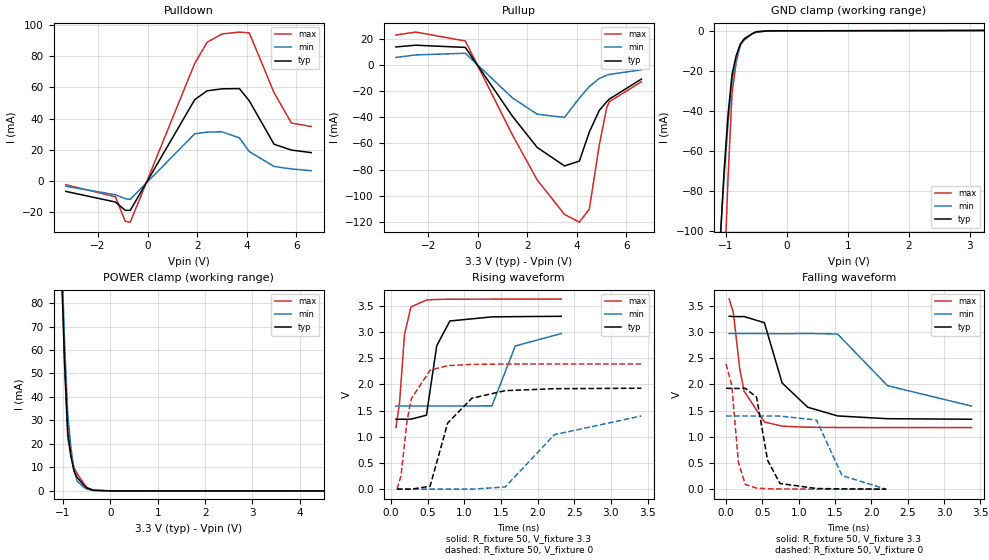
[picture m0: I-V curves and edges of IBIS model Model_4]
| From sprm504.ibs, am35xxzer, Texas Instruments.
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| Model based on original model for BC1833DV40CTPBFHP18LL_7LM
|   Sub model HP18LL_7LM_PD_ON_3P3
[model]   Model_4
|[Description]  3.3V-I/O-PD-X
|[Input Load]   PD
|[Output Drive]
|Voltage   3.3V
|Mode   I/O
Model_type   I/O
Polarity   Non-Inverting
Enable   Active-Low
Vinl =  0.8V
Vinh =  2V
Cref =  15pF
Rref =  100.0000M
Vref =  0V
Vmeas =  1.65
C_comp   1.943144p   1.721292p   2.064363p
[Model Spec]
Vinl   0.8V   0.8V   0.8V
Vinh   2V   2V   2V
[Temperature Range]   25   125   -40
[Voltage Range]   3.3   2.97   3.63
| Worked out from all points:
|   slope of the pulldown table from 0 to 0.495 V, typ, clamps not added: 31.5 ohm
|   slope of the pullup table from 0 to 0.495 V, typ, clamps not added: 34.6 ohm
|   GND clamp passes 1 mA (typ) near -0.54 V on its own axis
|   POWER clamp passes 1 mA (typ) near -0.47 V on its own axis
|   rising waveform, R_fixture 50, V_fixture 3.3: 20-80 % time 130ps typ, 194ps min, 86.4ps max; typ from 1.33 V to 3.3 V
|   rising waveform, R_fixture 50, V_fixture 0: 20-80 % time 307ps typ, 705ps min, 172ps max; typ from 0 V to 1.93 V
|   falling waveform, R_fixture 50, V_fixture 3.3: 20-80 % time 359ps typ, 776ps min, 182ps max; typ from 3.3 V to 1.33 V
|   falling waveform, R_fixture 50, V_fixture 0: 20-80 % time 150ps typ, 232ps min, 88.8ps max; typ from 1.93 V to 0 V
[POWER_clamp]
-3.3V     2.432A     2.868A     2.62A
-1.033V   95.16mA    103.3mA    97mA
-966.7mV  55mA       63.41mA    53.17mA
-900mV    25.28mA    32.79mA    22.49mA
-833.3mV  14.83mA    18.47mA    14.88mA
-766.7mV  8.299mA    8.929mA    9.847mA
-700mV    5.694mA    4.162mA    7.387mA
-566.7mV  2.611mA    1.646mA    3.301mA
-500mV    1.319mA    827.8uA    1.568mA
-366.7mV  287.8uA    192.2uA    368.8uA
33.33mV   0A         0A         0A
6.6V      0A         0A         0A
[Pulldown]
-3.3V     -6.725mA   -3.434mA   -2.443mA
-1.3V     -13.53mA   -8.888mA   -10.15mA
-900mV    -18.85mA   -11.39mA   -25.88mA
-700mV    -18.89mA   -11.82mA   -26.46mA
1.9V      52.07mA    30.2mA     75.32mA
2.4V      57.75mA    31.28mA    88.86mA
3V        59.01mA    31.49mA    94.2mA
3.7V      59.19mA    27.61mA    95.39mA
4.1V      51.39mA    18.8mA     94.89mA
5.1V      23.52mA    9.29mA     56.6mA
5.8V      19.77mA    7.67mA     37.13mA
6.6V      18.13mA    6.544mA    34.86mA
[Pullup]
-3.3V     13.83mA    5.807mA    23.01mA
-2.5V     15.14mA    7.704mA    25.18mA
-500mV    13.45mA    8.979mA    18.37mA
1.4V      -39.2mA    -25.2mA    -53.56mA
2.4V      -63.13mA   -37.64mA   -88mA
3.5V      -77.24mA   -40.1mA    -114.3mA
4.1V      -73.54mA   -25.36mA   -120.3mA
4.5V      -51.37mA   -16.52mA   -110.3mA
4.9V      -34.86mA   -10.34mA   -61.5mA
5.2V      -28.21mA   -7.863mA   -32.95mA
5.3V      -26.19mA   -7.237mA   -28.18mA
6.6V      -10.79mA   -3.71mA    -12.85mA
[GND_clamp]
-3.3V     -2.048A    -1.805A    -3.667A
-1.1V     -108.6mA   -106.5mA   -191.4mA
-1.033V   -71.11mA   -74.03mA   -127.7mA
-966.7mV  -42.17mA   -46.82mA   -74.25mA
-900mV    -21.74mA   -24.87mA   -31.11mA
-833.3mV  -12.59mA   -14.47mA   -16.1mA
-766.7mV  -6.71mA    -7.469mA   -7.269mA
-700mV    -4.089mA   -3.883mA   -4.623mA
-566.7mV  -1.428mA   -1.487mA   -1.361mA
-500mV    -525.6uA   -699.5uA   -401.5uA
-300mV    -31.04uA   -34.98uA   -39.83uA
3.233V    152.3uA    97.64uA    242.6uA
[Ramp]
dV/dt_f  1.1903092/0.35806948n 0.84566914/0.75923509n  1.4749349/0.18087527n
dV/dt_r  1.1633665/0.30323133n 0.84440633/0.69523171n  1.4405308/0.16987649n
R_load = 50
[Rising Waveform]
R_fixture = 50
V_fixture = 3.3
V_fixture_min = 2.97
V_fixture_max = 3.63
67.88ps   1.334V     1.585V     1.175V
116.9ps   1.334V     1.585V     1.643V
185.2ps   1.334V     1.585V     2.951V
272.3ps   1.334V     1.585V     3.476V
484.1ps   1.411V     1.585V     3.608V
624.8ps   2.736V     1.585V     3.619V
804.2ps   3.208V     1.585V     3.623V
1.378ns   3.286V     1.589V     3.625V
1.696ns   3.291V     2.731V     3.625V
2.323ns   3.297V     2.968V     3.626V
[Rising Waveform]
R_fixture = 50
V_fixture = 0
V_fixture_min = 0
V_fixture_max = 0
82.23ps   8.38nV     117.7nV    4.053nV
138ps     -212.8nV   510.9nV    260.9mV
219.5ps   25.12uV    7.526nV    1.301V
277.9ps   -342.8uV   -105.3nV   1.724V
533.8ps   54.85mV    -45.66nV   2.27V
773.9ps   1.261V     -27.74nV   2.356V
1.104ns   1.734V     -464.5uV   2.38V
1.559ns   1.879V     41.72mV    2.386V
2.229ns   1.916V     1.039V     2.387V
3.416ns   1.925V     1.396V     2.387V
[Falling Waveform]
R_fixture = 50
V_fixture = 3.3
V_fixture_min = 2.97
V_fixture_max = 3.63
43.08ps   3.297V     2.968V     3.626V
100.8ps   3.293V     2.968V     3.364V
188.4ps   3.291V     2.968V     2.295V
248ps     3.293V     2.968V     1.872V
527ps     3.175V     2.968V     1.282V
771.5ps   2.025V     2.965V     1.202V
1.123ns   1.563V     2.97V      1.181V
1.534ns   1.397V     2.959V     1.176V
2.221ns   1.344V     1.974V     1.175V
3.376ns   1.334V     1.585V     1.175V
[Falling Waveform]
R_fixture = 50
V_fixture = 0
V_fixture_min = 0
V_fixture_max = 0
0s        1.925V     1.396V     2.387V
79.09ps   1.922V     1.396V     1.981V
169.2ps   1.921V     1.396V     518mV
264.7ps   1.924V     1.396V     87.48mV
419.9ps   1.755V     1.396V     20mV
571.3ps   552.1mV    1.395V     9.301mV
741.1ps   108.3mV    1.394V     4.229mV
1.245ns   12.81mV    1.318V     248uV
1.595ns   5.433mV    259.1mV    34.33uV
2.203ns   8.38nV     117.7nV    4.053nV
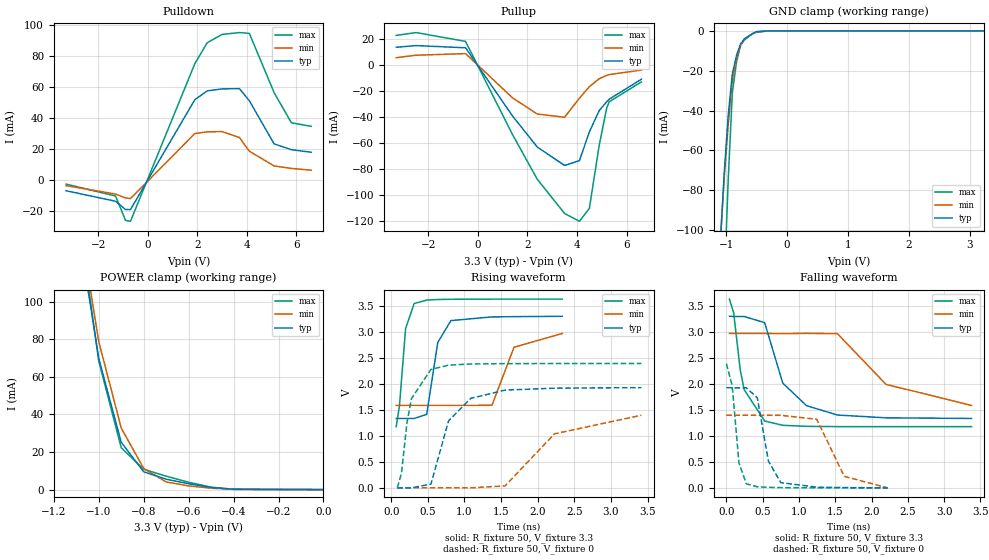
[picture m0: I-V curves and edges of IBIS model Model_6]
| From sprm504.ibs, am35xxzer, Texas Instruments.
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| Model based on original model for BC1833DV40CTPBFHP18LL_7LM
|   Sub model LL_7LM_PD_PU_OFF_3P3
[model]   Model_6
|[Description]  3.3V-I/O-PI-X
|[Input Load]   PI
|[Output Drive]
|Voltage   3.3V
|Mode   I/O
Model_type   I/O
Polarity   Non-Inverting
Enable   Active-Low
Vinl =  0.8V
Vinh =  2V
Cref =  15pF
Rref =  100.0000M
Vref =  0V
Vmeas =  1.65
C_comp   1.943144p   1.721292p   2.064363p
[Model Spec]
Vinl   0.8V   0.8V   0.8V
Vinh   2V   2V   2V
[Temperature Range]   25   125   -40
[Voltage Range]   3.3   2.97   3.63
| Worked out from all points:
|   slope of the pulldown table from 0 to 0.495 V, typ, clamps not added: 31.5 ohm
|   slope of the pullup table from 0 to 0.495 V, typ, clamps not added: 34.6 ohm
|   GND clamp passes 1 mA (typ) near -0.54 V on its own axis
|   POWER clamp passes 1 mA (typ) near -0.48 V on its own axis
|   rising waveform, R_fixture 50, V_fixture 3.3: 20-80 % time 131ps typ, 193ps min, 86.5ps max; typ from 1.33 V to 3.3 V
|   rising waveform, R_fixture 50, V_fixture 0: 20-80 % time 305ps typ, 704ps min, 173ps max; typ from 0 V to 1.93 V
|   falling waveform, R_fixture 50, V_fixture 3.3: 20-80 % time 363ps typ, 775ps min, 183ps max; typ from 3.3 V to 1.33 V
|   falling waveform, R_fixture 50, V_fixture 0: 20-80 % time 151ps typ, 233ps min, 89ps max; typ from 1.93 V to 0 V
[POWER_clamp]
-3.3V     2.432A     2.868A     2.62A
-1.067V   120.3mA    127.7mA    125.3mA
-1.033V   95.04mA    103.2mA    96.8mA
-1V       69.74mA    78.67mA    68.31mA
-900mV    25.15mA    32.72mA    22.27mA
-800mV    9.462mA    11.24mA    10.84mA
-700mV    5.548mA    4.085mA    7.139mA
-600mV    3.106mA    1.975mA    3.91mA
-500mV    1.161mA    745uA      1.301mA
-400mV    184uA      153.2uA    143uA
0V        9.359nA    44.03nA    36.65nA
[Pulldown]
-3.3V     -6.725mA   -3.434mA   -2.443mA
-1.3V     -13.53mA   -8.888mA   -10.15mA
-900mV    -18.85mA   -11.39mA   -25.88mA
-700mV    -18.89mA   -11.82mA   -26.46mA
1.9V      52.07mA    30.2mA     75.33mA
2.4V      57.75mA    31.28mA    88.86mA
3V        59.01mA    31.49mA    94.2mA
3.7V      59.19mA    27.61mA    95.39mA
4.1V      51.39mA    18.8mA     94.89mA
5.1V      23.52mA    9.29mA     56.6mA
5.8V      19.77mA    7.67mA     37.13mA
6.6V      18.13mA    6.544mA    34.86mA
[Pullup]
-3.3V     13.83mA    5.807mA    23.01mA
-2.5V     15.14mA    7.704mA    25.18mA
-500mV    13.45mA    8.979mA    18.37mA
1.4V      -39.2mA    -25.2mA    -53.56mA
2.4V      -63.13mA   -37.64mA   -88mA
3.5V      -77.24mA   -40.1mA    -114.3mA
4.1V      -73.54mA   -25.36mA   -120.3mA
4.5V      -51.37mA   -16.52mA   -110.3mA
4.9V      -34.86mA   -10.34mA   -61.5mA
5.2V      -28.21mA   -7.863mA   -32.95mA
5.3V      -26.19mA   -7.237mA   -28.18mA
6.6V      -10.79mA   -3.71mA    -12.85mA
[GND_clamp]
-3.3V     -2.048A    -1.805A    -3.667A
-1.1V     -108.6mA   -106.5mA   -191.4mA
-1.033V   -71.11mA   -74.03mA   -127.7mA
-966.7mV  -42.16mA   -46.82mA   -74.24mA
-900mV    -21.73mA   -24.87mA   -31.1mA
-833.3mV  -12.58mA   -14.46mA   -16.07mA
-766.7mV  -6.691mA   -7.462mA   -7.232mA
-700mV    -4.066mA   -3.873mA   -4.582mA
-566.7mV  -1.404mA   -1.475mA   -1.319mA
-500mV    -501.5uA   -687.7uA   -361.4uA
-300mV    -14.92uA   -26.13uA   -14.52uA
3.233V    8.845nA    14.35uA    33.57nA
[Ramp]
dV/dt_f  1.1914605/0.35985548n 0.84628647/0.76208872n  1.4766815/0.18208318n
dV/dt_r  1.1646262/0.30420103n 0.84508829/0.69694574n  1.4424913/0.17054476n
R_load = 50
[Rising Waveform]
R_fixture = 50
V_fixture = 3.3
V_fixture_min = 2.97
V_fixture_max = 3.63
67.72ps   1.335V     1.586V     1.177V
112.3ps   1.335V     1.586V     1.578V
195.5ps   1.335V     1.586V     3.061V
313ps     1.335V     1.586V     3.546V
484ps     1.413V     1.586V     3.611V
635ps     2.796V     1.586V     3.623V
814.3ps   3.217V     1.586V     3.627V
1.375ns   3.288V     1.588V     3.63V
1.676ns   3.293V     2.704V     3.63V
2.335ns   3.3V       2.97V      3.63V
[Rising Waveform]
R_fixture = 50
V_fixture = 0
V_fixture_min = 0
V_fixture_max = 0
82.09ps   8.589nV    120.9nV    4.032nV
139.9ps   -231.2nV   495.5nV    279.1mV
214.1ps   20.36uV    26.53nV    1.246V
275.8ps   -310.8uV   -99.34nV   1.715V
541.6ps   71.72mV    -51.16nV   2.277V
782.8ps   1.289V     -36.51nV   2.36V
1.085ns   1.721V     -414.9uV   2.383V
1.554ns   1.88V      37.43mV    2.389V
2.229ns   1.917V     1.039V     2.391V
3.415ns   1.928V     1.397V     2.391V
[Falling Waveform]
R_fixture = 50
V_fixture = 3.3
V_fixture_min = 2.97
V_fixture_max = 3.63
43.1ps    3.3V       2.97V      3.63V
100.6ps   3.296V     2.97V      3.37V
191.8ps   3.294V     2.97V      2.266V
246.1ps   3.296V     2.97V      1.888V
527.4ps   3.178V     2.97V      1.286V
776.9ps   2.015V     2.967V     1.203V
1.103ns   1.582V     2.971V     1.183V
1.529ns   1.401V     2.967V     1.178V
2.198ns   1.347V     1.991V     1.177V
3.376ns   1.335V     1.586V     1.177V
[Falling Waveform]
R_fixture = 50
V_fixture = 0
V_fixture_min = 0
V_fixture_max = 0
0s        1.928V     1.397V     2.391V
80.48ps   1.924V     1.397V     1.968V
174.1ps   1.923V     1.397V     478.7mV
274.7ps   1.925V     1.397V     77.72mV
426.5ps   1.732V     1.397V     20.78mV
579.4ps   514mV      1.396V     10.22mV
750.7ps   100.5mV    1.396V     4.475mV
1.245ns   13.76mV    1.319V     321.6uV
1.624ns   5.758mV    221.2mV    47.05uV
2.223ns   8.589nV    120.9nV    4.032nV
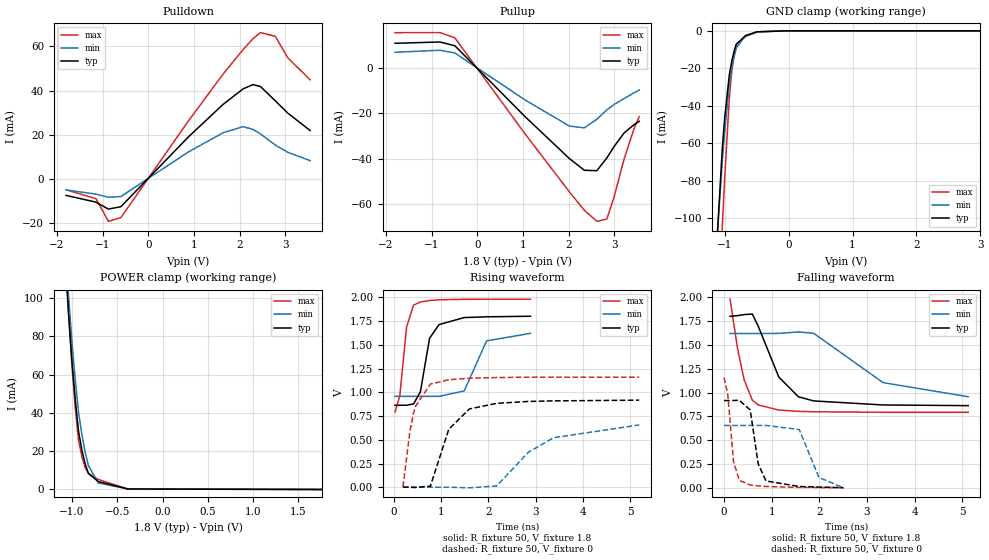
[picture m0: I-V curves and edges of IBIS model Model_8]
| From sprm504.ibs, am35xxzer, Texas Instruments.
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| Model based on original model for BC1833DV50BTPBFZP18LL_7LM
|   Sub model ZP18LL_7LM_PU_ON_1P8
[model]   Model_8
|[Description]  1.8V-I/O-PU-X
|[Input Load]   PU
|[Output Drive]
|Voltage   1.8V
|Mode   I/O
Model_type   I/O
Polarity   Non-Inverting
Enable   Active-Low
Vinl =  0.63V
Vinh =  1.17V
Cref =  15pF
Rref =  100.0000M
Vref =  0V
Vmeas =  0.9
C_comp   1.952094p   1.82457p   1.99685p
[Model Spec]
Vinl   0.63V   0.567V   0.693V
Vinh   1.17V   1.053V   1.287V
[Temperature Range]   25   125   -40
[Voltage Range]   1.8   1.62   1.98
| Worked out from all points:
|   slope of the pulldown table from 0 to 0.27 V, typ, clamps not added: 44.6 ohm
|   slope of the pullup table from 0 to 0.27 V, typ, clamps not added: 47.6 ohm
|   GND clamp passes 1 mA (typ) near -0.55 V on its own axis
|   POWER clamp passes 1 mA (typ) near -0.52 V on its own axis
|   rising waveform, R_fixture 50, V_fixture 1.8: 20-80 % time 212ps typ, 284ps min, 149ps max; typ from 0.864 V to 1.8 V
|   rising waveform, R_fixture 50, V_fixture 0: 20-80 % time 446ps typ, 981ps min, 245ps max; typ from 0.003 V to 0.917 V
|   falling waveform, R_fixture 50, V_fixture 1.8: 20-80 % time 530ps typ, 1.21ns min, 283ps max; typ from 1.8 V to 0.864 V
|   falling waveform, R_fixture 50, V_fixture 0: 20-80 % time 165ps typ, 255ps min, 125ps max; typ from 0.917 V to 0.003 V
[POWER_clamp]
-1.8V     833.3mA    863.1mA    901.2mA
-1.073V   119.5mA    128.1mA    123.5mA
-1.036V   90.84mA    100.3mA    91.31mA
-1V       67.07mA    77.23mA    64.67mA
-963.6mV  46.88mA    57.2mA     42.73mA
-927.3mV  30.28mA    40.18mA    25.52mA
-890.9mV  20.6mA     28.81mA    17.1mA
-854.5mV  13.26mA    19.49mA    11.33mA
-818.2mV  8.265mA    12.23mA    8.199mA
-709.1mV  3.977mA    3.264mA    5.102mA
-381.8mV  105.8uA    84.74uA    101.6uA
1.764V    -143.5uA   -80.1uA    -225.9uA
[Pulldown]
-1.8V     -7.339mA   -4.872mA   -4.803mA
-1.145V   -10.39mA   -6.769mA   -8.82mA
-872.7mV  -13.54mA   -8.159mA   -19.05mA
-600mV    -12.46mA   -7.873mA   -17.38mA
872.7mV   18.95mA    12.21mA    26.11mA
1.636V    33.73mA    20.94mA    47.4mA
2.073V    40.74mA    23.7mA     58.46mA
2.291V    42.72mA    22.53mA    63.43mA
2.455V    41.87mA    20.47mA    66.23mA
2.782V    35.36mA    15.4mA     64.52mA
3.055V    29.83mA    12.14mA    54.79mA
3.545V    21.95mA    8.339mA    44.87mA
[Pullup]
-1.8V     10.72mA    6.784mA    15.4mA
-818.2mV  11.29mA    7.651mA    15.44mA
-490.9mV  9.653mA    6.484mA    13.12mA
1.036V    -21.34mA   -14.06mA   -28.84mA
2.018V    -39.99mA   -25.69mA   -54.63mA
2.345V    -45.12mA   -26.45mA   -62.75mA
2.618V    -45.29mA   -22.66mA   -67.55mA
2.836V    -39.69mA   -18.55mA   -66.59mA
3V        -34.54mA   -16.15mA   -56.48mA
3.218V    -28.61mA   -13.52mA   -39.88mA
3.436V    -25.01mA   -11.02mA   -26.57mA
3.545V    -23.56mA   -9.84mA    -21.49mA
[GND_clamp]
-1.8V     -667.9mA   -536.4mA   -1.146A
-1.109V   -105.8mA   -105.8mA   -173mA
-1.036V   -62.26mA   -69.36mA   -103.9mA
-1V       -46.8mA    -54.07mA   -78.95mA
-927.3mV  -23.56mA   -28.69mA   -36.16mA
-890.9mV  -16.62mA   -20.65mA   -22.4mA
-854.5mV  -11.15mA   -14.15mA   -12.8mA
-818.2mV  -7.146mA   -9.205mA   -7.373mA
-672.7mV  -2.583mA   -2.428mA   -3.006mA
-490.9mV  -511.9uA   -524.2uA   -577.2uA
-18.18mV  0A         0A         0A
3.6V      0A         0A         0A
[Ramp]
dV/dt_f 0.57889791/0.53399981n 0.41189208/1.2223151n 0.72381152/0.28408484n
dV/dt_r 0.56192919/0.44445794n 0.40387502/0.98092959n 0.70099312/0.24594095n
R_load = 50
[Rising Waveform]
R_fixture = 50
V_fixture = 1.8
V_fixture_min = 1.62
V_fixture_max = 1.98
24.52ps   863.7mV    957.3mV    793.8mV
123.8ps   863.7mV    957.3mV    960.3mV
269.6ps   863.4mV    957.3mV    1.689V
416.9ps   878.4mV    957.3mV    1.917V
560.9ps   1.005V     957.3mV    1.95V
755.3ps   1.569V     957.3mV    1.966V
954.5ps   1.712V     957.3mV    1.973V
1.487ns   1.786V     1.014V     1.978V
1.963ns   1.794V     1.541V     1.979V
2.89ns    1.8V       1.62V      1.98V
[Rising Waveform]
R_fixture = 50
V_fixture = 0
V_fixture_min = 0
V_fixture_max = 0
191.5ps   3.423mV    2.084mV    4.971mV
340.1ps   830.2uV    2.086mV    592.9mV
442.8ps   -1.878mV   2.084mV    841.4mV
771.8ps   12.63mV    2.081mV    1.086V
1.162ns   611.5mV    1.881mV    1.132V
1.597ns   824.7mV    -5.361mV   1.148V
2.175ns   883.8mV    14.96mV    1.155V
2.846ns   903.7mV    368.7mV    1.159V
3.379ns   909.7mV    522.1mV    1.159V
5.192ns   917.2mV    656.3mV    1.159V
[Falling Waveform]
R_fixture = 50
V_fixture = 1.8
V_fixture_min = 1.62
V_fixture_max = 1.98
126ps     1.8V       1.62V      1.98V
285.1ps   1.807V     1.62V      1.455V
423.5ps   1.818V     1.62V      1.131V
593.7ps   1.824V     1.62V      920.8mV
720.1ps   1.693V     1.62V      870.8mV
1.148ns   1.164V     1.621V     817.8mV
1.562ns   956.3mV    1.636V     804.2mV
1.881ns   913.2mV    1.622V     799.4mV
3.338ns   870.9mV    1.105V     794.1mV
5.126ns   863.7mV    957.3mV    793.8mV
[Falling Waveform]
R_fixture = 50
V_fixture = 0
V_fixture_min = 0
V_fixture_max = 0
0s        917.2mV    656.3mV    1.159V
77.34ps   917.1mV    656.3mV    981.5mV
198.6ps   917.9mV    656.3mV    277.2mV
320.2ps   920mV      656.3mV    80.98mV
549.2ps   817.8mV    656.3mV    32.35mV
716.6ps   252.6mV    656.3mV    22.04mV
880ps     74.78mV    656.4mV    16.86mV
1.578ns   16.15mV    613.1mV    6.746mV
1.991ns   10.45mV    111.6mV    5.523mV
2.509ns   3.423mV    2.084mV    4.971mV
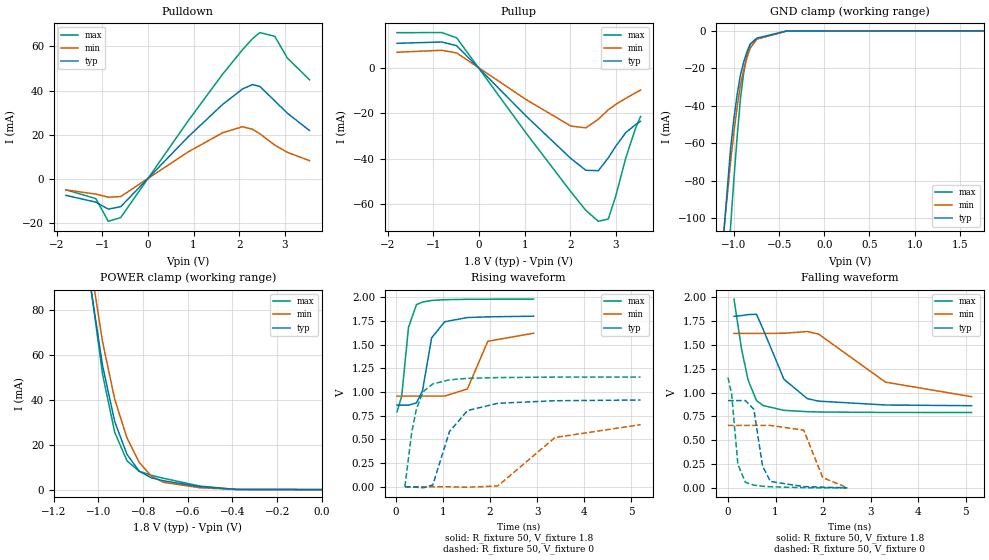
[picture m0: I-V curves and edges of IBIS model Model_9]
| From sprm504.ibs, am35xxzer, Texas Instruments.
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| Model based on original model for BC1833DV50BTPBFZP18LL_7LM
|   Sub model LL_7LM_PD_PU_OFF_1P8
[model]   Model_9
|[Description]  1.8V-I/O-PI-X
|[Input Load]   PI
|[Output Drive]
|Voltage   1.8V
|Mode   I/O
Model_type   I/O
Polarity   Non-Inverting
Enable   Active-Low
Vinl =  0.63V
Vinh =  1.17V
Cref =  15pF
Rref =  100.0000M
Vref =  0V
Vmeas =  0.9
C_comp   1.952094p   1.82457p   1.99685p
[Model Spec]
Vinl   0.63V   0.567V   0.693V
Vinh   1.17V   1.053V   1.287V
[Temperature Range]   25   125   -40
[Voltage Range]   1.8   1.62   1.98
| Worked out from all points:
|   slope of the pulldown table from 0 to 0.27 V, typ, clamps not added: 44.6 ohm
|   slope of the pullup table from 0 to 0.27 V, typ, clamps not added: 47.6 ohm
|   GND clamp passes 1 mA (typ) near -0.57 V on its own axis
|   POWER clamp passes 1 mA (typ) near -0.52 V on its own axis
|   rising waveform, R_fixture 50, V_fixture 1.8: 20-80 % time 215ps typ, 285ps min, 150ps max; typ from 0.862 V to 1.8 V
|   rising waveform, R_fixture 50, V_fixture 0: 20-80 % time 448ps typ, 986ps min, 247ps max; typ from 0 V to 0.915 V
|   falling waveform, R_fixture 50, V_fixture 1.8: 20-80 % time 530ps typ, 1.21ns min, 283ps max; typ from 1.8 V to 0.862 V
|   falling waveform, R_fixture 50, V_fixture 0: 20-80 % time 166ps typ, 256ps min, 125ps max; typ from 0.915 V to 0 V
[POWER_clamp]
-1.8V     833.3mA    863.1mA    901.2mA
-1.055V   105.1mA    114.2mA    107.4mA
-1.036V   90.81mA    100.3mA    91.25mA
-981.8mV  55.15mA    65.69mA    51.29mA
-927.3mV  30.24mA    40.16mA    25.46mA
-872.7mV  15.72mA    23.1mA     12.83mA
-818.2mV  8.229mA    12.21mA    8.14mA
-763.6mV  5.264mA    6.024mA    6.384mA
-709.1mV  3.941mA    3.245mA    5.044mA
-545.5mV  1.299mA    814.7uA    1.567mA
-381.8mV  77.04uA    69.31uA    55.06uA
0V        17.8nA     61.41nA    29.21nA
[Pulldown]
-1.8V     -7.339mA   -4.872mA   -4.803mA
-1.145V   -10.39mA   -6.769mA   -8.819mA
-872.7mV  -13.54mA   -8.159mA   -19.05mA
-600mV    -12.46mA   -7.873mA   -17.38mA
872.7mV   18.95mA    12.21mA    26.11mA
1.636V    33.73mA    20.94mA    47.4mA
2.073V    40.74mA    23.7mA     58.46mA
2.291V    42.72mA    22.53mA    63.43mA
2.455V    41.87mA    20.47mA    66.23mA
2.782V    35.36mA    15.4mA     64.52mA
3.055V    29.83mA    12.14mA    54.79mA
3.545V    21.95mA    8.339mA    44.87mA
[Pullup]
-1.8V     10.72mA    6.784mA    15.4mA
-818.2mV  11.29mA    7.651mA    15.44mA
-490.9mV  9.653mA    6.484mA    13.12mA
1.036V    -21.34mA   -14.06mA   -28.84mA
2.018V    -39.99mA   -25.69mA   -54.63mA
2.345V    -45.12mA   -26.45mA   -62.75mA
2.618V    -45.29mA   -22.66mA   -67.55mA
2.836V    -39.69mA   -18.55mA   -66.58mA
3V        -34.54mA   -16.15mA   -56.48mA
3.218V    -28.61mA   -13.52mA   -39.88mA
3.436V    -25.01mA   -11.02mA   -26.56mA
3.545V    -23.56mA   -9.84mA    -21.49mA
[GND_clamp]
-1.8V     -667.9mA   -536.4mA   -1.146A
-1.109V   -105.7mA   -105.8mA   -172.9mA
-1.036V   -62.16mA   -69.32mA   -103.8mA
-1V       -46.7mA    -54.02mA   -78.8mA
-963.6mV  -33.78mA   -40.45mA   -56.19mA
-927.3mV  -23.42mA   -28.63mA   -35.94mA
-890.9mV  -16.47mA   -20.58mA   -22.14mA
-854.5mV  -10.98mA   -14.08mA   -12.51mA
-818.2mV  -6.97mA    -9.126mA   -7.056mA
-745.5mV  -3.872mA   -4.367mA   -4.345mA
-418.2mV  -109.9uA   -163.2uA   -95.18uA
1.764V    17.35nA    376.2nA    24.84nA
[Ramp]
dV/dt_f 0.58001557/0.53510128n  0.4124361/1.2238246n 0.72565468/0.28466666n
dV/dt_r 0.56396233/0.44660007n 0.40499873/0.98408939n 0.70324811/0.24748084n
R_load = 50
[Rising Waveform]
R_fixture = 50
V_fixture = 1.8
V_fixture_min = 1.62
V_fixture_max = 1.98
25.05ps   861.8mV    956.4mV    790.7mV
124ps     861.8mV    956.4mV    956mV
269.6ps   861.5mV    956.4mV    1.684V
437.5ps   884.3mV    956.4mV    1.922V
565.4ps   1.012V     956.4mV    1.949V
760.2ps   1.572V     956.4mV    1.966V
1.037ns   1.741V     956.4mV    1.974V
1.52ns    1.786V     1.033V     1.978V
1.951ns   1.793V     1.535V     1.979V
2.922ns   1.8V       1.62V      1.98V
[Rising Waveform]
R_fixture = 50
V_fixture = 0
V_fixture_min = 0
V_fixture_max = 0
193.1ps   9.762nV    93.73nV    10.68nV
332.5ps   -1.908mV   2.243uV    558.6mV
434.2ps   -5.252mV   304.1nV    818.4mV
581.9ps   -11.93mV   -1.516uV   1.004V
783.7ps   18.31mV    -2.397uV   1.085V
1.137ns   581.1mV    -133.3uV   1.128V
1.523ns   804.6mV    -5.877mV   1.144V
2.165ns   880.7mV    8.688mV    1.152V
3.378ns   907.6mV    519.6mV    1.157V
5.193ns   915.5mV    655mV      1.157V
[Falling Waveform]
R_fixture = 50
V_fixture = 1.8
V_fixture_min = 1.62
V_fixture_max = 1.98
126.1ps   1.8V       1.62V      1.98V
285.2ps   1.807V     1.62V      1.455V
423.6ps   1.818V     1.62V      1.13V
599.4ps   1.821V     1.62V      915.7mV
741.7ps   1.661V     1.62V      863.2mV
1.177ns   1.139V     1.622V     813.4mV
1.668ns   936.2mV    1.64V      799.2mV
1.907ns   909.8mV    1.613V     796mV
3.315ns   869.4mV    1.109V     791mV
5.126ns   861.8mV    956.4mV    790.7mV
[Falling Waveform]
R_fixture = 50
V_fixture = 0
V_fixture_min = 0
V_fixture_max = 0
0s        915.5mV    655mV      1.157V
77.12ps   915.3mV    655mV      980.4mV
207.6ps   916.1mV    655mV      245.9mV
365.9ps   915.9mV    655mV      58.59mV
543.8ps   824.3mV    655mV      28.44mV
726.3ps   228.6mV    655mV      16.96mV
892.7ps   67.18mV    655.2mV    11.69mV
1.594ns   12.93mV    605.2mV    1.702mV
1.993ns   7.37mV     108.2mV    549.2uV
2.515ns   9.762nV    93.73nV    10.68nV
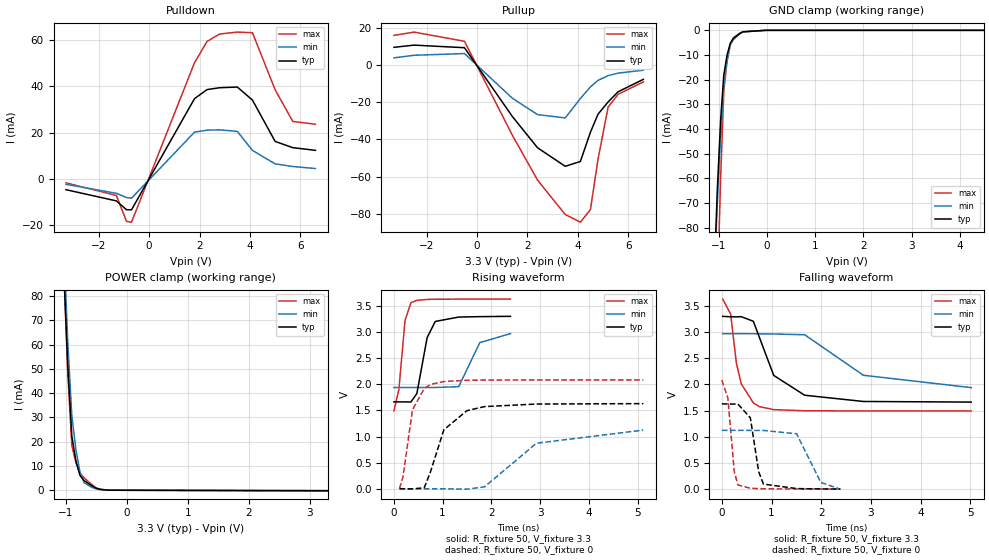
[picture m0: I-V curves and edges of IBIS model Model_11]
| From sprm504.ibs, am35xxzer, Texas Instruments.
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| Model based on original model for BC1833DV50BTPBFZP18LL_7LM
|   Sub model ZP18LL_7LM_PU_ON_3P3
[model]   Model_11
|[Description]  3.3V-I/O-PU-X
|[Input Load]   PU
|[Output Drive]
|Voltage   3.3V
|Mode   I/O
Model_type   I/O
Polarity   Non-Inverting
Enable   Active-Low
Vinl =  0.8V
Vinh =  2V
Cref =  15pF
Rref =  100.0000M
Vref =  0V
Vmeas =  1.65
C_comp   1.683006p   1.492615p   1.787227p
[Model Spec]
Vinl   0.8V   0.8V   0.8V
Vinh   2V   2V   2V
[Temperature Range]   25   125   -40
[Voltage Range]   3.3   2.97   3.63
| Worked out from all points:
|   slope of the pulldown table from 0 to 0.495 V, typ, clamps not added: 44.6 ohm
|   slope of the pullup table from 0 to 0.495 V, typ, clamps not added: 49.2 ohm
|   GND clamp passes 1 mA (typ) near -0.54 V on its own axis
|   POWER clamp passes 1 mA (typ) near -0.51 V on its own axis
|   rising waveform, R_fixture 50, V_fixture 3.3: 20-80 % time 192ps typ, 276ps min, 120ps max; typ from 1.66 V to 3.3 V
|   rising waveform, R_fixture 50, V_fixture 0: 20-80 % time 424ps typ, 980ps min, 230ps max; typ from 0.004 V to 1.63 V
|   falling waveform, R_fixture 50, V_fixture 3.3: 20-80 % time 512ps typ, 989ps min, 229ps max; typ from 3.3 V to 1.66 V
|   falling waveform, R_fixture 50, V_fixture 0: 20-80 % time 154ps typ, 283ps min, 108ps max; typ from 1.63 V to 0.004 V
[POWER_clamp]
-3.3V     2.414A     2.855A     2.597A
-1.033V   91.28mA    100.7mA    91.91mA
-966.7mV  51.52mA    61.14mA    48.58mA
-900mV    22.2mA     30.8mA     18.38mA
-833.3mV  12.2mA     16.79mA    11.38mA
-766.7mV  6.143mA    7.564mA    6.979mA
-700mV    4.019mA    3.112mA    5.166mA
-566.7mV  1.785mA    1.14mA     2.219mA
-500mV    851.8uA    543.9uA    965.7uA
-433.3mV  384.1uA    260.8uA    410.7uA
-300mV    24.71uA    21.59uA    29.06uA
3.3V      -177.5uA   -136.2uA   -277.3uA
[Pulldown]
-3.3V     -4.655mA   -2.337mA   -1.677mA
-1.3V     -9.504mA   -6.223mA   -7.163mA
-900mV    -13.3mA    -8.026mA   -18.36mA
-700mV    -13.35mA   -8.345mA   -18.7mA
1.8V      34.68mA    20.21mA    50.21mA
2.3V      38.61mA    21.07mA    59.44mA
2.8V      39.41mA    21.2mA     62.61mA
3.5V      39.7mA     20.55mA    63.45mA
4.1V      34.07mA    12.32mA    63.18mA
5V        16.21mA    6.501mA    38.53mA
5.7V      13.51mA    5.366mA    24.85mA
6.6V      12.35mA    4.495mA    23.63mA
[Pullup]
-3.3V     9.687mA    4.009mA    16.14mA
-2.5V     10.88mA    5.407mA    17.91mA
-500mV    9.486mA    6.336mA    12.94mA
1.4V      -27.6mA    -17.76mA   -37.69mA
2.4V      -44.47mA   -26.6mA    -61.92mA
3.5V      -54.49mA   -28.37mA   -80.48mA
4.1V      -51.87mA   -17.91mA   -84.62mA
4.5V      -36.09mA   -11.65mA   -77.77mA
4.8V      -26.39mA   -8.135mA   -50.71mA
5.2V      -19.78mA   -5.578mA   -22.57mA
5.6V      -14.26mA   -4.206mA   -15.61mA
6.6V      -7.577mA   -2.662mA   -8.942mA
[GND_clamp]
-3.3V     -1.975A    -1.766A    -3.378A
-1.1V     -99.48mA   -100.9mA   -162.1mA
-1.033V   -63.84mA   -69.36mA   -106.2mA
-966.7mV  -36.69mA   -43.1mA    -60.37mA
-900mV    -18.03mA   -22.08mA   -24.58mA
-833.3mV  -10.18mA   -12.46mA   -12.65mA
-766.7mV  -5.239mA   -6.112mA   -5.698mA
-700mV    -3.207mA   -3.033mA   -3.732mA
-566.7mV  -1.248mA   -1.197mA   -1.338mA
-500mV    -586.1uA   -614.6uA   -635uA
-33.33mV  0A         0A         0A
6.6V      0A         0A         0A
[Ramp]
dV/dt_f 0.98186181/0.50571511n 0.61795928/0.98353118n  1.2807807/0.22769256n
dV/dt_r 0.98102011/0.42248504n 0.67824879/0.97188799n   1.251451/0.22966431n
R_load = 50
[Rising Waveform]
R_fixture = 50
V_fixture = 3.3
V_fixture_min = 2.97
V_fixture_max = 3.63
2.243ps   1.664V     1.94V      1.495V
104.4ps   1.664V     1.94V      1.903V
229.4ps   1.664V     1.94V      3.217V
350.7ps   1.662V     1.94V      3.561V
472.9ps   1.825V     1.94V      3.606V
683.3ps   2.892V     1.94V      3.623V
849.5ps   3.202V     1.94V      3.627V
1.331ns   3.286V     1.955V     3.629V
1.763ns   3.294V     2.797V     3.63V
2.392ns   3.3V       2.97V      3.63V
[Rising Waveform]
R_fixture = 50
V_fixture = 0
V_fixture_min = 0
V_fixture_max = 0
116.9ps   4.13mV     2.525mV    5.944mV
188.3ps   4.135mV    2.525mV    233.2mV
382.9ps   711uV      2.525mV    1.513V
623.9ps   22.8mV     2.525mV    1.921V
748.7ps   317.9mV    2.525mV    1.995V
1.026ns   1.131V     2.539mV    2.054V
1.5ns     1.497V     -4.413mV   2.077V
1.859ns   1.574V     39.56mV    2.081V
2.925ns   1.623V     873.6mV    2.084V
5.117ns   1.631V     1.125V     2.084V
[Falling Waveform]
R_fixture = 50
V_fixture = 3.3
V_fixture_min = 2.97
V_fixture_max = 3.63
17.83ps   3.3V       2.97V      3.63V
177.1ps   3.292V     2.97V      3.344V
293.7ps   3.291V     2.97V      2.401V
389.8ps   3.294V     2.97V      2.015V
633.9ps   3.206V     2.968V     1.649V
752.5ps   2.907V     2.966V     1.578V
1.044ns   2.173V     2.964V     1.52V
1.666ns   1.795V     2.949V     1.499V
2.847ns   1.676V     2.176V     1.495V
5.018ns   1.664V     1.94V      1.495V
[Falling Waveform]
R_fixture = 50
V_fixture = 0
V_fixture_min = 0
V_fixture_max = 0
0s        1.631V     1.125V     2.084V
122.4ps   1.627V     1.125V     1.735V
250.1ps   1.627V     1.125V     335.8mV
323.4ps   1.627V     1.125V     83.86mV
573.4ps   1.364V     1.124V     19.89mV
741.3ps   336.7mV    1.123V     12.71mV
836ps     99.76mV    1.123V     10.08mV
1.505ns   13.26mV    1.059V     6.076mV
1.99ns    7.353mV    130.9mV    5.961mV
2.385ns   4.13mV     2.525mV    5.944mV
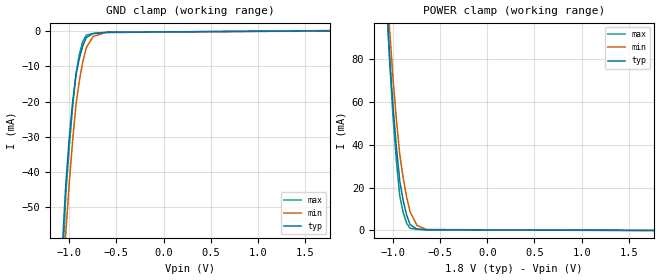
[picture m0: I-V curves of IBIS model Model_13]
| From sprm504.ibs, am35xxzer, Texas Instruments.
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| Model based on original model for IC1833DVTPBFZP18LL_7LM
|   Sub model 7LM_!PI_!PUPDSEL_1P8
[model]   Model_13
|[Description]  1.8V-INPUT-PD-X
|[Input Load]   PD
|[Output Drive]
|Voltage   1.8V
|Mode   INPUT
Model_type   Input
Polarity   Non-Inverting
Vinl =  0.63V
Vinh =  1.17V
C_comp   1.254226p   1.200533p   1.264851p
[Model Spec]
Vinl   0.63V   0.567V   0.693V
Vinh   1.17V   1.053V   1.287V
[Temperature Range]   25   125   -40
[Voltage Range]   1.8   1.62   1.98
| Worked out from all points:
|   GND clamp passes 1 mA (typ) near -0.78 V on its own axis
|   POWER clamp passes 1 mA (typ) near -0.76 V on its own axis
[POWER_clamp]
-1.8V     812.6mA    848.7mA    874.9mA
-1.073V   110.1mA    121.8mA    111.5mA
-1.036V   82.05mA    94.39mA    79.98mA
-1V       58.78mA    71.71mA    53.95mA
-963.6mV  39.1mA     52.05mA    32.63mA
-927.3mV  23.01mA    35.4mA     16.03mA
-890.9mV  13.9mA     24.43mA    8.35mA
-854.5mV  7.152mA    15.52mA    3.351mA
-818.2mV  2.762mA    8.67mA     1.037mA
-745.5mV  610.8uA    2.39mA     533uA
-636.4mV  266.5uA    276.6uA    421.8uA
1.764V    3.127uA    -7.306uA   29.52uA
[GND_clamp]
-1.8V     -593.4mA   -494.6mA   -853.3mA
-1.073V   -62.14mA   -74.14mA   -68.27mA
-1.036V   -43.78mA   -57.66mA   -46.67mA
-1V       -30.76mA   -43.65mA   -33.12mA
-963.6mV  -20.29mA   -31.35mA   -21.59mA
-927.3mV  -12.34mA   -20.77mA   -12.06mA
-890.9mV  -7.584mA   -13.9mA    -6.435mA
-854.5mV  -4.05mA    -8.522mA   -2.773mA
-818.2mV  -1.744mA   -4.623mA   -1.075mA
-745.5mV  -590uA     -1.44mA    -606.5uA
-600mV    -239.8uA   -203.1uA   -329.9uA
1.764V    148.6uA    81.33uA    236.4uA
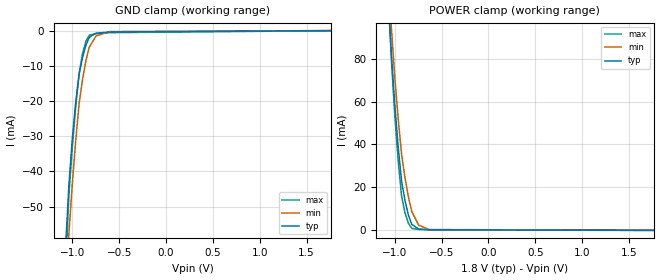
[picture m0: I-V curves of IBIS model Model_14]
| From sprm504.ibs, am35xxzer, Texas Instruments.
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| Model based on original model for IC1833DVTPBFZP18LL_7LM
|   Sub model _7LM_!PI_PUPDSEL_1P8
[model]   Model_14
|[Description]  1.8V-INPUT-PU-X
|[Input Load]   PU
|[Output Drive]
|Voltage   1.8V
|Mode   INPUT
Model_type   Input
Polarity   Non-Inverting
Vinl =  0.63V
Vinh =  1.17V
C_comp   1.254226p   1.200533p   1.264851p
[Model Spec]
Vinl   0.63V   0.567V   0.693V
Vinh   1.17V   1.053V   1.287V
[Temperature Range]   25   125   -40
[Voltage Range]   1.8   1.62   1.98
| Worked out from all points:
|   GND clamp passes 1 mA (typ) near -0.77 V on its own axis
|   POWER clamp passes 1 mA (typ) near -0.77 V on its own axis
[POWER_clamp]
-1.8V     812.4mA    848.7mA    874.7mA
-1.073V   110mA      121.8mA    111.3mA
-1.036V   81.9mA     94.32mA    79.73mA
-1V       58.64mA    71.64mA    53.7mA
-963.6mV  38.96mA    51.98mA    32.38mA
-927.3mV  22.86mA    35.33mA    15.77mA
-890.9mV  13.75mA    24.36mA    8.087mA
-854.5mV  7.001mA    15.45mA    3.086mA
-818.2mV  2.61mA     8.596mA    770.5uA
-745.5mV  458.2uA    2.315mA    265.9uA
-636.4mV  113.9uA    201.3uA    155uA
1.764V    -143.5uA   -79.91uA   -225.9uA
[GND_clamp]
-1.8V     -593.4mA   -494.6mA   -853.4mA
-1.073V   -62.22mA   -74.18mA   -68.37mA
-1.036V   -43.86mA   -57.7mA    -46.78mA
-1V       -30.86mA   -43.69mA   -33.26mA
-963.6mV  -20.39mA   -31.4mA    -21.75mA
-927.3mV  -12.46mA   -20.82mA   -12.26mA
-890.9mV  -7.709mA   -13.96mA   -6.656mA
-854.5mV  -4.183mA   -8.582mA   -3.011mA
-818.2mV  -1.883mA   -4.688mA   -1.321mA
-745.5mV  -733uA     -1.51mA    -854.7uA
-600mV    -384uA     -274.9uA   -579.4uA
1.764V    -2.901uA   6.404uA    -27.37uA
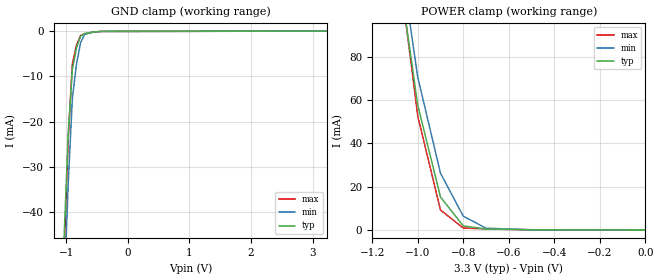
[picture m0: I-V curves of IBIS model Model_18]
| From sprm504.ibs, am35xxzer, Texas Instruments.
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| Model based on original model for IC1833DVTPBFZP18LL_7LM
|   Sub model PBFZP18LL_7LM_PI_3P3
[model]   Model_18
|[Description]  3.3V-INPUT-PI-X
|[Input Load]   PI
|[Output Drive]
|Voltage   3.3V
|Mode   INPUT
Model_type   Input
Polarity   Non-Inverting
Vinl =  0.8V
Vinh =  2V
C_comp   1.012258p   0.8890016p   1.091755p
[Model Spec]
Vinl   0.8V   0.8V   0.8V
Vinh   2V   2V   2V
[Temperature Range]   25   125   -40
[Voltage Range]   3.3   2.97   3.63
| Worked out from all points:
|   GND clamp passes 1 mA (typ) near -0.75 V on its own axis
|   POWER clamp passes 1 mA (typ) near -0.74 V on its own axis
[POWER_clamp]
-3.3V     2.37A      2.826A     2.542A
-1.067V   107.1mA    118.9mA    108.1mA
-1.033V   82.43mA    94.82mA    80.43mA
-1V       57.8mA     70.76mA    52.79mA
-900mV    15.24mA    26.27mA    9.219mA
-800mV    1.891mA    6.386mA    920.3uA
-700mV    413.8uA    830.5uA    493.8uA
-500mV    92.23uA    60.94uA    105uA
0V        9.09nA     33.61nA    36.58nA
[GND_clamp]
-3.3V     -1.792A    -1.668A    -2.631A
-1.033V   -45.54mA   -57.74mA   -50.28mA
-966.7mV  -22.82mA   -33.82mA   -24.04mA
-900mV    -8.514mA   -15.05mA   -7.265mA
-833.3mV  -3.815mA   -7.364mA   -3.174mA
-766.7mV  -1.156mA   -2.592mA   -954.7uA
-700mV    -537uA     -735.7uA   -606.1uA
-566.7mV  -224.7uA   -222.2uA   -244.9uA
-433.3mV  -72.81uA   -71.19uA   -81.46uA
3.233V    8.972nA    1.341uA    33.57nA
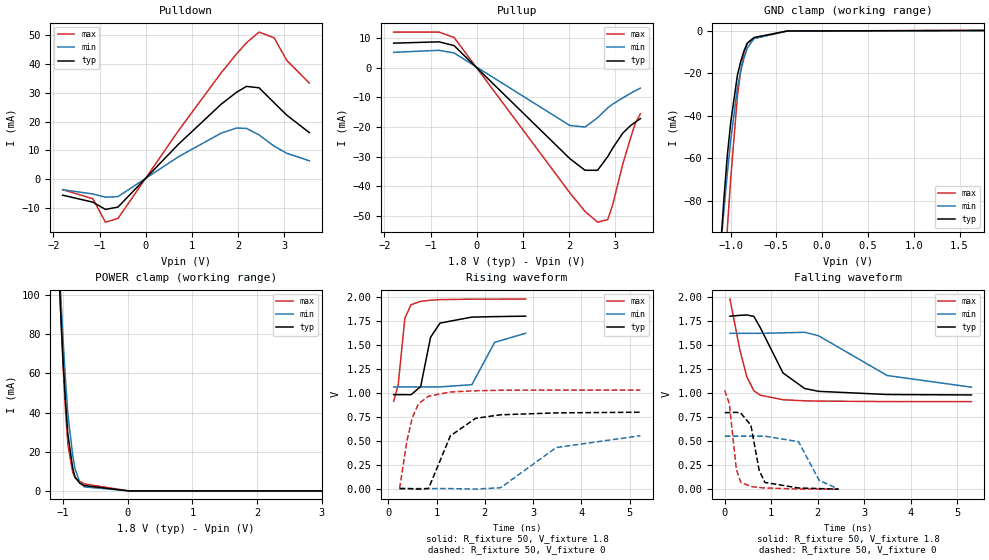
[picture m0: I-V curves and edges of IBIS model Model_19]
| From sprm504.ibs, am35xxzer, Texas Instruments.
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| Model based on original model for BC1833DV65ATPBFHP18LL_7LM_X50
|   Sub model LL_7LM_X50_PD_ON_1P8
[model]   Model_19
|[Description]  1.8V-I/O-PD-X
|[Input Load]   PD
|[Output Drive]
|Voltage   1.8V
|Mode   I/O
Model_type   I/O
Polarity   Non-Inverting
Enable   Active-Low
Vinl =  0.63V
Vinh =  1.17V
Cref =  15pF
Rref =  100.0000M
Vref =  0V
Vmeas =  0.9
C_comp   1.827006p   1.710031p   1.865433p
[Model Spec]
Vinl   0.63V   0.567V   0.693V
Vinh   1.17V   1.053V   1.287V
[Temperature Range]   25   125   -40
[Voltage Range]   1.8   1.62   1.98
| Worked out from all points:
|   slope of the pulldown table from 0 to 0.27 V, typ, clamps not added: 57.3 ohm
|   slope of the pullup table from 0 to 0.27 V, typ, clamps not added: 61.7 ohm
|   GND clamp passes 1 mA (typ) near -0.59 V on its own axis
|   POWER clamp passes 1 mA (typ) near -0.52 V on its own axis
|   rising waveform, R_fixture 50, V_fixture 1.8: 20-80 % time 203ps typ, 290ps min, 123ps max; typ from 0.978 V to 1.8 V
|   rising waveform, R_fixture 50, V_fixture 0: 20-80 % time 458ps typ, 982ps min, 253ps max; typ from 0 V to 0.795 V
|   falling waveform, R_fixture 50, V_fixture 1.8: 20-80 % time 560ps typ, 1.26ns min, 302ps max; typ from 1.8 V to 0.978 V
|   falling waveform, R_fixture 50, V_fixture 0: 20-80 % time 181ps typ, 310ps min, 129ps max; typ from 0.795 V to 0 V
[POWER_clamp]
-1.8V     828.7mA    859.8mA    895.4mA
-1.073V   117.4mA    126.7mA    121mA
-1.036V   88.92mA    98.94mA    88.92mA
-1V       65.26mA    75.98mA    62.42mA
-963.6mV  45.19mA    56.04mA    40.63mA
-927.3mV  28.71mA    39.11mA    23.56mA
-854.5mV  11.96mA    18.61mA    9.713mA
-818.2mV  7.105mA    11.44mA    6.771mA
-745.5mV  3.988mA    4.527mA    4.952mA
-672.7mV  2.733mA    2.057mA    3.594mA
18.18mV   0A         0A         0A
3.6V      0A         0A         0A
[Pulldown]
-1.8V     -5.591mA   -3.681mA   -3.662mA
-1.145V   -8.02mA    -5.175mA   -6.828mA
-872.7mV  -10.55mA   -6.29mA    -14.99mA
-600mV    -9.724mA   -6.096mA   -13.67mA
709.1mV   12.12mA    7.769mA    16.82mA
1.636V    26.06mA    15.99mA    36.98mA
1.964V    30.14mA    17.75mA    43.45mA
2.182V    32.24mA    17.64mA    47.38mA
2.455V    31.77mA    15.36mA    51.13mA
2.782V    26.55mA    11.48mA    49.14mA
3.055V    22.26mA    8.979mA    41.29mA
3.545V    16.16mA    6.369mA    33.41mA
[Pullup]
-1.8V     8.287mA    5.179mA    12.01mA
-818.2mV  8.728mA    5.865mA    12.02mA
-490.9mV  7.457mA    4.972mA    10.2mA
2.018V    -30.72mA   -19.53mA   -42.27mA
2.345V    -34.62mA   -20.02mA   -48.5mA
2.618V    -34.65mA   -16.89mA   -52.16mA
2.836V    -30.05mA   -13.59mA   -51.31mA
2.945V    -27.15mA   -12.31mA   -46.28mA
3.164V    -22.09mA   -10.2mA    -32.55mA
3.327V    -19.63mA   -8.709mA   -23.98mA
3.436V    -18.37mA   -7.753mA   -18.75mA
3.545V    -17.2mA    -6.896mA   -15.57mA
[GND_clamp]
-1.8V     -653mA     -527.8mA   -1.091A
-1.109V   -100.9mA   -102.8mA   -157.8mA
-1.073V   -78.76mA   -84.4mA    -123.2mA
-1.036V   -58.4mA    -66.86mA   -92.82mA
-1V       -43.42mA   -51.82mA   -70.01mA
-927.3mV  -21.11mA   -26.94mA   -31.27mA
-890.9mV  -14.59mA   -19.14mA   -19.01mA
-854.5mV  -9.501mA   -12.87mA   -10.51mA
-818.2mV  -5.834mA   -8.132mA   -5.79mA
-745.5mV  -3.149mA   -3.707mA   -3.552mA
-381.8mV  -85.66uA   -89.22uA   -105.6uA
1.764V    148.6uA    81.56uA    236.4uA
[Ramp]
dV/dt_f 0.49850096/0.5628751n 0.34180307/1.2673959n 0.64615525/0.30380535n
dV/dt_r 0.48297689/0.45724043n 0.33715479/0.98440855n 0.62031641/0.25319446n
R_load = 50
[Rising Waveform]
R_fixture = 50
V_fixture = 1.8
V_fixture_min = 1.62
V_fixture_max = 1.98
110.3ps   978.3mV    1.059V     909mV
203.4ps   978.3mV    1.059V     1.076V
342.4ps   978.2mV    1.059V     1.775V
470.5ps   977.7mV    1.059V     1.915V
669.6ps   1.062V     1.059V     1.95V
875.1ps   1.576V     1.059V     1.962V
1.072ns   1.724V     1.059V     1.968V
1.731ns   1.786V     1.082V     1.973V
2.203ns   1.791V     1.523V     1.973V
2.845ns   1.796V     1.618V     1.974V
[Rising Waveform]
R_fixture = 50
V_fixture = 0
V_fixture_min = 0
V_fixture_max = 0
233.8ps   9.286nV    77.19nV    11.95nV
383.6ps   -259.2uV   -769.6nV   492.5mV
494.5ps   -2.146mV   -665nV     735.1mV
624.4ps   -6.358mV   476.3nV    883.8mV
833.1ps   802.5uV    768.2nV    961.6mV
1.285ns   548.5mV    -62.02uV   1.006V
1.807ns   731.4mV    -5.455mV   1.019V
2.325ns   768.4mV    8.53mV     1.024V
3.48ns    788.2mV    427.3mV    1.026V
5.222ns   795.2mV    550.3mV    1.026V
[Falling Waveform]
R_fixture = 50
V_fixture = 1.8
V_fixture_min = 1.62
V_fixture_max = 1.98
113.4ps   1.796V     1.618V     1.974V
327.5ps   1.805V     1.618V     1.443V
475.7ps   1.809V     1.618V     1.167V
627.6ps   1.794V     1.618V     1.021V
767ps     1.675V     1.618V     975.7mV
1.252ns   1.207V     1.623V     928.6mV
1.718ns   1.045V     1.629V     917.5mV
2.016ns   1.016V     1.593V     914.5mV
3.492ns   983mV      1.18V      909.4mV
5.301ns   978.3mV    1.059V     909mV
[Falling Waveform]
R_fixture = 50
V_fixture = 0
V_fixture_min = 0
V_fixture_max = 0
0s        795.2mV    550.3mV    1.026V
99.93ps   795.4mV    550.3mV    886.5mV
250.5ps   797.5mV    550.3mV    205.6mV
342.7ps   791mV      550.3mV    71.65mV
562.2ps   665.9mV    550.3mV    27.58mV
739.7ps   197.3mV    550.2mV    16.79mV
863.4ps   69.81mV    550.2mV    12.61mV
1.586ns   12.17mV    493.4mV    1.718mV
2.03ns    6.231mV    91.45mV    492.9uV
2.448ns   9.286nV    77.19nV    11.95nV
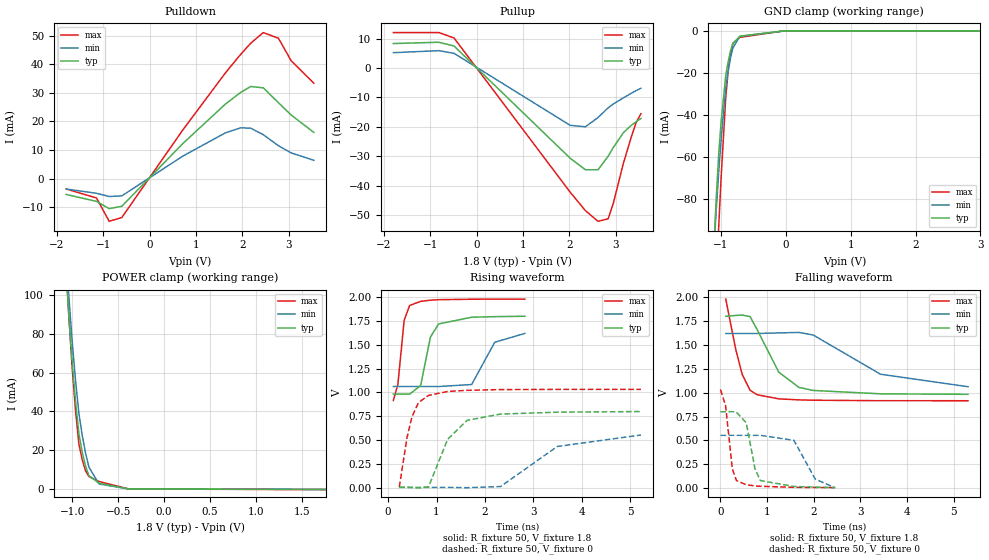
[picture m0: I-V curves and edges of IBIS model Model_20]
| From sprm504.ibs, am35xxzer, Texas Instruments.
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| Model based on original model for BC1833DV65ATPBFHP18LL_7LM_X50
|   Sub model LL_7LM_X50_PU_ON_1P8
[model]   Model_20
|[Description]  1.8V-I/O-PU-X
|[Input Load]   PU
|[Output Drive]
|Voltage   1.8V
|Mode   I/O
Model_type   I/O
Polarity   Non-Inverting
Enable   Active-Low
Vinl =  0.63V
Vinh =  1.17V
Cref =  15pF
Rref =  100.0000M
Vref =  0V
Vmeas =  0.9
C_comp   1.827006p   1.710031p   1.865433p
[Model Spec]
Vinl   0.63V   0.567V   0.693V
Vinh   1.17V   1.053V   1.287V
[Temperature Range]   25   125   -40
[Voltage Range]   1.8   1.62   1.98
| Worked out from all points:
|   slope of the pulldown table from 0 to 0.27 V, typ, clamps not added: 57.3 ohm
|   slope of the pullup table from 0 to 0.27 V, typ, clamps not added: 61.7 ohm
|   GND clamp passes 1 mA (typ) near -0.57 V on its own axis
|   POWER clamp passes 1 mA (typ) near -0.54 V on its own axis
|   rising waveform, R_fixture 50, V_fixture 1.8: 20-80 % time 201ps typ, 289ps min, 122ps max; typ from 0.983 V to 1.8 V
|   rising waveform, R_fixture 50, V_fixture 0: 20-80 % time 459ps typ, 986ps min, 252ps max; typ from 0.004 V to 0.799 V
|   falling waveform, R_fixture 50, V_fixture 1.8: 20-80 % time 561ps typ, 1.26ns min, 303ps max; typ from 1.8 V to 0.983 V
|   falling waveform, R_fixture 50, V_fixture 0: 20-80 % time 182ps typ, 311ps min, 129ps max; typ from 0.799 V to 0.004 V
[POWER_clamp]
-1.8V     828.5mA    859.7mA    895.2mA
-1.073V   117.3mA    126.6mA    120.8mA
-1.036V   88.78mA    98.87mA    88.68mA
-1V       65.12mA    75.91mA    62.17mA
-963.6mV  45.05mA    55.96mA    40.38mA
-927.3mV  28.56mA    39.03mA    23.3mA
-890.9mV  19.01mA    27.76mA    15.05mA
-854.5mV  11.81mA    18.53mA    9.448mA
-818.2mV  6.953mA    11.37mA    6.504mA
-709.1mV  3.098mA    2.696mA    3.982mA
-381.8mV  87.97uA    68.36uA    88.99uA
1.764V    -143.5uA   -80.05uA   -225.9uA
[Pulldown]
-1.8V     -5.591mA   -3.681mA   -3.662mA
-1.145V   -8.02mA    -5.175mA   -6.828mA
-872.7mV  -10.55mA   -6.291mA   -14.99mA
-600mV    -9.724mA   -6.096mA   -13.67mA
709.1mV   12.12mA    7.769mA    16.82mA
1.636V    26.06mA    15.99mA    36.98mA
1.964V    30.14mA    17.75mA    43.45mA
2.182V    32.24mA    17.64mA    47.38mA
2.455V    31.77mA    15.36mA    51.13mA
2.782V    26.55mA    11.48mA    49.14mA
3.055V    22.26mA    8.979mA    41.29mA
3.545V    16.16mA    6.369mA    33.41mA
[Pullup]
-1.8V     8.287mA    5.179mA    12.01mA
-818.2mV  8.728mA    5.865mA    12.02mA
-490.9mV  7.457mA    4.972mA    10.2mA
2.018V    -30.72mA   -19.53mA   -42.27mA
2.345V    -34.62mA   -20.02mA   -48.5mA
2.618V    -34.65mA   -16.89mA   -52.16mA
2.836V    -30.05mA   -13.59mA   -51.32mA
2.945V    -27.15mA   -12.31mA   -46.28mA
3.164V    -22.09mA   -10.2mA    -32.55mA
3.327V    -19.63mA   -8.709mA   -23.98mA
3.436V    -18.37mA   -7.753mA   -18.75mA
3.545V    -17.2mA    -6.896mA   -15.57mA
[GND_clamp]
-1.8V     -653mA     -527.8mA   -1.091A
-1.109V   -101mA     -102.8mA   -157.9mA
-1.073V   -78.84mA   -84.44mA   -123.3mA
-1.036V   -58.49mA   -66.9mA    -92.93mA
-1V       -43.52mA   -51.87mA   -70.14mA
-927.3mV  -21.22mA   -26.99mA   -31.46mA
-890.9mV  -14.72mA   -19.19mA   -19.23mA
-854.5mV  -9.634mA   -12.93mA   -10.75mA
-818.2mV  -5.973mA   -8.196mA   -6.035mA
-709.1mV  -2.583mA   -2.575mA   -3.081mA
-18.18mV  0A         0A         0A
3.6V      0A         0A         0A
[Ramp]
dV/dt_f 0.49878411/0.56372952n 0.34194937/1.2687198n 0.64649691/0.30470616n
dV/dt_r 0.48282216/0.45653049n 0.33686185/0.98357n   0.62050877/0.25251376n
R_load = 50
[Rising Waveform]
R_fixture = 50
V_fixture = 1.8
V_fixture_min = 1.62
V_fixture_max = 1.98
109.2ps   982.5mV    1.062V     915.1mV
202.9ps   982.5mV    1.062V     1.084V
332.6ps   982.4mV    1.062V     1.758V
445.5ps   982.2mV    1.062V     1.913V
673ps     1.072V     1.062V     1.957V
874.5ps   1.582V     1.062V     1.969V
1.043ns   1.719V     1.062V     1.974V
1.725ns   1.79V      1.083V     1.979V
2.202ns   1.796V     1.527V     1.98V
2.824ns   1.8V       1.62V      1.98V
[Rising Waveform]
R_fixture = 50
V_fixture = 0
V_fixture_min = 0
V_fixture_max = 0
232.3ps   3.88mV     2.308mV    5.718mV
391.4ps   3.602mV    2.308mV    525.4mV
490.9ps   2.007mV    2.308mV    738.7mV
626.8ps   -2.413mV   2.309mV    893.2mV
836.8ps   8.124mV    2.309mV    969.1mV
1.23ns    507.7mV    2.313mV    1.01V
1.63ns    706.6mV    -613.5uV   1.022V
2.32ns    772.5mV    10.97mV    1.03V
3.492ns   792.5mV    432.3mV    1.032V
5.218ns   799.3mV    552.8mV    1.032V
[Falling Waveform]
R_fixture = 50
V_fixture = 1.8
V_fixture_min = 1.62
V_fixture_max = 1.98
114.5ps   1.8V       1.62V      1.98V
325.9ps   1.809V     1.62V      1.456V
465.3ps   1.813V     1.62V      1.192V
633.8ps   1.797V     1.62V      1.025V
786.6ps   1.66V      1.62V      978.3mV
1.248ns   1.215V     1.626V     934.9mV
1.681ns   1.055V     1.631V     924.1mV
1.987ns   1.023V     1.604V     920.8mV
3.43ns    987.6mV    1.193V     915.6mV
5.305ns   982.5mV    1.062V     915.1mV
[Falling Waveform]
R_fixture = 50
V_fixture = 0
V_fixture_min = 0
V_fixture_max = 0
0s        799.3mV    552.8mV    1.032V
110.5ps   799.7mV    552.7mV    863.2mV
252.8ps   801.7mV    552.8mV    205mV
342.1ps   795.2mV    552.8mV    78.66mV
552.5ps   683.9mV    552.8mV    34.64mV
739.7ps   202.4mV    552.7mV    22.76mV
853.6ps   79.16mV    552.6mV    18.87mV
1.574ns   16.44mV    500.2mV    7.545mV
2.03ns    10.19mV    94.14mV    6.226mV
2.459ns   3.88mV     2.308mV    5.718mV
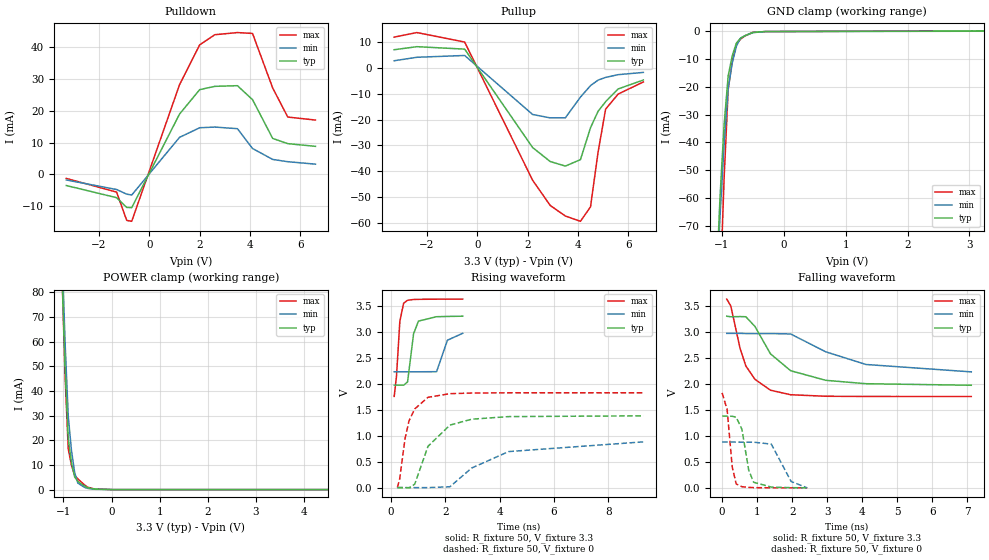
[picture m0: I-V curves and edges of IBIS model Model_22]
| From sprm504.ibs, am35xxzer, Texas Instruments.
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| Model based on original model for BC1833DV65ATPBFHP18LL_7LM_X50
|   Sub model LL_7LM_X50_PD_ON_3P3
[model]   Model_22
|[Description]  3.3V-I/O-PD-X
|[Input Load]   PD
|[Output Drive]
|Voltage   3.3V
|Mode   I/O
Model_type   I/O
Polarity   Non-Inverting
Enable   Active-Low
Vinl =  0.8V
Vinh =  2V
Cref =  15pF
Rref =  100.0000M
Vref =  0V
Vmeas =  1.65
C_comp   1.569055p   1.388637p   1.6677p
[Model Spec]
Vinl   0.8V   0.8V   0.8V
Vinh   2V   2V   2V
[Temperature Range]   25   125   -40
[Voltage Range]   3.3   2.97   3.63
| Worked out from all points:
|   slope of the pulldown table from 0 to 0.495 V, typ, clamps not added: 57.2 ohm
|   slope of the pullup table from 0 to 0.495 V, typ, clamps not added: 64.6 ohm
|   GND clamp passes 1 mA (typ) near -0.58 V on its own axis
|   POWER clamp passes 1 mA (typ) near -0.52 V on its own axis
|   rising waveform, R_fixture 50, V_fixture 3.3: 20-80 % time 189ps typ, 268ps min, 136ps max; typ from 1.97 V to 3.3 V
|   rising waveform, R_fixture 50, V_fixture 0: 20-80 % time 838ps typ, 1.94ns min, 447ps max; typ from 0 V to 1.38 V
|   falling waveform, R_fixture 50, V_fixture 3.3: 20-80 % time 1.01ns typ, 1.63ns min, 549ps max; typ from 3.3 V to 1.97 V
|   falling waveform, R_fixture 50, V_fixture 0: 20-80 % time 210ps typ, 356ps min, 143ps max; typ from 1.38 V to 0 V
[POWER_clamp]
-3.3V     2.404A     2.849A     2.585A
-1.033V   89.34mA    99.38mA    89.48mA
-966.7mV  49.8mA     59.97mA    46.42mA
-900mV    20.7mA     29.79mA    16.49mA
-833.3mV  10.96mA    15.96mA    9.834mA
-766.7mV  5.165mA    6.911mA    5.776mA
-700mV    3.308mA    2.637mA    4.316mA
-566.7mV  1.546mA    972.7uA    1.992mA
-500mV    812.1uA    501uA      1.003mA
-366.7mV  231.9uA    144.3uA    326.1uA
33.33mV   0A         0A         0A
6.6V      0A         0A         0A
[Pulldown]
-3.3V     -3.482mA   -1.731mA   -1.253mA
-1.3V     -7.299mA   -4.736mA   -5.547mA
-900mV    -10.35mA   -6.182mA   -14.42mA
-700mV    -10.42mA   -6.462mA   -14.71mA
1.2V      18.95mA    11.64mA    28.17mA
2V        26.61mA    14.65mA    40.67mA
2.6V      27.65mA    14.87mA    43.85mA
3.5V      27.86mA    14.36mA    44.53mA
4.1V      23.47mA    8.142mA    44.25mA
4.9V      11.31mA    4.711mA    27.15mA
5.5V      9.66mA     3.997mA    18.01mA
6.6V      8.818mA    3.224mA    17.07mA
[Pullup]
-3.3V     7.018mA    2.752mA    11.89mA
-2.4V     8.195mA    4.095mA    13.65mA
-500mV    7.249mA    4.793mA    9.977mA
2.2V      -30.8mA    -18.02mA   -43.45mA
2.9V      -36.22mA   -19.34mA   -53.21mA
3.5V      -37.97mA   -19.31mA   -57.28mA
4.1V      -35.47mA   -11.3mA    -59.32mA
4.5V      -23.14mA   -6.857mA   -53.72mA
4.8V      -16.8mA    -4.734mA   -32.6mA
5.1V      -13.06mA   -3.688mA   -15.95mA
5.6V      -8.137mA   -2.623mA   -10.11mA
6.6V      -4.691mA   -1.758mA   -5.452mA
[GND_clamp]
-3.3V     -1.939A    -1.746A    -3.236A
-1.1V     -94.77mA   -97.88mA   -147.5mA
-1.033V   -60.01mA   -66.87mA   -95.36mA
-966.7mV  -33.72mA   -41.08mA   -53.17mA
-900mV    -15.9mA    -20.5mA    -20.91mA
-833.3mV  -8.658mA   -11.27mA   -10.44mA
-766.7mV  -4.174mA   -5.247mA   -4.392mA
-700mV    -2.445mA   -2.425mA   -2.775mA
-633.3mV  -1.568mA   -1.559mA   -1.676mA
-500mV    -339.1uA   -424.8uA   -287.6uA
-300mV    -30.04uA   -29.18uA   -39.62uA
3.233V    152.3uA    91.33uA    242.6uA
[Ramp]
dV/dt_f 0.79541166/1.0077556n 0.44413592/1.6271188n  1.1218162/0.54896758n
dV/dt_r 0.83081922/0.83795641n 0.53041395/1.9035447n  1.0971579/0.44671466n
R_load = 50
[Rising Waveform]
R_fixture = 50
V_fixture = 3.3
V_fixture_min = 2.97
V_fixture_max = 3.63
124.7ps   1.97V      2.227V     1.754V
209.3ps   1.97V      2.227V     2.142V
332.2ps   1.97V      2.227V     3.198V
471.5ps   1.969V     2.227V     3.546V
616.2ps   2.032V     2.227V     3.602V
837.2ps   2.958V     2.227V     3.617V
1.015ns   3.201V     2.227V     3.62V
1.683ns   3.286V     2.229V     3.623V
2.081ns   3.291V     2.834V     3.623V
2.644ns   3.296V     2.967V     3.624V
[Rising Waveform]
R_fixture = 50
V_fixture = 0
V_fixture_min = 0
V_fixture_max = 0
240.3ps   7.736nV    99.21nV    4.197nV
323ps     -8.312nV   -67.58nV   155.5mV
521.2ps   -1.362mV   19.35nV    936.9mV
671ps     -5.124mV   2.746nV    1.286V
879.6ps   66.19mV    149nV      1.512V
1.366ns   793.3mV    -101.9uV   1.736V
2.172ns   1.201V     15.5mV     1.806V
2.97ns    1.315V     375.7mV    1.818V
4.329ns   1.365V     692.3mV    1.823V
9.284ns   1.38V      879.4mV    1.823V
[Falling Waveform]
R_fixture = 50
V_fixture = 3.3
V_fixture_min = 2.97
V_fixture_max = 3.63
132.7ps   3.296V     2.967V     3.624V
246.9ps   3.285V     2.967V     3.495V
515ps     3.289V     2.967V     2.672V
676.6ps   3.286V     2.963V     2.341V
937.1ps   3.099V     2.961V     2.084V
1.381ns   2.573V     2.963V     1.875V
1.955ns   2.25V      2.955V     1.788V
2.956ns   2.065V     2.613V     1.759V
4.106ns   2V         2.369V     1.755V
7.113ns   1.97V      2.227V     1.754V
[Falling Waveform]
R_fixture = 50
V_fixture = 0
V_fixture_min = 0
V_fixture_max = 0
0s        1.38V      879.4mV    1.823V
142.8ps   1.376V     879.4mV    1.506V
288.9ps   1.375V     879.4mV    399.1mV
403.5ps   1.356V     879mV      73.53mV
565.8ps   1.123V     878.2mV    22.47mV
758.9ps   340.9mV    877.5mV    9.606mV
898ps     108.2mV    877.5mV    4.724mV
1.405ns   14.52mV    839.5mV    370.2uV
1.97ns    3.817mV    122.6mV    32.24uV
2.43ns    7.736nV    99.21nV    4.197nV
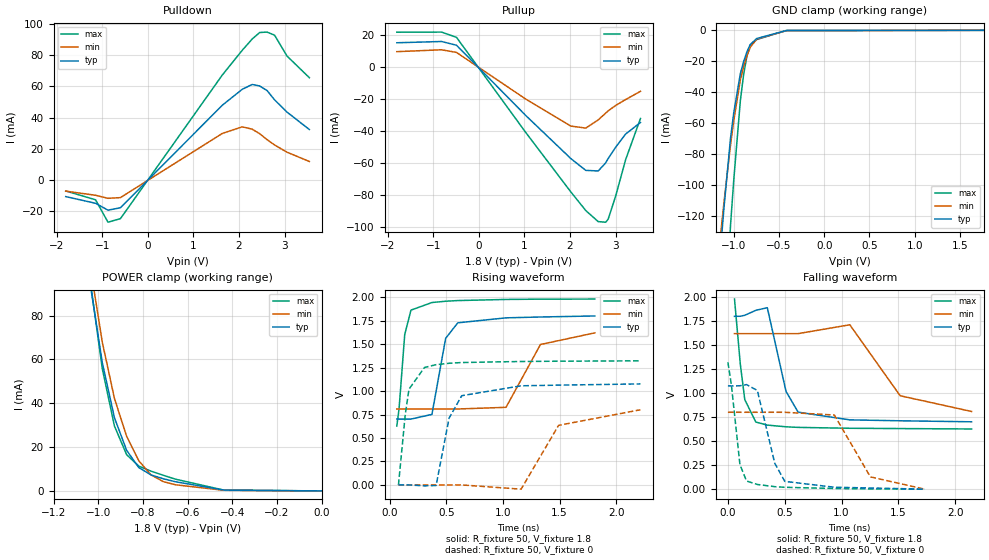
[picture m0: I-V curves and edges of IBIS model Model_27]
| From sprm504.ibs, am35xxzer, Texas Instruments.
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| Model based on original model for BQ1833DV40DTPBFHP18LL_7LM
|   Sub model LL_7LM_PD_PU_OFF_1P8
[model]   Model_27
|[Description]  1.8V-I/O-PI-X
|[Input Load]   PI
|[Output Drive]
|Voltage   1.8V
|Mode   I/O
Model_type   I/O
Polarity   Non-Inverting
Enable   Active-Low
Vinl =  0.63V
Vinh =  1.17V
Cref =  15pF
Rref =  100.0000M
Vref =  0V
Vmeas =  0.9
C_comp   2.161439p   2.02467p   2.204523p
[Model Spec]
Vinl   0.63V   0.567V   0.693V
Vinh   1.17V   1.053V   1.287V
[Temperature Range]   25   125   -40
[Voltage Range]   1.8   1.62   1.98
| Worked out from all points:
|   slope of the pulldown table from 0 to 0.27 V, typ, clamps not added: 31.5 ohm
|   slope of the pullup table from 0 to 0.27 V, typ, clamps not added: 33.5 ohm
|   GND clamp passes 1 mA (typ) near -0.54 V on its own axis
|   POWER clamp passes 1 mA (typ) near -0.49 V on its own axis
|   rising waveform, R_fixture 50, V_fixture 1.8: 20-80 % time 93.9ps typ, 189ps min, 56.7ps max; typ from 0.702 V to 1.8 V
|   rising waveform, R_fixture 50, V_fixture 0: 20-80 % time 124ps typ, 245ps min, 76ps max; typ from 0 V to 1.08 V
|   falling waveform, R_fixture 50, V_fixture 1.8: 20-80 % time 133ps typ, 278ps min, 76ps max; typ from 1.8 V to 0.702 V
|   falling waveform, R_fixture 50, V_fixture 0: 20-80 % time 136ps typ, 206ps min, 71.4ps max; typ from 1.08 V to 0 V
[POWER_clamp]
-1.8V     842.2mA    869.1mA    912.5mA
-1.055V   109mA      116.8mA    112.5mA
-1.036V   94.63mA    102.8mA    96.22mA
-981.8mV  58.65mA    67.99mA    55.86mA
-927.3mV  33.42mA    42.23mA    29.64mA
-872.7mV  18.54mA    24.92mA    16.54mA
-818.2mV  10.66mA    13.77mA    11.33mA
-763.6mV  7.291mA    7.319mA    9.029mA
-709.1mV  5.568mA    4.279mA    7.154mA
-654.5mV  4.197mA    2.818mA    5.381mA
-436.4mV  381.9uA    275.7uA    348.1uA
0V        17.81nA    62.52nA    29.22nA
[Pulldown]
-1.8V     -10.48mA   -6.986mA   -6.871mA
-1.145V   -14.76mA   -9.635mA   -12.53mA
-872.7mV  -19.16mA   -11.57mA   -26.86mA
-600mV    -17.63mA   -11.14mA   -24.6mA
1.636V    48.02mA    29.94mA    67.34mA
2.073V    58.19mA    34.17mA    83.16mA
2.291V    61.26mA    32.65mA    90.37mA
2.455V    60.31mA    29.78mA    94.52mA
2.618V    57.35mA    25.94mA    94.79mA
2.782V    51.42mA    22.55mA    92.8mA
3.055V    43.58mA    17.93mA    79.45mA
3.545V    32.44mA    11.99mA    65.6mA
[Pullup]
-1.8V     15.25mA    9.689mA    21.84mA
-818.2mV  16.04mA    10.87mA    21.92mA
-490.9mV  13.71mA    9.212mA    18.64mA
1.036V    -30.4mA    -20.07mA   -41.09mA
2.018V    -57.11mA   -36.81mA   -77.94mA
2.345V    -64.48mA   -38.06mA   -89.56mA
2.618V    -64.84mA   -32.95mA   -96.49mA
2.782V    -59.78mA   -28.7mA    -96.85mA
2.836V    -57.13mA   -27.34mA   -95.02mA
3V        -50.06mA   -23.92mA   -80.63mA
3.218V    -41.82mA   -20.26mA   -57.92mA
3.545V    -34.58mA   -15.09mA   -32.06mA
[GND_clamp]
-1.8V     -697.8mA   -553.2mA   -1.259A
-1.145V   -140.6mA   -131.7mA   -248.3mA
-1.109V   -115.1mA   -111.6mA   -203.3mA
-1.036V   -69.6mA    -74.07mA   -125.9mA
-1V       -53.16mA   -58.25mA   -96.51mA
-927.3mV  -27.95mA   -31.85mA   -45.33mA
-890.9mV  -20.12mA   -23.33mA   -28.4mA
-854.5mV  -13.86mA   -16.38mA   -16.49mA
-818.2mV  -9.165mA   -11mA      -9.583mA
-745.5mV  -5.275mA   -5.606mA   -5.955mA
-418.2mV  -132.4uA   -214.4uA   -105.2uA
1.764V    17.27nA    517.3nA    24.83nA
[Ramp]
dV/dt_f 0.74571444/0.14078422n 0.55179683/0.29408493n 0.90696097/80.24386p
dV/dt_r 0.66865991/0.12455512n 0.51025928/0.24456904n 0.81155664/76.397211p
R_load = 50
[Rising Waveform]
R_fixture = 50
V_fixture = 1.8
V_fixture_min = 1.62
V_fixture_max = 1.98
62.7ps    701.7mV    809.2mV    626.9mV
82.27ps   701.7mV    809.2mV    807.8mV
132.6ps   701.7mV    809.2mV    1.602V
187.6ps   701.5mV    809.2mV    1.862V
372.6ps   751mV      809.2mV    1.943V
494ps     1.562V     809.2mV    1.957V
601.2ps   1.727V     809mV      1.964V
1.027ns   1.78V      826.8mV    1.976V
1.331ns   1.789V     1.496V     1.979V
1.811ns   1.8V       1.62V      1.98V
[Rising Waveform]
R_fixture = 50
V_fixture = 0
V_fixture_min = 0
V_fixture_max = 0
77.29ps   9.701nV    106.6nV    8.922nV
137.2ps   40.4uV     1.543uV    749.4mV
170.1ps   29.92uV    1.736uV    1.02V
306.7ps   -9.815mV   2.282uV    1.251V
409.6ps   -6.125mV   -10.11uV   1.281V
524.3ps   712.3mV    -12.86uV   1.296V
636.1ps   950.7mV    28.58uV    1.304V
1.16ns    1.056V     -45.13mV   1.315V
1.491ns   1.063V     634.5mV    1.318V
2.214ns   1.076V     800.9mV    1.322V
[Falling Waveform]
R_fixture = 50
V_fixture = 1.8
V_fixture_min = 1.62
V_fixture_max = 1.98
57.95ps   1.8V       1.62V      1.98V
109.3ps   1.801V     1.62V      1.298V
148.5ps   1.811V     1.62V      931.6mV
245.9ps   1.863V     1.62V      698.8mV
346.6ps   1.89V      1.62V      667.4mV
511.1ps   1.018V     1.62V      649.4mV
617.6ps   801.9mV    1.62V      643.5mV
1.072ns   721.7mV    1.712V     634.3mV
1.515ns   712.2mV    973.1mV    631.2mV
2.143ns   701.7mV    809.2mV    626.9mV
[Falling Waveform]
R_fixture = 50
V_fixture = 0
V_fixture_min = 0
V_fixture_max = 0
0s        1.076V     800.9mV    1.322V
29.67ps   1.075V     800.9mV    1.094V
105.7ps   1.077V     800.9mV    255mV
163.6ps   1.089V     800.9mV    85.22mV
258.9ps   1.028V     800.9mV    48.83mV
411.9ps   270.2mV    800.9mV    26.04mV
500.2ps   81.11mV    800.6mV    19.56mV
935.9ps   20mV       772.4mV    6.792mV
1.253ns   12.23mV    127.9mV    2.799mV
1.732ns   9.701nV    106.6nV    8.922nV
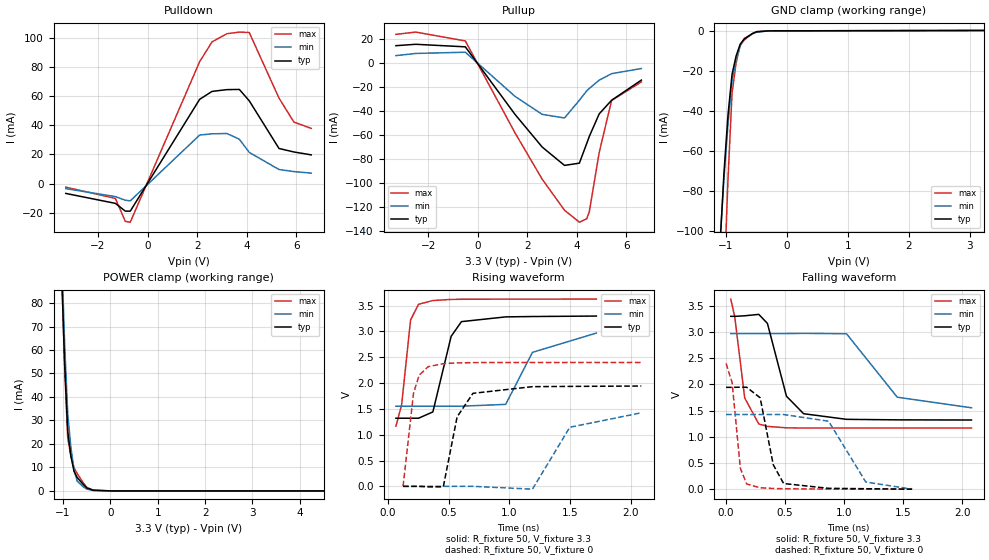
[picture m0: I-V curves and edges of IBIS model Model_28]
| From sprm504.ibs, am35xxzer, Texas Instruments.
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| Model based on original model for BQ1833DV40DTPBFHP18LL_7LM
|   Sub model HP18LL_7LM_PD_ON_3P3
[model]   Model_28
|[Description]  3.3V-I/O-PD-X
|[Input Load]   PD
|[Output Drive]
|Voltage   3.3V
|Mode   I/O
Model_type   I/O
Polarity   Non-Inverting
Enable   Active-Low
Vinl =  0.8V
Vinh =  2V
Cref =  15pF
Rref =  100.0000M
Vref =  0V
Vmeas =  1.65
C_comp   1.861386p   1.655853p   1.968812p
[Model Spec]
Vinl   0.8V   0.8V   0.8V
Vinh   2V   2V   2V
[Temperature Range]   25   125   -40
[Voltage Range]   3.3   2.97   3.63
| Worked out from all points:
|   slope of the pulldown table from 0 to 0.495 V, typ, clamps not added: 31.5 ohm
|   slope of the pullup table from 0 to 0.495 V, typ, clamps not added: 34.2 ohm
|   GND clamp passes 1 mA (typ) near -0.54 V on its own axis
|   POWER clamp passes 1 mA (typ) near -0.47 V on its own axis
|   rising waveform, R_fixture 50, V_fixture 3.3: 20-80 % time 118ps typ, 207ps min, 63.2ps max; typ from 1.32 V to 3.3 V
|   rising waveform, R_fixture 50, V_fixture 0: 20-80 % time 111ps typ, 205ps min, 72ps max; typ from 0 V to 1.94 V
|   falling waveform, R_fixture 50, V_fixture 3.3: 20-80 % time 146ps typ, 269ps min, 84.5ps max; typ from 3.3 V to 1.32 V
|   falling waveform, R_fixture 50, V_fixture 0: 20-80 % time 99.1ps typ, 181ps min, 58.1ps max; typ from 1.94 V to 0 V
[POWER_clamp]
-3.3V     2.432A     2.868A     2.62A
-1.033V   95.16mA    103.3mA    97mA
-966.7mV  55mA       63.41mA    53.17mA
-900mV    25.28mA    32.79mA    22.49mA
-833.3mV  14.83mA    18.47mA    14.88mA
-766.7mV  8.299mA    8.929mA    9.847mA
-700mV    5.694mA    4.162mA    7.387mA
-566.7mV  2.611mA    1.646mA    3.301mA
-500mV    1.319mA    827.8uA    1.568mA
-366.7mV  287.8uA    192.2uA    368.8uA
33.33mV   0A         0A         0A
6.6V      0A         0A         0A
[Pulldown]
-3.3V     -6.746mA   -3.451mA   -2.449mA
-1.3V     -13.56mA   -8.907mA   -10.16mA
-900mV    -18.87mA   -11.41mA   -25.91mA
-700mV    -18.91mA   -11.83mA   -26.47mA
2.1V      57.81mA    33.29mA    83.64mA
2.6V      63.23mA    34.14mA    97.21mA
3.2V      64.44mA    34.35mA    102.8mA
3.7V      64.57mA    30.45mA    103.9mA
4.1V      56.78mA    21.39mA    103.6mA
5.3V      24.08mA    9.65mA     58.63mA
5.9V      21.68mA    8.241mA    42.2mA
6.6V      19.7mA     7.18mA     37.87mA
[Pullup]
-3.3V     14.58mA    6.278mA    24.04mA
-2.5V     15.74mA    8.096mA    25.94mA
-500mV    13.62mA    9.123mA    18.54mA
1.5V      -42.71mA   -27.72mA   -58.1mA
2.6V      -70.12mA   -42.82mA   -96.98mA
3.5V      -85.45mA   -45.81mA   -122.9mA
4.1V      -83.57mA   -31.01mA   -132.9mA
4.4V      -66.93mA   -23.06mA   -130mA
4.5V      -61.28mA   -21.14mA   -124.2mA
4.9V      -42.37mA   -14.19mA   -74.57mA
5.4V      -31.02mA   -8.795mA   -31.2mA
6.6V      -14.18mA   -4.519mA   -15.68mA
[GND_clamp]
-3.3V     -2.048A    -1.805A    -3.667A
-1.1V     -108.6mA   -106.5mA   -191.4mA
-1.033V   -71.11mA   -74.03mA   -127.7mA
-966.7mV  -42.17mA   -46.82mA   -74.25mA
-900mV    -21.74mA   -24.87mA   -31.11mA
-833.3mV  -12.59mA   -14.47mA   -16.1mA
-766.7mV  -6.71mA    -7.469mA   -7.269mA
-700mV    -4.089mA   -3.883mA   -4.623mA
-566.7mV  -1.428mA   -1.487mA   -1.361mA
-500mV    -525.6uA   -699.5uA   -401.5uA
-300mV    -31.04uA   -34.98uA   -39.83uA
3.233V    152.3uA    97.64uA    242.6uA
[Ramp]
dV/dt_f  1.2090019/0.14581559n 0.87094722/0.27134282n  1.4948479/84.997072p
dV/dt_r  1.2007155/0.11086239n 0.89238382/0.20721418n  1.4643598/72.257884p
R_load = 50
[Rising Waveform]
R_fixture = 50
V_fixture = 3.3
V_fixture_min = 2.97
V_fixture_max = 3.63
64.19ps   1.319V     1.552V     1.166V
110.9ps   1.319V     1.552V     1.573V
185ps     1.319V     1.552V     3.221V
250.7ps   1.319V     1.552V     3.525V
368.9ps   1.441V     1.552V     3.598V
519.6ps   2.905V     1.552V     3.619V
604.5ps   3.189V     1.552V     3.622V
969.3ps   3.281V     1.587V     3.625V
1.19ns    3.288V     2.594V     3.625V
1.717ns   3.297V     2.968V     3.626V
[Rising Waveform]
R_fixture = 50
V_fixture = 0
V_fixture_min = 0
V_fixture_max = 0
123.2ps   8.381nV    117.4nV    4.085nV
209.3ps   157.1uV    1.808uV    1.802V
255.2ps   -282.2uV   2.117uV    2.15V
330.4ps   -9.932mV   2.467uV    2.317V
454.9ps   -8.408mV   -7.058uV   2.376V
568.8ps   1.345V     25.29uV    2.39V
699.4ps   1.801V     152.3uV    2.396V
1.19ns    1.93V      -54.64mV   2.399V
1.498ns   1.935V     1.144V     2.399V
2.088ns   1.942V     1.424V     2.399V
[Falling Waveform]
R_fixture = 50
V_fixture = 3.3
V_fixture_min = 2.97
V_fixture_max = 3.63
40.01ps   3.297V     2.968V     3.626V
73.24ps   3.296V     2.968V     3.294V
157.9ps   3.307V     2.968V     1.739V
276.8ps   3.334V     2.968V     1.244V
349.9ps   3.162V     2.968V     1.197V
511ps     1.773V     2.968V     1.17V
656.2ps   1.439V     2.972V     1.166V
1.019ns   1.332V     2.964V     1.167V
1.448ns   1.322V     1.754V     1.166V
2.076ns   1.319V     1.552V     1.166V
[Falling Waveform]
R_fixture = 50
V_fixture = 0
V_fixture_min = 0
V_fixture_max = 0
0s        1.942V     1.424V     2.399V
50.95ps   1.942V     1.424V     2.035V
121.2ps   1.945V     1.424V     396.5mV
174.3ps   1.944V     1.424V     99.23mV
288.4ps   1.743V     1.424V     27.09mV
399.4ps   464.8mV    1.424V     12.83mV
487ps     107.6mV    1.424V     8.433mV
867.7ps   15.99mV    1.296V     1.39mV
1.182ns   8.507mV    136.1mV    238.3uV
1.574ns   8.381nV    117.4nV    4.085nV
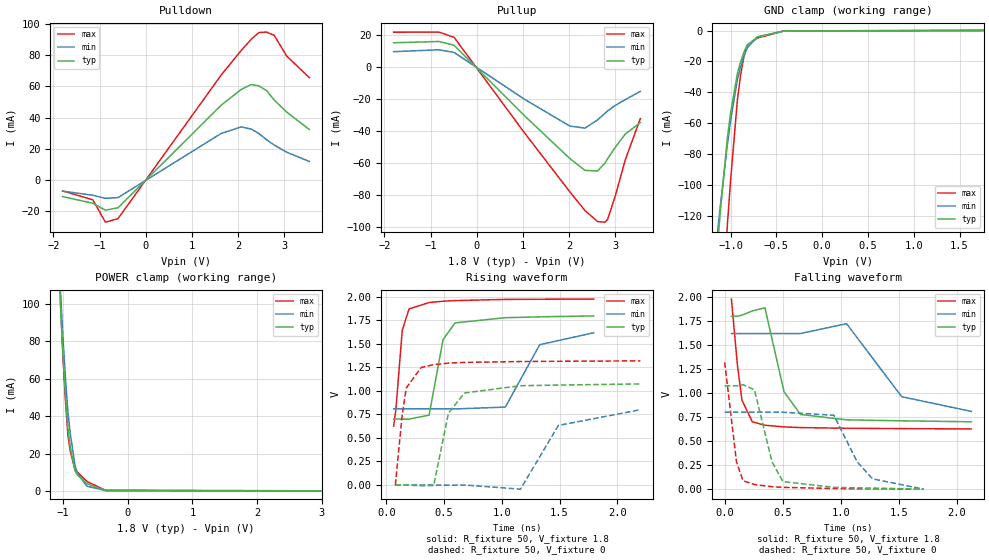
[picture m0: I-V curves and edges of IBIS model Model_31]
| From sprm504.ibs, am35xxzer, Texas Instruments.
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| Model based on original model for BQ1833DV40DTPBFZP18LL_7LM
|   Sub model ZP18LL_7LM_PD_ON_1P8
[model]   Model_31
|[Description]  1.8V-I/O-PD-X
|[Input Load]   PD
|[Output Drive]
|Voltage   1.8V
|Mode   I/O
Model_type   I/O
Polarity   Non-Inverting
Enable   Active-Low
Vinl =  0.63V
Vinh =  1.17V
Cref =  15pF
Rref =  100.0000M
Vref =  0V
Vmeas =  0.9
C_comp   2.161439p   2.02467p   2.204523p
[Model Spec]
Vinl   0.63V   0.567V   0.693V
Vinh   1.17V   1.053V   1.287V
[Temperature Range]   25   125   -40
[Voltage Range]   1.8   1.62   1.98
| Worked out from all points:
|   slope of the pulldown table from 0 to 0.27 V, typ, clamps not added: 31.5 ohm
|   slope of the pullup table from 0 to 0.27 V, typ, clamps not added: 33.5 ohm
|   GND clamp passes 1 mA (typ) near -0.54 V on its own axis
|   POWER clamp passes 1 mA (typ) near -0.48 V on its own axis
|   rising waveform, R_fixture 50, V_fixture 1.8: 20-80 % time 93.6ps typ, 189ps min, 56.4ps max; typ from 0.701 V to 1.8 V
|   rising waveform, R_fixture 50, V_fixture 0: 20-80 % time 123ps typ, 244ps min, 75.6ps max; typ from 0 V to 1.07 V
|   falling waveform, R_fixture 50, V_fixture 1.8: 20-80 % time 133ps typ, 277ps min, 75.5ps max; typ from 1.8 V to 0.701 V
|   falling waveform, R_fixture 50, V_fixture 0: 20-80 % time 135ps typ, 206ps min, 71.3ps max; typ from 1.07 V to 0 V
[POWER_clamp]
-1.8V     842.4mA    869.2mA    912.8mA
-1.073V   123.6mA    130.9mA    129mA
-1.036V   94.8mA     102.9mA    96.52mA
-1V       70.82mA    79.68mA    69.62mA
-963.6mV  50.42mA    59.5mA     47.43mA
-927.3mV  33.6mA     42.32mA    29.95mA
-890.9mV  23.68mA    30.78mA    21.23mA
-818.2mV  10.84mA    13.86mA    11.65mA
-781.8mV  8.6mA      9.562mA    10.12mA
-636.4mV  3.971mA    2.6mA      5.151mA
-345.5mV  233.4uA    144.1uA    344.8uA
3.6V      0A         0A         0A
[Pulldown]
-1.8V     -10.48mA   -6.986mA   -6.871mA
-1.145V   -14.76mA   -9.635mA   -12.53mA
-872.7mV  -19.16mA   -11.57mA   -26.86mA
-600mV    -17.63mA   -11.14mA   -24.6mA
1.636V    48.02mA    29.94mA    67.34mA
2.073V    58.18mA    34.17mA    83.16mA
2.291V    61.26mA    32.65mA    90.37mA
2.455V    60.31mA    29.78mA    94.52mA
2.618V    57.35mA    25.94mA    94.79mA
2.782V    51.42mA    22.55mA    92.8mA
3.055V    43.58mA    17.93mA    79.45mA
3.545V    32.44mA    11.99mA    65.6mA
[Pullup]
-1.8V     15.25mA    9.689mA    21.84mA
-818.2mV  16.04mA    10.87mA    21.92mA
-490.9mV  13.71mA    9.212mA    18.64mA
1.036V    -30.4mA    -20.07mA   -41.09mA
2.018V    -57.11mA   -36.81mA   -77.94mA
2.345V    -64.48mA   -38.06mA   -89.56mA
2.618V    -64.84mA   -32.95mA   -96.49mA
2.782V    -59.78mA   -28.7mA    -96.85mA
2.836V    -57.13mA   -27.34mA   -95.02mA
3V        -50.06mA   -23.92mA   -80.63mA
3.218V    -41.82mA   -20.26mA   -57.92mA
3.545V    -34.58mA   -15.09mA   -32.06mA
[GND_clamp]
-1.8V     -697.8mA   -553.2mA   -1.259A
-1.145V   -140.7mA   -131.7mA   -248.3mA
-1.109V   -115.1mA   -111.6mA   -203.3mA
-1.036V   -69.61mA   -74.07mA   -125.9mA
-1V       -53.18mA   -58.25mA   -96.53mA
-927.3mV  -27.97mA   -31.86mA   -45.36mA
-890.9mV  -20.15mA   -23.34mA   -28.45mA
-854.5mV  -13.89mA   -16.39mA   -16.55mA
-818.2mV  -9.202mA   -11.02mA   -9.655mA
-709.1mV  -4.178mA   -4.041mA   -4.8mA
-418.2mV  -167.7uA   -232.8uA   -162.2uA
1.764V    148.6uA    81.78uA    236.4uA
[Ramp]
dV/dt_f   0.743822/0.14027836n 0.55083128/0.29362539n 0.90421527/79.88452p
dV/dt_r 0.66754527/0.12403277n 0.50957888/0.24397358n 0.80975497/75.993973p
R_load = 50
[Rising Waveform]
R_fixture = 50
V_fixture = 1.8
V_fixture_min = 1.62
V_fixture_max = 1.98
62.92ps   700.5mV    808.2mV    625.6mV
82.36ps   700.5mV    808.2mV    804.8mV
137.5ps   700.5mV    808.2mV    1.646V
196.3ps   700mV      808.2mV    1.871V
369.8ps   742.4mV    808.2mV    1.939V
491ps     1.546V     808.2mV    1.953V
595.2ps   1.723V     808.1mV    1.96V
1.03ns    1.778V     827.9mV    1.972V
1.328ns   1.787V     1.491V     1.974V
1.796ns   1.797V     1.618V     1.976V
[Rising Waveform]
R_fixture = 50
V_fixture = 0
V_fixture_min = 0
V_fixture_max = 0
77.43ps   9.235nV    99.72nV    8.891nV
137.5ps   40.55uV    1.537uV    751.4mV
172.2ps   19.46uV    1.722uV    1.031V
301.1ps   -8.13mV    2.33uV     1.248V
409.9ps   -5.78mV    -10.13uV   1.279V
537.3ps   762.9mV    -10.79uV   1.295V
676.6ps   977.9mV    41.23uV    1.303V
1.161ns   1.055V     -44.34mV   1.312V
1.49ns    1.062V     633mV      1.315V
2.2ns     1.074V     799.9mV    1.319V
[Falling Waveform]
R_fixture = 50
V_fixture = 1.8
V_fixture_min = 1.62
V_fixture_max = 1.98
57.88ps   1.797V     1.618V     1.976V
109.4ps   1.798V     1.618V     1.292V
148.8ps   1.808V     1.618V     925mV
238.2ps   1.853V     1.618V     699.9mV
346.8ps   1.885V     1.618V     664.5mV
511.8ps   1.011V     1.618V     647.2mV
653.9ps   776.4mV    1.618V     640.3mV
1.051ns   720.5mV    1.72V      633mV
1.526ns   710.3mV    961mV      629.7mV
2.127ns   700.5mV    808.2mV    625.6mV
[Falling Waveform]
R_fixture = 50
V_fixture = 0
V_fixture_min = 0
V_fixture_max = 0
0s        1.074V     799.9mV    1.319V
101.4ps   1.074V     799.9mV    285.1mV
157.4ps   1.086V     799.9mV    88.01mV
256.5ps   1.033V     799.9mV    47.74mV
407.6ps   284.3mV    799.9mV    25.48mV
501.9ps   78.3mV     799.7mV    18.78mV
940.9ps   19mV       768.3mV    6.56mV
1.144ns   13.59mV    280.2mV    3.765mV
1.275ns   11.3mV     107mV      2.569mV
1.716ns   9.235nV    99.72nV    8.891nV
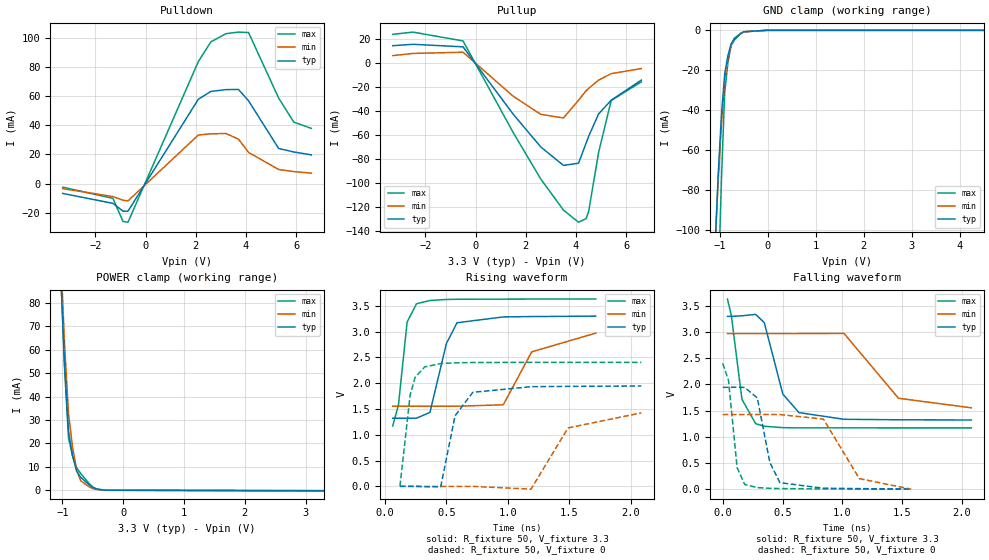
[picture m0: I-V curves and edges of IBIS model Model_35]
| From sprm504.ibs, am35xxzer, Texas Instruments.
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| Model based on original model for BQ1833DV40DTPBFZP18LL_7LM
|   Sub model ZP18LL_7LM_PU_ON_3P3
[model]   Model_35
|[Description]  3.3V-I/O-PU-X
|[Input Load]   PU
|[Output Drive]
|Voltage   3.3V
|Mode   I/O
Model_type   I/O
Polarity   Non-Inverting
Enable   Active-Low
Vinl =  0.8V
Vinh =  2V
Cref =  15pF
Rref =  100.0000M
Vref =  0V
Vmeas =  1.65
C_comp   1.861386p   1.655853p   1.968812p
[Model Spec]
Vinl   0.8V   0.8V   0.8V
Vinh   2V   2V   2V
[Temperature Range]   25   125   -40
[Voltage Range]   3.3   2.97   3.63
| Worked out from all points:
|   slope of the pulldown table from 0 to 0.495 V, typ, clamps not added: 31.5 ohm
|   slope of the pullup table from 0 to 0.495 V, typ, clamps not added: 34.2 ohm
|   GND clamp passes 1 mA (typ) near -0.52 V on its own axis
|   POWER clamp passes 1 mA (typ) near -0.48 V on its own axis
|   rising waveform, R_fixture 50, V_fixture 3.3: 20-80 % time 118ps typ, 208ps min, 63.1ps max; typ from 1.32 V to 3.3 V
|   rising waveform, R_fixture 50, V_fixture 0: 20-80 % time 110ps typ, 205ps min, 71.8ps max; typ from 0.003 V to 1.95 V
|   falling waveform, R_fixture 50, V_fixture 3.3: 20-80 % time 145ps typ, 269ps min, 84.7ps max; typ from 3.3 V to 1.32 V
|   falling waveform, R_fixture 50, V_fixture 0: 20-80 % time 99.3ps typ, 181ps min, 58.2ps max; typ from 1.95 V to 0.003 V
[POWER_clamp]
-3.3V     2.432A     2.868A     2.62A
-1.033V   95.06mA    103.2mA    96.82mA
-966.7mV  54.89mA    63.36mA    52.99mA
-900mV    25.17mA    32.73mA    22.29mA
-833.3mV  14.71mA    18.41mA    14.68mA
-766.7mV  8.177mA    8.865mA    9.637mA
-700mV    5.568mA    4.096mA    7.172mA
-566.7mV  2.478mA    1.576mA    3.075mA
-500mV    1.182mA    756.3uA    1.336mA
-433.3mV  529.8uA    361.2uA    561.7uA
-300mV    28.38uA    26.91uA    30.81uA
3.3V      -177.5uA   -143.5uA   -277.3uA
[Pulldown]
-3.3V     -6.746mA   -3.451mA   -2.449mA
-1.3V     -13.56mA   -8.907mA   -10.16mA
-900mV    -18.87mA   -11.41mA   -25.91mA
-700mV    -18.91mA   -11.83mA   -26.47mA
2.1V      57.81mA    33.29mA    83.64mA
2.6V      63.23mA    34.14mA    97.21mA
3.2V      64.44mA    34.35mA    102.8mA
3.7V      64.57mA    30.45mA    103.9mA
4.1V      56.78mA    21.39mA    103.6mA
5.3V      24.08mA    9.65mA     58.63mA
5.9V      21.68mA    8.241mA    42.2mA
6.6V      19.7mA     7.18mA     37.87mA
[Pullup]
-3.3V     14.58mA    6.278mA    24.04mA
-2.5V     15.74mA    8.096mA    25.94mA
-500mV    13.62mA    9.123mA    18.54mA
1.5V      -42.71mA   -27.72mA   -58.09mA
2.6V      -70.12mA   -42.82mA   -96.97mA
3.5V      -85.45mA   -45.81mA   -122.8mA
4.1V      -83.58mA   -31.01mA   -132.9mA
4.4V      -66.93mA   -23.06mA   -130mA
4.5V      -61.28mA   -21.14mA   -124.2mA
4.9V      -42.38mA   -14.19mA   -74.57mA
5.4V      -31.02mA   -8.795mA   -31.2mA
6.6V      -14.18mA   -4.519mA   -15.68mA
[GND_clamp]
-3.3V     -2.048A    -1.805A    -3.667A
-1.1V     -108.7mA   -106.5mA   -191.5mA
-1.033V   -71.21mA   -74.08mA   -127.8mA
-966.7mV  -42.29mA   -46.88mA   -74.43mA
-900mV    -21.88mA   -24.94mA   -31.36mA
-833.3mV  -12.76mA   -14.54mA   -16.38mA
-766.7mV  -6.884mA   -7.551mA   -7.57mA
-700mV    -4.265mA   -3.97mA    -4.926mA
-566.7mV  -1.605mA   -1.575mA   -1.664mA
-500mV    -702.9uA   -787.9uA   -705.8uA
-33.33mV  0A         0A         0A
6.6V      0A         0A         0A
[Ramp]
dV/dt_f  1.2087899/0.14587212n 0.87079911/0.27137683n  1.4946232/85.095892p
dV/dt_r  1.2002625/0.11074677n 0.89192069/0.20728764n  1.4641647/72.13606p
R_load = 50
[Rising Waveform]
R_fixture = 50
V_fixture = 3.3
V_fixture_min = 2.97
V_fixture_max = 3.63
63.96ps   1.322V     1.555V     1.171V
110.6ps   1.322V     1.555V     1.578V
181.2ps   1.322V     1.555V     3.183V
257.5ps   1.323V     1.555V     3.539V
366.7ps   1.434V     1.555V     3.602V
500.5ps   2.766V     1.555V     3.622V
587.1ps   3.171V     1.555V     3.626V
963.6ps   3.284V     1.582V     3.629V
1.195ns   3.291V     2.608V     3.63V
1.716ns   3.3V       2.97V      3.63V
[Rising Waveform]
R_fixture = 50
V_fixture = 0
V_fixture_min = 0
V_fixture_max = 0
122.9ps   3.381mV    2.142mV    4.746mV
205.9ps   3.55mV     2.144mV    1.772V
246.7ps   3.142mV    2.144mV    2.116V
324.2ps   -4.795mV   2.144mV    2.316V
454.4ps   -5.031mV   2.135mV    2.381V
571.3ps   1.37V      2.169mV    2.395V
715.6ps   1.824V     2.277mV    2.401V
1.189ns   1.933V     -51.69mV   2.404V
1.491ns   1.939V     1.135V     2.404V
2.087ns   1.946V     1.426V     2.404V
[Falling Waveform]
R_fixture = 50
V_fixture = 3.3
V_fixture_min = 2.97
V_fixture_max = 3.63
40.03ps   3.3V       2.97V      3.63V
72.26ps   3.3V       2.97V      3.314V
160.7ps   3.311V     2.97V      1.717V
275.7ps   3.337V     2.97V      1.251V
347.6ps   3.18V      2.97V      1.203V
502.7ps   1.816V     2.97V      1.176V
637.5ps   1.463V     2.972V     1.172V
1.014ns   1.336V     2.974V     1.172V
1.469ns   1.326V     1.737V     1.171V
2.078ns   1.322V     1.555V     1.171V
[Falling Waveform]
R_fixture = 50
V_fixture = 0
V_fixture_min = 0
V_fixture_max = 0
0s        1.946V     1.426V     2.404V
48.54ps   1.946V     1.427V     2.077V
120.3ps   1.948V     1.426V     413.2mV
184.1ps   1.945V     1.426V     90.83mV
289.3ps   1.742V     1.427V     31.92mV
393.6ps   515mV      1.427V     18.14mV
477.9ps   125.2mV    1.426V     13.6mV
841.6ps   20.49mV    1.339V     6.371mV
1.142ns   12.61mV    203.2mV    5.05mV
1.575ns   3.381mV    2.142mV    4.746mV
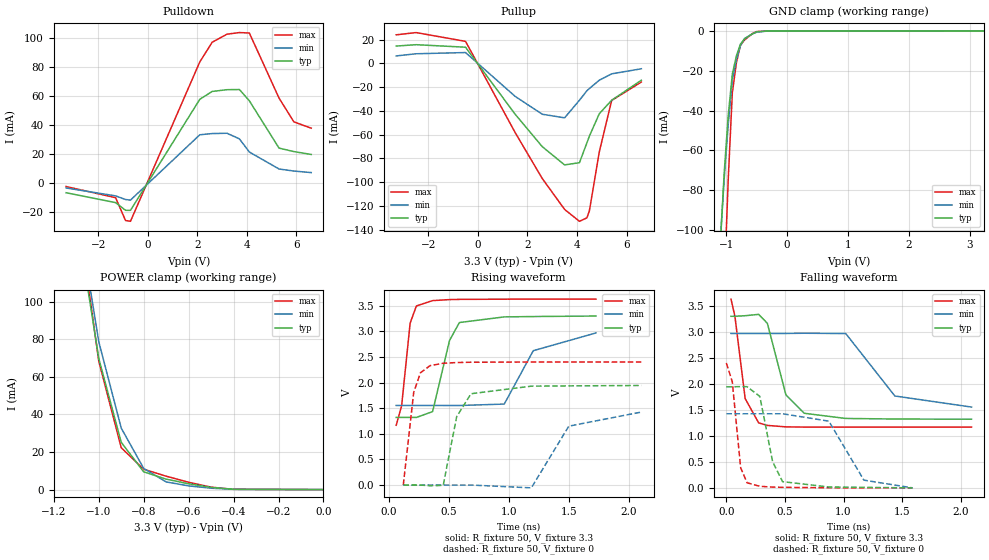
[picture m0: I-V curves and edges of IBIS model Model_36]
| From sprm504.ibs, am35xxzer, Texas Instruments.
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| Model based on original model for BQ1833DV40DTPBFZP18LL_7LM
|   Sub model LL_7LM_PD_PU_OFF_3P3
[model]   Model_36
|[Description]  3.3V-I/O-PI-X
|[Input Load]   PI
|[Output Drive]
|Voltage   3.3V
|Mode   I/O
Model_type   I/O
Polarity   Non-Inverting
Enable   Active-Low
Vinl =  0.8V
Vinh =  2V
Cref =  15pF
Rref =  100.0000M
Vref =  0V
Vmeas =  1.65
C_comp   1.861386p   1.655853p   1.968812p
[Model Spec]
Vinl   0.8V   0.8V   0.8V
Vinh   2V   2V   2V
[Temperature Range]   25   125   -40
[Voltage Range]   3.3   2.97   3.63
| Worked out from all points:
|   slope of the pulldown table from 0 to 0.495 V, typ, clamps not added: 31.5 ohm
|   slope of the pullup table from 0 to 0.495 V, typ, clamps not added: 34.2 ohm
|   GND clamp passes 1 mA (typ) near -0.54 V on its own axis
|   POWER clamp passes 1 mA (typ) near -0.48 V on its own axis
|   rising waveform, R_fixture 50, V_fixture 3.3: 20-80 % time 118ps typ, 208ps min, 63.2ps max; typ from 1.32 V to 3.3 V
|   rising waveform, R_fixture 50, V_fixture 0: 20-80 % time 111ps typ, 206ps min, 72.6ps max; typ from 0 V to 1.94 V
|   falling waveform, R_fixture 50, V_fixture 3.3: 20-80 % time 145ps typ, 270ps min, 84.9ps max; typ from 3.3 V to 1.32 V
|   falling waveform, R_fixture 50, V_fixture 0: 20-80 % time 99.6ps typ, 181ps min, 58.3ps max; typ from 1.94 V to 0 V
[POWER_clamp]
-3.3V     2.432A     2.868A     2.62A
-1.067V   120.3mA    127.7mA    125.3mA
-1.033V   95.04mA    103.2mA    96.8mA
-1V       69.74mA    78.67mA    68.31mA
-900mV    25.15mA    32.72mA    22.27mA
-800mV    9.462mA    11.24mA    10.84mA
-700mV    5.548mA    4.085mA    7.139mA
-600mV    3.106mA    1.975mA    3.91mA
-500mV    1.161mA    745uA      1.301mA
-400mV    184uA      153.2uA    143uA
0V        9.359nA    44.03nA    36.65nA
[Pulldown]
-3.3V     -6.746mA   -3.451mA   -2.449mA
-1.3V     -13.56mA   -8.907mA   -10.16mA
-900mV    -18.87mA   -11.41mA   -25.91mA
-700mV    -18.91mA   -11.83mA   -26.47mA
2.1V      57.81mA    33.29mA    83.64mA
2.6V      63.23mA    34.14mA    97.21mA
3.2V      64.44mA    34.35mA    102.8mA
3.7V      64.57mA    30.45mA    103.9mA
4.1V      56.78mA    21.39mA    103.6mA
5.3V      24.08mA    9.65mA     58.63mA
5.9V      21.68mA    8.241mA    42.2mA
6.6V      19.7mA     7.18mA     37.87mA
[Pullup]
-3.3V     14.58mA    6.278mA    24.04mA
-2.5V     15.74mA    8.096mA    25.94mA
-500mV    13.62mA    9.123mA    18.54mA
1.5V      -42.71mA   -27.72mA   -58.1mA
2.6V      -70.12mA   -42.82mA   -96.98mA
3.5V      -85.45mA   -45.81mA   -122.9mA
4.1V      -83.57mA   -31.01mA   -132.9mA
4.4V      -66.93mA   -23.06mA   -130mA
4.5V      -61.28mA   -21.14mA   -124.2mA
4.9V      -42.37mA   -14.19mA   -74.57mA
5.4V      -31.02mA   -8.795mA   -31.2mA
6.6V      -14.18mA   -4.519mA   -15.68mA
[GND_clamp]
-3.3V     -2.048A    -1.805A    -3.667A
-1.1V     -108.6mA   -106.5mA   -191.4mA
-1.033V   -71.11mA   -74.03mA   -127.7mA
-966.7mV  -42.16mA   -46.82mA   -74.24mA
-900mV    -21.73mA   -24.87mA   -31.1mA
-833.3mV  -12.58mA   -14.46mA   -16.07mA
-766.7mV  -6.691mA   -7.462mA   -7.232mA
-700mV    -4.066mA   -3.873mA   -4.582mA
-566.7mV  -1.404mA   -1.475mA   -1.319mA
-500mV    -501.5uA   -687.7uA   -361.4uA
-300mV    -14.92uA   -26.13uA   -14.52uA
3.233V    8.845nA    14.35uA    33.57nA
[Ramp]
dV/dt_f  1.2101405/0.14624142n 0.87154974/0.27190645n  1.4966894/85.344192p
dV/dt_r  1.2019147/0.11117342n 0.89298646/0.20783779n   1.466257/72.512209p
R_load = 50
[Rising Waveform]
R_fixture = 50
V_fixture = 3.3
V_fixture_min = 2.97
V_fixture_max = 3.63
64.11ps   1.32V      1.554V     1.168V
109.2ps   1.32V      1.554V     1.547V
180.1ps   1.32V      1.554V     3.162V
232.2ps   1.32V      1.554V     3.496V
367.1ps   1.434V     1.554V     3.601V
508.1ps   2.823V     1.553V     3.621V
590.1ps   3.173V     1.553V     3.625V
963.7ps   3.283V     1.581V     3.629V
1.205ns   3.29V      2.623V     3.63V
1.727ns   3.3V       2.97V      3.63V
[Rising Waveform]
R_fixture = 50
V_fixture = 0
V_fixture_min = 0
V_fixture_max = 0
123.1ps   8.59nV     120.6nV    4.064nV
209.9ps   153.7uV    1.814uV    1.811V
266.2ps   -135.6uV   2.245uV    2.193V
346.8ps   -14.17mV   2.266uV    2.332V
455.2ps   -6.197mV   -7.066uV   2.378V
567.2ps   1.333V     23.8uV     2.392V
686.7ps   1.783V     163.2uV    2.398V
1.189ns   1.931V     -54.91mV   2.402V
1.501ns   1.936V     1.15V      2.402V
2.105ns   1.944V     1.425V     2.402V
[Falling Waveform]
R_fixture = 50
V_fixture = 3.3
V_fixture_min = 2.97
V_fixture_max = 3.63
40.1ps    3.3V       2.97V      3.63V
73.28ps   3.3V       2.97V      3.299V
160.8ps   3.311V     2.97V      1.716V
275.8ps   3.337V     2.97V      1.25V
350.1ps   3.165V     2.97V      1.201V
508.3ps   1.79V      2.97V      1.173V
664.3ps   1.435V     2.974V     1.169V
1.019ns   1.335V     2.968V     1.169V
1.438ns   1.324V     1.767V     1.168V
2.092ns   1.32V      1.554V     1.168V
[Falling Waveform]
R_fixture = 50
V_fixture = 0
V_fixture_min = 0
V_fixture_max = 0
0s        1.944V     1.425V     2.402V
50.82ps   1.944V     1.425V     2.04V
122.1ps   1.947V     1.425V     387.5mV
177ps     1.946V     1.425V     97.96mV
286.1ps   1.758V     1.425V     29.71mV
394.9ps   503.2mV    1.425V     14.58mV
480.5ps   119.1mV    1.425V     9.714mV
874.8ps   16.85mV    1.283V     1.575mV
1.174ns   9.493mV    148.2mV    327uV
1.589ns   8.59nV     120.6nV    4.064nV
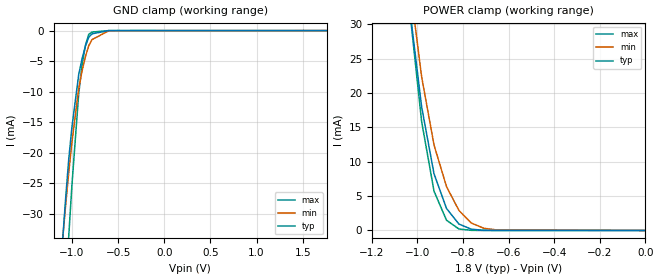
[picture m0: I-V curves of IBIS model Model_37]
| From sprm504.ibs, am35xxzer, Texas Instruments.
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| Model based on original model for IOSCHF18CVSHY_7LM
|   Sub model IOSCHF18CVSHY_7LM
[model]   Model_37
|[Description]  1.8V-INPUT-X-X
|[Input Load]
|[Output Drive]
|Voltage   1.8V
|Mode   INPUT
Model_type   Input
Polarity   Non-Inverting
Vinl =  0.63V
Vinh =  1.17V
C_comp   0.5080431p   0.4467303p   0.5329788p
[Model Spec]
Vinl   0.63V   0.567V   0.693V
Vinh   1.17V   1.053V   1.287V
[Temperature Range]   25   125   -40
[Voltage Range]   1.8   1.62   1.98
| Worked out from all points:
|   GND clamp passes 1 mA (typ) near -0.81 V on its own axis
|   POWER clamp passes 1 mA (typ) near -0.82 V on its own axis
[POWER_clamp]
-1.8V     354.3mA    367.6mA    385.7mA
-1.055V   38.96mA    42.53mA    39.66mA
-1.036V   32.87mA    36.64mA    32.73mA
-1.018V   27.92mA    31.89mA    27.11mA
-981.8mV  18.02mA    22.39mA    15.87mA
-927.3mV  8.247mA    12.44mA    5.718mA
-872.7mV  3.216mA    6.403mA    1.495mA
-818.2mV  933.2uA    2.921mA    215.8uA
-763.6mV  184.6uA    1.082mA    20.05uA
-709.1mV  28.67uA    326uA      1.74uA
-654.5mV  4.205uA    85.05uA    185.3nA
0V        10.17nA    15.39nA    5.686nA
[GND_clamp]
-1.8V     -222.7mA   -177.2mA   -386.2mA
-1.109V   -36.07mA   -35.56mA   -58.06mA
-1.073V   -28.36mA   -29.35mA   -45.31mA
-1.036V   -21.21mA   -23.4mA    -33.93mA
-1V       -15.73mA   -18.23mA   -25.21mA
-927.3mV  -7.236mA   -9.514mA   -10.38mA
-890.9mV  -4.607mA   -6.634mA   -5.688mA
-854.5mV  -2.558mA   -4.283mA   -2.429mA
-818.2mV  -1.089mA   -2.459mA   -601.9uA
-781.8mV  -530.1uA   -1.47mA    -244.7uA
-600mV    -951.9nA   -26.5uA    -37.5nA
1.764V    8.957nA    26.78nA    2.711nA
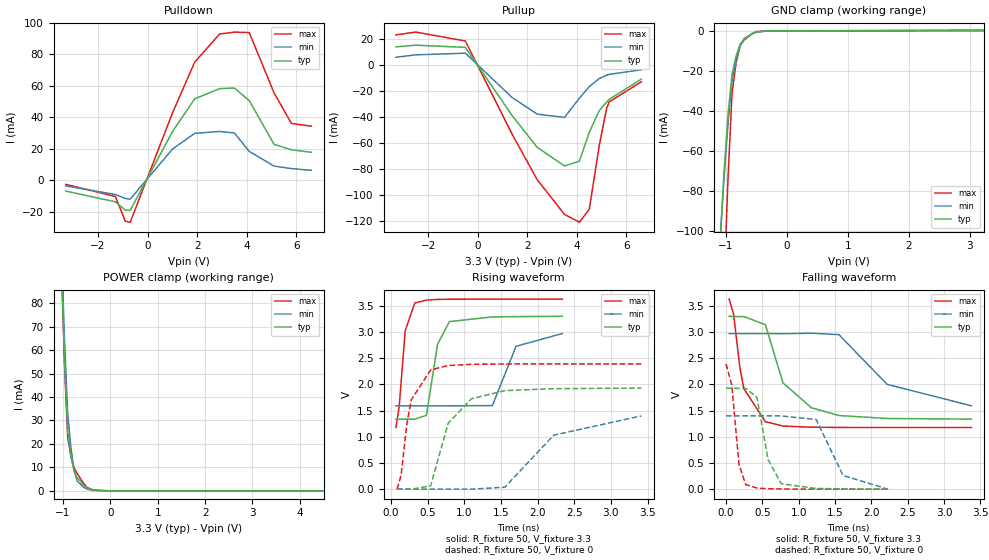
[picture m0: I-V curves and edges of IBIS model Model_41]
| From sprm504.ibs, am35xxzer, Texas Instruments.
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| Model based on original model for BC1833DV40CTPBFZP18LL_7LM_X50
|   Sub model LL_7LM_X50_PD_ON_3P3
[model]   Model_41
|[Description]  3.3V-I/O-PD-X
|[Input Load]   PD
|[Output Drive]
|Voltage   3.3V
|Mode   I/O
Model_type   I/O
Polarity   Non-Inverting
Enable   Active-Low
Vinl =  0.8V
Vinh =  2V
Cref =  15pF
Rref =  100.0000M
Vref =  0V
Vmeas =  1.65
C_comp   1.943144p   1.721292p   2.064363p
[Model Spec]
Vinl   0.8V   0.8V   0.8V
Vinh   2V   2V   2V
[Temperature Range]   25   125   -40
[Voltage Range]   3.3   2.97   3.63
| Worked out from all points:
|   slope of the pulldown table from 0 to 0.495 V, typ, clamps not added: 31.5 ohm
|   slope of the pullup table from 0 to 0.495 V, typ, clamps not added: 34.6 ohm
|   GND clamp passes 1 mA (typ) near -0.54 V on its own axis
|   POWER clamp passes 1 mA (typ) near -0.47 V on its own axis
|   rising waveform, R_fixture 50, V_fixture 3.3: 20-80 % time 136ps typ, 202ps min, 89.3ps max; typ from 1.34 V to 3.3 V
|   rising waveform, R_fixture 50, V_fixture 0: 20-80 % time 311ps typ, 706ps min, 174ps max; typ from 0 V to 1.93 V
|   falling waveform, R_fixture 50, V_fixture 3.3: 20-80 % time 376ps typ, 819ps min, 195ps max; typ from 3.3 V to 1.34 V
|   falling waveform, R_fixture 50, V_fixture 0: 20-80 % time 157ps typ, 244ps min, 92.3ps max; typ from 1.93 V to 0 V
[POWER_clamp]
-3.3V     2.432A     2.868A     2.62A
-1.033V   95.18mA    103.3mA    97.04mA
-966.7mV  55.02mA    63.43mA    53.21mA
-900mV    25.31mA    32.8mA     22.52mA
-833.3mV  14.85mA    18.49mA    14.91mA
-766.7mV  8.321mA    8.944mA    9.874mA
-700mV    5.714mA    4.176mA    7.411mA
-566.7mV  2.625mA    1.655mA    3.318mA
-500mV    1.329mA    834.5uA    1.58mA
-366.7mV  289.8uA    193.7uA    370.6uA
33.33mV   0A         0A         0A
6.6V      0A         0A         0A
[Pulldown]
-3.3V     -6.73mA    -3.436mA   -2.446mA
-1.3V     -13.54mA   -8.893mA   -10.15mA
-900mV    -18.86mA   -11.4mA    -25.9mA
-700mV    -18.91mA   -11.82mA   -26.47mA
1V        30.96mA    19.89mA    42.74mA
1.9V      51.83mA    29.94mA    75.14mA
2.9V      58.3mA     31.12mA    92.92mA
3.5V      58.67mA    30.17mA    94.2mA
4.1V      50.73mA    18.46mA    93.88mA
5.1V      22.94mA    9.149mA    55.64mA
5.8V      19.5mA     7.56mA     36.23mA
6.6V      17.91mA    6.449mA    34.47mA
[Pullup]
-3.3V     13.88mA    5.843mA    23.08mA
-2.5V     15.16mA    7.729mA    25.2mA
-500mV    13.47mA    8.99mA     18.38mA
1.4V      -39.27mA   -25.27mA   -53.66mA
2.4V      -63.29mA   -37.81mA   -88.19mA
3.5V      -77.61mA   -40.33mA   -114.8mA
4.1V      -73.95mA   -25.59mA   -120.8mA
4.5V      -51.77mA   -16.71mA   -110.8mA
4.9V      -35.15mA   -10.47mA   -62.03mA
5.2V      -28.48mA   -7.948mA   -33.38mA
5.3V      -26.46mA   -7.311mA   -28.43mA
6.6V      -10.91mA   -3.736mA   -12.96mA
[GND_clamp]
-3.3V     -2.048A    -1.805A    -3.667A
-1.1V     -108.6mA   -106.5mA   -191.4mA
-1.033V   -71.11mA   -74.03mA   -127.7mA
-966.7mV  -42.16mA   -46.82mA   -74.25mA
-900mV    -21.74mA   -24.87mA   -31.11mA
-833.3mV  -12.59mA   -14.46mA   -16.09mA
-766.7mV  -6.705mA   -7.466mA   -7.261mA
-700mV    -4.083mA   -3.879mA   -4.614mA
-566.7mV  -1.424mA   -1.483mA   -1.356mA
-500mV    -523uA     -696.8uA   -399.5uA
-300mV    -31.01uA   -34.87uA   -39.82uA
3.233V    152.3uA    97.89uA    242.6uA
[Ramp]
dV/dt_f  1.1892245/0.3747241n 0.84328798/0.79901164n   1.474569/0.18907139n
dV/dt_r  1.1648632/0.30867346n 0.84528389/0.70228746n  1.4414373/0.17289076n
R_load = 50
[Rising Waveform]
R_fixture = 50
V_fixture = 3.3
V_fixture_min = 2.97
V_fixture_max = 3.63
67.48ps   1.336V     1.59V      1.176V
111.7ps   1.336V     1.59V      1.57V
194ps     1.336V     1.59V      3.021V
323.9ps   1.335V     1.59V      3.551V
483ps     1.407V     1.59V      3.607V
635.7ps   2.765V     1.59V      3.619V
796.9ps   3.196V     1.59V      3.623V
1.383ns   3.286V     1.593V     3.625V
1.706ns   3.291V     2.725V     3.625V
2.336ns   3.297V     2.968V     3.626V
[Rising Waveform]
R_fixture = 50
V_fixture = 0
V_fixture_min = 0
V_fixture_max = 0
81.84ps   8.544nV    120nV      4.061nV
137.6ps   -87.66nV   500.2nV    259.7mV
213.5ps   11.23uV    51.05nV    1.219V
276ps     -251.2uV   -74.98nV   1.702V
540.4ps   61.74mV    -35.17nV   2.273V
780.2ps   1.256V     34.84nV    2.358V
1.098ns   1.725V     -453.8uV   2.381V
1.553ns   1.879V     37.49mV    2.388V
2.219ns   1.917V     1.029V     2.389V
3.415ns   1.927V     1.398V     2.389V
[Falling Waveform]
R_fixture = 50
V_fixture = 3.3
V_fixture_min = 2.97
V_fixture_max = 3.63
42.72ps   3.297V     2.968V     3.626V
104ps     3.293V     2.968V     3.34V
188.9ps   3.291V     2.968V     2.328V
244.9ps   3.293V     2.968V     1.917V
541.2ps   3.137V     2.968V     1.286V
783.8ps   2.026V     2.965V     1.204V
1.175ns   1.552V     2.975V     1.182V
1.553ns   1.405V     2.947V     1.177V
2.216ns   1.348V     1.999V     1.176V
3.376ns   1.336V     1.59V      1.176V
[Falling Waveform]
R_fixture = 50
V_fixture = 0
V_fixture_min = 0
V_fixture_max = 0
0s        1.927V     1.398V     2.389V
78.09ps   1.924V     1.398V     1.994V
177.7ps   1.922V     1.398V     475.9mV
269.2ps   1.925V     1.398V     89.59mV
425.1ps   1.751V     1.398V     20mV
578.2ps   563.1mV    1.397V     9.373mV
759.2ps   103.9mV    1.397V     4.007mV
1.24ns    13.04mV    1.328V     274.9uV
1.609ns   5.494mV    261.7mV    35.47uV
2.228ns   8.544nV    120nV      4.061nV
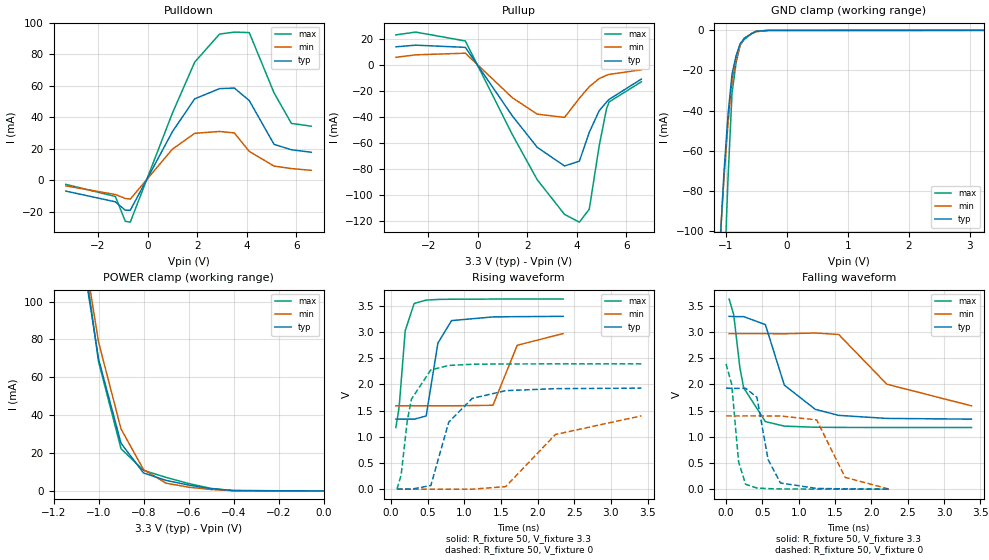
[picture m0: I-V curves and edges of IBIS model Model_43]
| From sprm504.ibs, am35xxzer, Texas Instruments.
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| Model based on original model for BC1833DV40CTPBFZP18LL_7LM_X50
|   Sub model LM_X50_PD_PU_OFF_3P3
[model]   Model_43
|[Description]  3.3V-I/O-PI-X
|[Input Load]   PI
|[Output Drive]
|Voltage   3.3V
|Mode   I/O
Model_type   I/O
Polarity   Non-Inverting
Enable   Active-Low
Vinl =  0.8V
Vinh =  2V
Cref =  15pF
Rref =  100.0000M
Vref =  0V
Vmeas =  1.65
C_comp   1.943144p   1.721292p   2.064363p
[Model Spec]
Vinl   0.8V   0.8V   0.8V
Vinh   2V   2V   2V
[Temperature Range]   25   125   -40
[Voltage Range]   3.3   2.97   3.63
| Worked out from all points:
|   slope of the pulldown table from 0 to 0.495 V, typ, clamps not added: 31.5 ohm
|   slope of the pullup table from 0 to 0.495 V, typ, clamps not added: 34.6 ohm
|   GND clamp passes 1 mA (typ) near -0.54 V on its own axis
|   POWER clamp passes 1 mA (typ) near -0.48 V on its own axis
|   rising waveform, R_fixture 50, V_fixture 3.3: 20-80 % time 137ps typ, 202ps min, 89.4ps max; typ from 1.34 V to 3.3 V
|   rising waveform, R_fixture 50, V_fixture 0: 20-80 % time 315ps typ, 732ps min, 174ps max; typ from 0 V to 1.93 V
|   falling waveform, R_fixture 50, V_fixture 3.3: 20-80 % time 379ps typ, 810ps min, 193ps max; typ from 3.3 V to 1.34 V
|   falling waveform, R_fixture 50, V_fixture 0: 20-80 % time 158ps typ, 244ps min, 92.6ps max; typ from 1.93 V to 0 V
[POWER_clamp]
-3.3V     2.432A     2.868A     2.62A
-1.067V   120.4mA    127.8mA    125.3mA
-1.033V   95.07mA    103.2mA    96.84mA
-1V       69.76mA    78.68mA    68.35mA
-900mV    25.18mA    32.74mA    22.3mA
-800mV    9.485mA    11.26mA    10.87mA
-700mV    5.568mA    4.099mA    7.163mA
-600mV    3.121mA    1.985mA    3.929mA
-500mV    1.172mA    751.7uA    1.314mA
-400mV    187uA      155.3uA    145.6uA
0V        9.358nA    43.99nA    36.65nA
[Pulldown]
-3.3V     -6.73mA    -3.436mA   -2.446mA
-1.3V     -13.54mA   -8.893mA   -10.15mA
-900mV    -18.86mA   -11.4mA    -25.9mA
-700mV    -18.91mA   -11.82mA   -26.47mA
1V        30.96mA    19.89mA    42.74mA
1.9V      51.83mA    29.94mA    75.14mA
2.9V      58.3mA     31.12mA    92.92mA
3.5V      58.67mA    30.17mA    94.2mA
4.1V      50.73mA    18.46mA    93.88mA
5.1V      22.94mA    9.149mA    55.64mA
5.8V      19.5mA     7.56mA     36.23mA
6.6V      17.91mA    6.449mA    34.47mA
[Pullup]
-3.3V     13.88mA    5.843mA    23.08mA
-2.5V     15.16mA    7.729mA    25.2mA
-500mV    13.47mA    8.991mA    18.39mA
1.4V      -39.27mA   -25.27mA   -53.66mA
2.4V      -63.29mA   -37.81mA   -88.19mA
3.5V      -77.61mA   -40.33mA   -114.8mA
4.1V      -73.95mA   -25.59mA   -120.8mA
4.5V      -51.77mA   -16.71mA   -110.8mA
4.9V      -35.15mA   -10.47mA   -62.03mA
5.2V      -28.48mA   -7.948mA   -33.38mA
5.3V      -26.46mA   -7.311mA   -28.43mA
6.6V      -10.91mA   -3.736mA   -12.96mA
[GND_clamp]
-3.3V     -2.048A    -1.805A    -3.667A
-1.1V     -108.6mA   -106.5mA   -191.4mA
-1.033V   -71.11mA   -74.03mA   -127.7mA
-966.7mV  -42.16mA   -46.82mA   -74.24mA
-900mV    -21.73mA   -24.87mA   -31.1mA
-833.3mV  -12.58mA   -14.46mA   -16.07mA
-766.7mV  -6.686mA   -7.459mA   -7.225mA
-700mV    -4.06mA    -3.869mA   -4.574mA
-566.7mV  -1.399mA   -1.472mA   -1.314mA
-500mV    -498.9uA   -685uA     -359.4uA
-300mV    -14.89uA   -26.01uA   -14.51uA
3.233V    8.831nA    14.59uA    33.57nA
[Ramp]
dV/dt_f  1.1903586/0.37663957n 0.84391544/0.80215668n  1.4763083/0.19034253n
dV/dt_r   1.166122/0.30963426n 0.84596527/0.70401191n  1.4433957/0.17355323n
R_load = 50
[Rising Waveform]
R_fixture = 50
V_fixture = 3.3
V_fixture_min = 2.97
V_fixture_max = 3.63
67.33ps   1.337V     1.591V     1.178V
111.6ps   1.337V     1.591V     1.572V
193.9ps   1.337V     1.591V     3.024V
316ps     1.336V     1.591V     3.546V
479.7ps   1.397V     1.591V     3.61V
640ps     2.79V      1.591V     3.623V
826.3ps   3.219V     1.591V     3.627V
1.391ns   3.289V     1.602V     3.63V
1.722ns   3.294V     2.748V     3.63V
2.348ns   3.3V       2.97V      3.63V
[Rising Waveform]
R_fixture = 50
V_fixture = 0
V_fixture_min = 0
V_fixture_max = 0
81.7ps    8.754nV    123.2nV    4.04nV
138.5ps   -91.3nV    494.8nV    269.1mV
221.4ps   16.62uV    30.89nV    1.302V
279.4ps   -306.2uV   -76.49nV   1.72V
543.5ps   69.03mV    -35.08nV   2.278V
788.1ps   1.281V     17.55nV    2.362V
1.109ns   1.734V     -484.5uV   2.385V
1.565ns   1.881V     48.42mV    2.391V
2.242ns   1.919V     1.043V     2.392V
3.415ns   1.929V     1.399V     2.392V
[Falling Waveform]
R_fixture = 50
V_fixture = 3.3
V_fixture_min = 2.97
V_fixture_max = 3.63
42.75ps   3.3V       2.97V      3.63V
105.6ps   3.296V     2.97V      3.33V
189.5ps   3.294V     2.97V      2.328V
242.3ps   3.295V     2.97V      1.936V
541ps     3.142V     2.97V      1.29V
801.8ps   1.986V     2.967V     1.204V
1.228ns   1.524V     2.982V     1.182V
1.549ns   1.409V     2.954V     1.179V
2.212ns   1.351V     2.004V     1.178V
3.376ns   1.337V     1.591V     1.178V
[Falling Waveform]
R_fixture = 50
V_fixture = 0
V_fixture_min = 0
V_fixture_max = 0
0s        1.929V     1.399V     2.392V
77.52ps   1.926V     1.399V     2.003V
172.5ps   1.924V     1.399V     522.7mV
268.9ps   1.927V     1.399V     93.2mV
424.1ps   1.757V     1.399V     21.73mV
578.3ps   565.4mV    1.398V     10.22mV
748.8ps   118mV      1.398V     4.702mV
1.246ns   13.98mV    1.323V     335.9uV
1.638ns   5.808mV    225.1mV    45.25uV
2.248ns   8.754nV    123.2nV    4.04nV
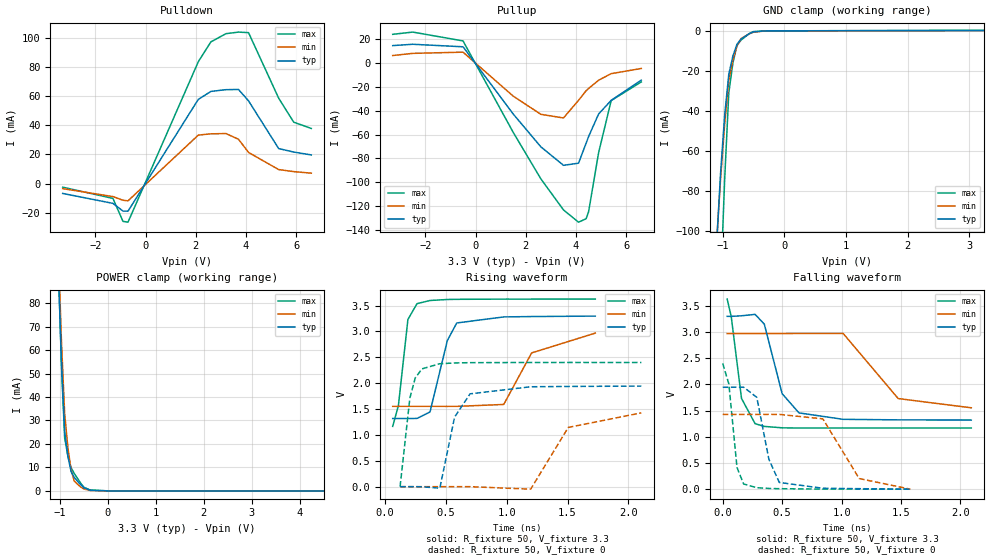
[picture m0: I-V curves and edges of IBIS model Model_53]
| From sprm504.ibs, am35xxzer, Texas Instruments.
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| Model based on original model for BQ1833DV40DTPBFHP18LL_7LM_X50
|   Sub model LL_7LM_X50_PD_ON_3P3
[model]   Model_53
|[Description]  3.3V-I/O-PD-X
|[Input Load]   PD
|[Output Drive]
|Voltage   3.3V
|Mode   I/O
Model_type   I/O
Polarity   Non-Inverting
Enable   Active-Low
Vinl =  0.8V
Vinh =  2V
Cref =  15pF
Rref =  100.0000M
Vref =  0V
Vmeas =  1.65
C_comp   1.964904p   1.748404p   2.088782p
[Model Spec]
Vinl   0.8V   0.8V   0.8V
Vinh   2V   2V   2V
[Temperature Range]   25   125   -40
[Voltage Range]   3.3   2.97   3.63
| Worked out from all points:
|   slope of the pulldown table from 0 to 0.495 V, typ, clamps not added: 31.5 ohm
|   slope of the pullup table from 0 to 0.495 V, typ, clamps not added: 34.1 ohm
|   GND clamp passes 1 mA (typ) near -0.54 V on its own axis
|   POWER clamp passes 1 mA (typ) near -0.47 V on its own axis
|   rising waveform, R_fixture 50, V_fixture 3.3: 20-80 % time 121ps typ, 219ps min, 65.7ps max; typ from 1.32 V to 3.3 V
|   rising waveform, R_fixture 50, V_fixture 0: 20-80 % time 113ps typ, 209ps min, 73.5ps max; typ from 0 V to 1.94 V
|   falling waveform, R_fixture 50, V_fixture 3.3: 20-80 % time 146ps typ, 268ps min, 85.6ps max; typ from 3.3 V to 1.32 V
|   falling waveform, R_fixture 50, V_fixture 0: 20-80 % time 101ps typ, 186ps min, 59.3ps max; typ from 1.94 V to 0 V
[POWER_clamp]
-3.3V     2.432A     2.868A     2.62A
-1.033V   95.18mA    103.3mA    97.04mA
-966.7mV  55.02mA    63.43mA    53.21mA
-900mV    25.31mA    32.8mA     22.52mA
-833.3mV  14.85mA    18.49mA    14.91mA
-766.7mV  8.321mA    8.944mA    9.874mA
-700mV    5.714mA    4.176mA    7.411mA
-566.7mV  2.625mA    1.655mA    3.318mA
-500mV    1.329mA    834.5uA    1.58mA
-366.7mV  289.8uA    193.7uA    370.6uA
33.33mV   0A         0A         0A
6.6V      0A         0A         0A
[Pulldown]
-3.3V     -6.752mA   -3.455mA   -2.453mA
-1.3V     -13.57mA   -8.914mA   -10.17mA
-900mV    -18.88mA   -11.42mA   -25.92mA
-700mV    -18.93mA   -11.84mA   -26.49mA
2.1V      57.83mA    33.3mA     83.68mA
2.6V      63.26mA    34.15mA    97.27mA
3.2V      64.48mA    34.36mA    102.9mA
3.7V      64.6mA     30.45mA    104mA
4.1V      56.79mA    21.38mA    103.6mA
5.3V      24.05mA    9.632mA    58.63mA
5.9V      21.65mA    8.225mA    42.16mA
6.6V      19.68mA    7.168mA    37.84mA
[Pullup]
-3.3V     14.63mA    6.311mA    24.1mA
-2.5V     15.75mA    8.119mA    25.97mA
-500mV    13.64mA    9.134mA    18.56mA
1.5V      -42.79mA   -27.78mA   -58.2mA
2.6V      -70.29mA   -43mA      -97.17mA
3.5V      -85.79mA   -46.07mA   -123.2mA
4.1V      -84mA      -31.26mA   -133.5mA
4.4V      -67.35mA   -23.27mA   -130.6mA
4.5V      -61.7mA    -21.35mA   -124.8mA
4.9V      -42.71mA   -14.38mA   -75.13mA
5.4V      -31.3mA    -8.901mA   -31.49mA
6.6V      -14.33mA   -4.555mA   -15.8mA
[GND_clamp]
-3.3V     -2.048A    -1.805A    -3.667A
-1.1V     -108.6mA   -106.5mA   -191.4mA
-1.033V   -71.11mA   -74.03mA   -127.7mA
-966.7mV  -42.16mA   -46.82mA   -74.25mA
-900mV    -21.74mA   -24.87mA   -31.11mA
-833.3mV  -12.59mA   -14.46mA   -16.09mA
-766.7mV  -6.705mA   -7.466mA   -7.261mA
-700mV    -4.083mA   -3.879mA   -4.614mA
-566.7mV  -1.424mA   -1.483mA   -1.356mA
-500mV    -523uA     -696.8uA   -399.5uA
-300mV    -31.01uA   -34.87uA   -39.82uA
3.233V    152.3uA    97.89uA    242.6uA
[Ramp]
dV/dt_f  1.2091204/0.1465874n 0.87076811/0.27080558n  1.4948941/86.079241p
dV/dt_r  1.2018855/0.11361734n 0.89283733/0.21126848n  1.4662521/73.921779p
R_load = 50
[Rising Waveform]
R_fixture = 50
V_fixture = 3.3
V_fixture_min = 2.97
V_fixture_max = 3.63
63.74ps   1.318V     1.552V     1.166V
110.5ps   1.318V     1.552V     1.567V
188.7ps   1.318V     1.552V     3.232V
263.2ps   1.319V     1.552V     3.537V
370.2ps   1.444V     1.552V     3.598V
512.2ps   2.822V     1.552V     3.618V
589.8ps   3.164V     1.552V     3.621V
975.8ps   3.281V     1.589V     3.625V
1.205ns   3.288V     2.585V     3.625V
1.728ns   3.297V     2.968V     3.626V
[Rising Waveform]
R_fixture = 50
V_fixture = 0
V_fixture_min = 0
V_fixture_max = 0
124.3ps   8.544nV    119.7nV    4.096nV
204.8ps   162.4uV    97.29nV    1.714V
248.8ps   -235.1uV   819.9nV    2.102V
304ps     -2.578mV   1.552uV    2.277V
450.9ps   -28.14mV   -4.378uV   2.376V
572.1ps   1.345V     32uV       2.391V
699ps     1.794V     150.2uV    2.397V
1.197ns   1.931V     -48.12mV   2.4V
1.506ns   1.937V     1.145V     2.401V
2.106ns   1.944V     1.426V     2.4V
[Falling Waveform]
R_fixture = 50
V_fixture = 3.3
V_fixture_min = 2.97
V_fixture_max = 3.63
37.49ps   3.297V     2.968V     3.626V
71.46ps   3.296V     2.968V     3.295V
158.2ps   3.307V     2.968V     1.73V
272.6ps   3.334V     2.968V     1.249V
349.8ps   3.148V     2.968V     1.197V
499.9ps   1.821V     2.968V     1.17V
641ps     1.455V     2.97V      1.166V
1.013ns   1.332V     2.97V      1.167V
1.476ns   1.322V     1.728V     1.166V
2.091ns   1.318V     1.552V     1.166V
[Falling Waveform]
R_fixture = 50
V_fixture = 0
V_fixture_min = 0
V_fixture_max = 0
0s        1.944V     1.426V     2.4V
51.77ps   1.943V     1.426V     2.006V
120.1ps   1.946V     1.426V     414.9mV
175.5ps   1.945V     1.426V     99.02mV
286.8ps   1.752V     1.426V     27.76mV
388.4ps   569.1mV    1.426V     13.76mV
476.1ps   127.6mV    1.426V     8.948mV
842.2ps   17.21mV    1.341V     1.673mV
1.148ns   9.266mV    202.7mV    307.5uV
1.578ns   8.544nV    119.7nV    4.096nV
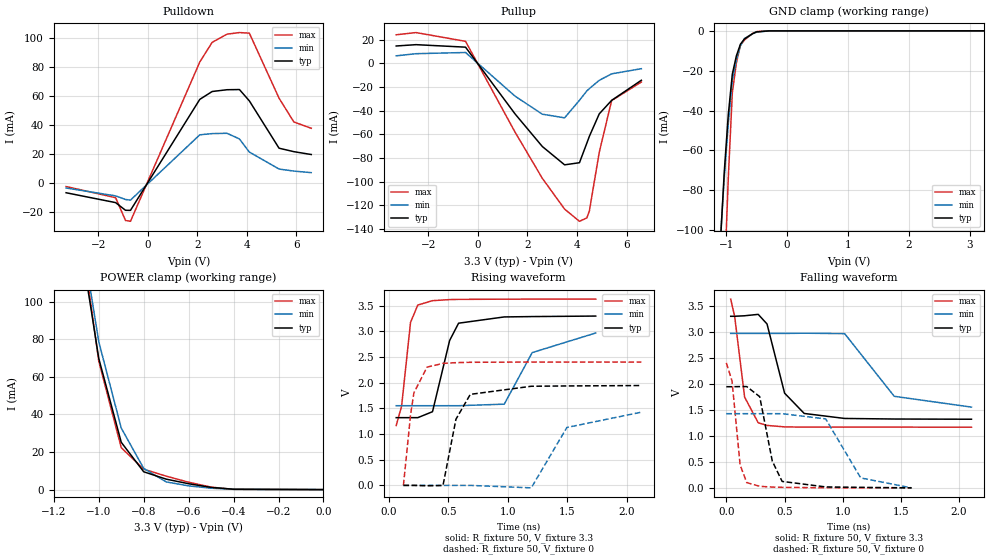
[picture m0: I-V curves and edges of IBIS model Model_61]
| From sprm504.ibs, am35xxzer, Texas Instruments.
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| Model based on original model for BQ1833DV40DTPBFZP18LL_7LM_X50
|   Sub model LM_X50_PD_PU_OFF_3P3
[model]   Model_61
|[Description]  3.3V-I/O-PI-X
|[Input Load]   PI
|[Output Drive]
|Voltage   3.3V
|Mode   I/O
Model_type   I/O
Polarity   Non-Inverting
Enable   Active-Low
Vinl =  0.8V
Vinh =  2V
Cref =  15pF
Rref =  100.0000M
Vref =  0V
Vmeas =  1.65
C_comp   1.964904p   1.748404p   2.088782p
[Model Spec]
Vinl   0.8V   0.8V   0.8V
Vinh   2V   2V   2V
[Temperature Range]   25   125   -40
[Voltage Range]   3.3   2.97   3.63
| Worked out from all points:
|   slope of the pulldown table from 0 to 0.495 V, typ, clamps not added: 31.5 ohm
|   slope of the pullup table from 0 to 0.495 V, typ, clamps not added: 34.1 ohm
|   GND clamp passes 1 mA (typ) near -0.54 V on its own axis
|   POWER clamp passes 1 mA (typ) near -0.48 V on its own axis
|   rising waveform, R_fixture 50, V_fixture 3.3: 20-80 % time 121ps typ, 219ps min, 65.9ps max; typ from 1.32 V to 3.3 V
|   rising waveform, R_fixture 50, V_fixture 0: 20-80 % time 113ps typ, 210ps min, 73.7ps max; typ from 0 V to 1.95 V
|   falling waveform, R_fixture 50, V_fixture 3.3: 20-80 % time 146ps typ, 269ps min, 85.9ps max; typ from 3.3 V to 1.32 V
|   falling waveform, R_fixture 50, V_fixture 0: 20-80 % time 101ps typ, 186ps min, 59.6ps max; typ from 1.95 V to 0 V
[POWER_clamp]
-3.3V     2.432A     2.868A     2.62A
-1.067V   120.4mA    127.8mA    125.3mA
-1.033V   95.07mA    103.2mA    96.84mA
-1V       69.76mA    78.68mA    68.35mA
-900mV    25.18mA    32.74mA    22.3mA
-800mV    9.485mA    11.26mA    10.87mA
-700mV    5.568mA    4.099mA    7.163mA
-600mV    3.121mA    1.985mA    3.929mA
-500mV    1.172mA    751.7uA    1.314mA
-400mV    187uA      155.3uA    145.6uA
0V        9.358nA    43.99nA    36.65nA
[Pulldown]
-3.3V     -6.752mA   -3.455mA   -2.453mA
-1.3V     -13.57mA   -8.914mA   -10.17mA
-900mV    -18.88mA   -11.42mA   -25.92mA
-700mV    -18.93mA   -11.84mA   -26.49mA
2.1V      57.83mA    33.3mA     83.68mA
2.6V      63.26mA    34.15mA    97.27mA
3.2V      64.48mA    34.36mA    102.9mA
3.7V      64.6mA     30.45mA    104mA
4.1V      56.79mA    21.38mA    103.6mA
5.3V      24.05mA    9.632mA    58.63mA
5.9V      21.65mA    8.225mA    42.16mA
6.6V      19.68mA    7.168mA    37.84mA
[Pullup]
-3.3V     14.63mA    6.311mA    24.1mA
-2.5V     15.75mA    8.119mA    25.97mA
-500mV    13.64mA    9.134mA    18.56mA
1.5V      -42.79mA   -27.78mA   -58.2mA
2.6V      -70.29mA   -43mA      -97.17mA
3.5V      -85.79mA   -46.07mA   -123.2mA
4.1V      -84mA      -31.26mA   -133.5mA
4.4V      -67.35mA   -23.27mA   -130.6mA
4.5V      -61.7mA    -21.35mA   -124.8mA
4.9V      -42.71mA   -14.38mA   -75.13mA
5.4V      -31.3mA    -8.901mA   -31.49mA
6.6V      -14.33mA   -4.555mA   -15.8mA
[GND_clamp]
-3.3V     -2.048A    -1.805A    -3.667A
-1.1V     -108.6mA   -106.5mA   -191.4mA
-1.033V   -71.11mA   -74.03mA   -127.7mA
-966.7mV  -42.16mA   -46.82mA   -74.24mA
-900mV    -21.73mA   -24.87mA   -31.1mA
-833.3mV  -12.58mA   -14.46mA   -16.07mA
-766.7mV  -6.686mA   -7.459mA   -7.225mA
-700mV    -4.06mA    -3.869mA   -4.574mA
-566.7mV  -1.399mA   -1.472mA   -1.314mA
-500mV    -498.9uA   -685uA     -359.4uA
-300mV    -14.89uA   -26.01uA   -14.51uA
3.233V    8.831nA    14.59uA    33.57nA
[Ramp]
dV/dt_f  1.2102778/0.14704076n 0.87131576/0.27127064n  1.4966993/86.392561p
dV/dt_r  1.2031224/0.11396233n  0.8934998/0.21169083n  1.4681882/74.132671p
R_load = 50
[Rising Waveform]
R_fixture = 50
V_fixture = 3.3
V_fixture_min = 2.97
V_fixture_max = 3.63
63.58ps   1.32V      1.553V     1.167V
108.9ps   1.32V      1.553V     1.545V
183.8ps   1.32V      1.553V     3.176V
244.6ps   1.32V      1.553V     3.514V
368.2ps   1.436V     1.553V     3.6V
512ps     2.824V     1.553V     3.621V
587.1ps   3.161V     1.553V     3.625V
970.1ps   3.283V     1.583V     3.629V
1.205ns   3.29V      2.588V     3.63V
1.738ns   3.3V       2.97V      3.63V
[Rising Waveform]
R_fixture = 50
V_fixture = 0
V_fixture_min = 0
V_fixture_max = 0
124.2ps   8.754nV    122.9nV    4.075nV
184.7ps   205.4uV    -297.4nV   1.388V
212.2ps   129.9uV    227.9nV    1.805V
322.5ps   -7.526mV   1.543uV    2.305V
456.1ps   -2.466mV   -4.562uV   2.378V
565ps     1.29V      26.25uV    2.392V
685.4ps   1.774V     163.1uV    2.399V
1.197ns   1.932V     -48.06mV   2.404V
1.496ns   1.938V     1.129V     2.404V
2.121ns   1.946V     1.427V     2.404V
[Falling Waveform]
R_fixture = 50
V_fixture = 3.3
V_fixture_min = 2.97
V_fixture_max = 3.63
37.49ps   3.3V       2.97V      3.63V
71.34ps   3.3V       2.97V      3.301V
157.3ps   3.31V      2.97V      1.744V
274ps     3.337V     2.97V      1.252V
349.8ps   3.152V     2.97V      1.201V
500.8ps   1.821V     2.97V      1.173V
669.4ps   1.431V     2.975V     1.168V
1.017ns   1.335V     2.966V     1.168V
1.443ns   1.324V     1.761V     1.168V
2.107ns   1.32V      1.553V     1.167V
[Falling Waveform]
R_fixture = 50
V_fixture = 0
V_fixture_min = 0
V_fixture_max = 0
0s        1.946V     1.427V     2.404V
48.68ps   1.945V     1.427V     2.059V
118.7ps   1.948V     1.427V     436.7mV
175.5ps   1.948V     1.427V     101.5mV
286.8ps   1.754V     1.427V     29.76mV
394.9ps   515.5mV    1.427V     14.67mV
479.4ps   124mV      1.427V     9.847mV
854.3ps   17.86mV    1.326V     1.81mV
1.155ns   10mV       191mV      373.8uV
1.592ns   8.754nV    122.9nV    4.075nV
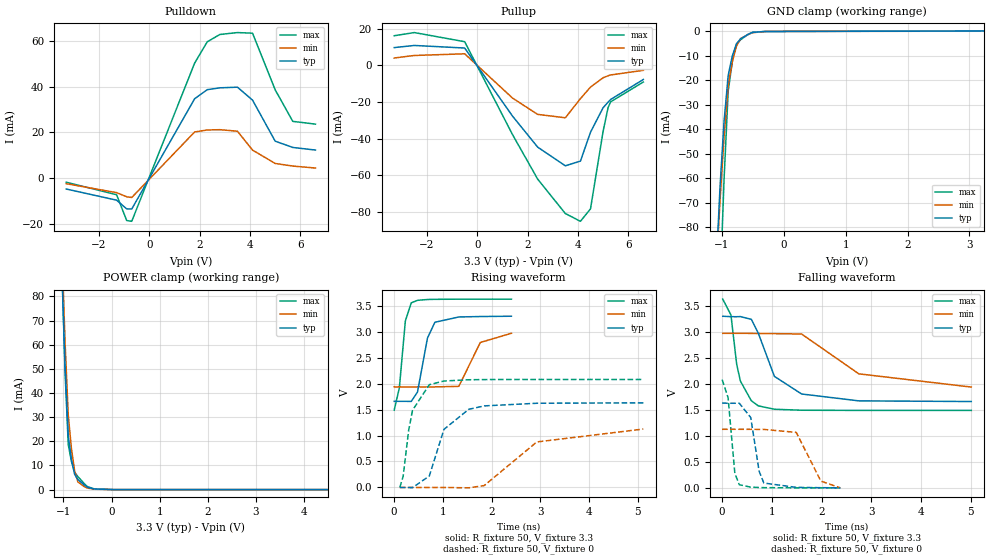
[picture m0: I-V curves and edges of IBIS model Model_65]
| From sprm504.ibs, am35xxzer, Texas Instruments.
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| Model based on original model for BC1833DV50BTPBFHP18LL_7LM_X50
|   Sub model LL_7LM_X50_PD_ON_3P3
[model]   Model_65
|[Description]  3.3V-I/O-PD-X
|[Input Load]   PD
|[Output Drive]
|Voltage   3.3V
|Mode   I/O
Model_type   I/O
Polarity   Non-Inverting
Enable   Active-Low
Vinl =  0.8V
Vinh =  2V
Cref =  15pF
Rref =  100.0000M
Vref =  0V
Vmeas =  1.65
C_comp   1.683006p   1.492615p   1.787227p
[Model Spec]
Vinl   0.8V   0.8V   0.8V
Vinh   2V   2V   2V
[Temperature Range]   25   125   -40
[Voltage Range]   3.3   2.97   3.63
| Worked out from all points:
|   slope of the pulldown table from 0 to 0.495 V, typ, clamps not added: 44.5 ohm
|   slope of the pullup table from 0 to 0.495 V, typ, clamps not added: 49.1 ohm
|   GND clamp passes 1 mA (typ) near -0.56 V on its own axis
|   POWER clamp passes 1 mA (typ) near -0.50 V on its own axis
|   rising waveform, R_fixture 50, V_fixture 3.3: 20-80 % time 195ps typ, 280ps min, 122ps max; typ from 1.66 V to 3.3 V
|   rising waveform, R_fixture 50, V_fixture 0: 20-80 % time 427ps typ, 984ps min, 234ps max; typ from 0 V to 1.63 V
|   falling waveform, R_fixture 50, V_fixture 3.3: 20-80 % time 494ps typ, 983ps min, 224ps max; typ from 3.3 V to 1.66 V
|   falling waveform, R_fixture 50, V_fixture 0: 20-80 % time 155ps typ, 285ps min, 110ps max; typ from 1.63 V to 0 V
[POWER_clamp]
-3.3V     2.414A     2.856A     2.597A
-1.033V   91.41mA    100.8mA    92.12mA
-966.7mV  51.65mA    61.21mA    48.79mA
-900mV    22.33mA    30.87mA    18.6mA
-833.3mV  12.34mA    16.87mA    11.61mA
-766.7mV  6.286mA    7.643mA    7.215mA
-700mV    4.163mA    3.191mA    5.404mA
-566.7mV  1.931mA    1.219mA    2.461mA
-500mV    997.5uA    621.5uA    1.208mA
-366.7mV  252.8uA    162.2uA    342.1uA
33.33mV   0A         0A         0A
6.6V      0A         0A         0A
[Pulldown]
-3.3V     -4.669mA   -2.345mA   -1.683mA
-1.3V     -9.527mA   -6.237mA   -7.18mA
-900mV    -13.33mA   -8.043mA   -18.4mA
-700mV    -13.38mA   -8.364mA   -18.74mA
1.8V      34.72mA    20.23mA    50.27mA
2.3V      38.67mA    21.09mA    59.54mA
2.8V      39.47mA    21.22mA    62.74mA
3.5V      39.76mA    20.55mA    63.58mA
4.1V      34.11mA    12.32mA    63.3mA
5V        16.21mA    6.486mA    38.59mA
5.7V      13.47mA    5.354mA    24.85mA
6.6V      12.34mA    4.484mA    23.64mA
[Pullup]
-3.3V     9.738mA    4.045mA    16.21mA
-2.5V     10.91mA    5.432mA    17.95mA
-500mV    9.5mA      6.347mA    12.96mA
1.4V      -27.68mA   -17.82mA   -37.78mA
2.4V      -44.64mA   -26.76mA   -62.11mA
3.5V      -54.84mA   -28.6mA    -80.92mA
4.1V      -52.27mA   -18.13mA   -85.16mA
4.5V      -36.47mA   -11.82mA   -78.34mA
5V        -23.1mA    -6.724mA   -36.03mA
5.2V      -20.04mA   -5.652mA   -22.93mA
5.3V      -18.59mA   -5.203mA   -19.89mA
6.6V      -7.68mA    -2.683mA   -9.05mA
[GND_clamp]
-3.3V     -1.975A    -1.766A    -3.378A
-1.1V     -99.4mA    -100.8mA   -162mA
-1.033V   -63.74mA   -69.32mA   -106.1mA
-966.7mV  -36.57mA   -43.05mA   -60.18mA
-900mV    -17.88mA   -22.01mA   -24.32mA
-833.3mV  -10.01mA   -12.38mA   -12.35mA
-766.7mV  -5.054mA   -6.023mA   -5.382mA
-700mV    -3.018mA   -2.938mA   -3.413mA
-566.7mV  -1.062mA   -1.101mA   -1.024mA
-500mV    -403.5uA   -520.7uA   -326.7uA
-300mV    -30.38uA   -31.17uA   -39.69uA
3.233V    152.3uA    93.7uA     242.6uA
[Ramp]
dV/dt_f 0.98320301/0.49347442n 0.61923758/0.96014811n  1.2820937/0.22321178n
dV/dt_r 0.98244474/0.42474888n 0.67992646/0.9752817n  1.2527544/0.23239197n
R_load = 50
[Rising Waveform]
R_fixture = 50
V_fixture = 3.3
V_fixture_min = 2.97
V_fixture_max = 3.63
2.391ps   1.658V     1.936V     1.488V
108.2ps   1.658V     1.936V     1.917V
231.1ps   1.658V     1.936V     3.204V
352.2ps   1.656V     1.936V     3.553V
481.2ps   1.838V     1.936V     3.602V
685ps     2.875V     1.936V     3.618V
837.7ps   3.18V      1.936V     3.621V
1.329ns   3.282V     1.946V     3.624V
1.77ns    3.29V      2.791V     3.624V
2.409ns   3.296V     2.968V     3.625V
[Rising Waveform]
R_fixture = 50
V_fixture = 0
V_fixture_min = 0
V_fixture_max = 0
117.1ps   8.104nV    108.3nV    4.143nV
185.6ps   2.26uV     -319.2nV   211.1mV
299.7ps   -217.4uV   -421.2nV   1.103V
378.4ps   -2.931mV   -58.55nV   1.486V
722.9ps   220.6mV    69.71nV    1.978V
1.024ns   1.119V     8.261uV    2.049V
1.532ns   1.504V     -7.378mV   2.073V
1.85ns    1.57V      37.12mV    2.077V
2.93ns    1.621V     876.2mV    2.079V
5.117ns   1.629V     1.125V     2.079V
[Falling Waveform]
R_fixture = 50
V_fixture = 3.3
V_fixture_min = 2.97
V_fixture_max = 3.63
12.82ps   3.296V     2.968V     3.625V
177.4ps   3.288V     2.968V     3.321V
293.2ps   3.287V     2.968V     2.372V
367.6ps   3.29V      2.968V     2.052V
588.2ps   3.237V     2.967V     1.673V
728.7ps   2.969V     2.964V     1.575V
1.052ns   2.141V     2.962V     1.51V
1.599ns   1.803V     2.955V     1.491V
2.75ns    1.671V     2.19V      1.488V
5.013ns   1.658V     1.936V     1.488V
[Falling Waveform]
R_fixture = 50
V_fixture = 0
V_fixture_min = 0
V_fixture_max = 0
0s        1.629V     1.125V     2.079V
119.6ps   1.625V     1.125V     1.735V
256.3ps   1.625V     1.125V     276.9mV
345.2ps   1.626V     1.125V     60.96mV
575.9ps   1.351V     1.124V     13.9mV
745ps     317.5mV    1.123V     6.761mV
839.2ps   92.27mV    1.123V     4.162mV
1.492ns   9.493mV    1.065V     141.1uV
1.987ns   3.308mV    129.7mV    14.53uV
2.38ns    8.104nV    108.3nV    4.143nV
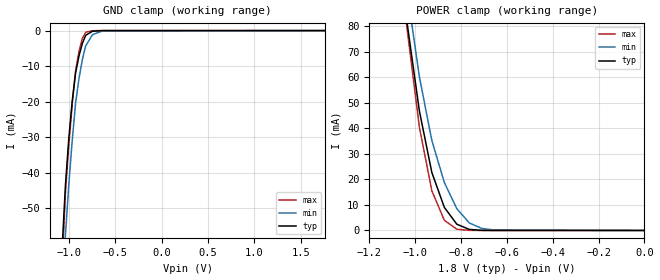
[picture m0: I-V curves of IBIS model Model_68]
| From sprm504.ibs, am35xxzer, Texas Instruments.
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| Model based on original model for IHHV1833DVTP18_7LM
|   Sub model HV1833DVTP18_7LM_1P8
[model]   Model_68
|[Description]  1.8V-INPUT-X-X
|[Input Load]
|[Output Drive]
|Voltage   1.8V
|Mode   INPUT
Model_type   Input
Polarity   Non-Inverting
Vinl =  0.63V
Vinh =  1.17V
C_comp   0.7294814p   0.6184726p   0.8493104p
[Model Spec]
Vinl   0.63V   0.567V   0.693V
Vinh   1.17V   1.053V   1.287V
[Temperature Range]   25   125   -40
[Voltage Range]   1.8   1.62   1.98
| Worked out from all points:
|   GND clamp passes 1 mA (typ) near -0.80 V on its own axis
|   POWER clamp passes 1 mA (typ) near -0.78 V on its own axis
[POWER_clamp]
-1.8V     812.3mA    848.6mA    874.4mA
-1.055V   95.8mA     108mA      95.3mA
-1.036V   81.75mA    94.23mA    79.52mA
-1.018V   70.12mA    82.89mA    66.5mA
-981.8mV  46.85mA    60.21mA    40.46mA
-927.3mV  22.71mA    35.24mA    15.54mA
-872.7mV  9.032mA    18.78mA    3.979mA
-818.2mV  2.437mA    8.5mA      488.7uA
-763.6mV  416.7uA    2.939mA    41.09uA
-709.1mV  59.39uA    784.9uA    3.473uA
-654.5mV  8.326uA    184.9uA    400.3nA
0V        22.82nA    12.2nA     88.12nA
[GND_clamp]
-1.8V     -591.8mA   -493.6mA   -847.7mA
-1.073V   -61.54mA   -73.68mA   -66.85mA
-1.036V   -43.21mA   -57.22mA   -45.44mA
-1V       -30.24mA   -43.23mA   -32.1mA
-963.6mV  -19.8mA    -30.95mA   -20.75mA
-927.3mV  -11.89mA   -20.39mA   -11.39mA
-890.9mV  -7.153mA   -13.54mA   -5.845mA
-854.5mV  -3.632mA   -8.175mA   -2.205mA
-818.2mV  -1.328mA   -4.293mA   -469.7uA
-745.5mV  -192.7uA   -1.146mA   -34.49uA
-636.4mV  -5.028uA   -90.79uA   -267.7nA
1.764V    22.6nA     12.79nA    79.89nA
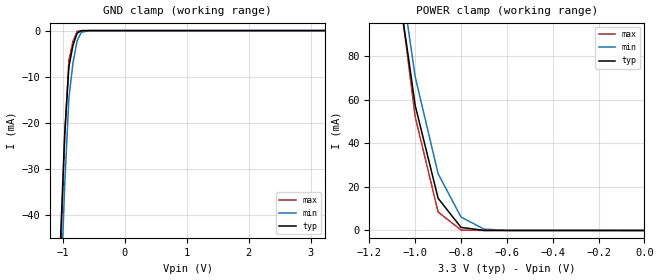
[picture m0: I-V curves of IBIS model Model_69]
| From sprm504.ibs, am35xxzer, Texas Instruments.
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| Model based on original model for IHHV1833DVTP18_7LM
|   Sub model HV1833DVTP18_7LM_3P3
[model]   Model_69
|[Description]  3.3V-INPUT-X-X
|[Input Load]
|[Output Drive]
|Voltage   3.3V
|Mode   INPUT
Model_type   Input
Polarity   Non-Inverting
Vinl =  0.8V
Vinh =  2V
C_comp   0.6935759p   0.5873084p   0.8051541p
[Model Spec]
Vinl   0.8V   0.8V   0.8V
Vinh   2V   2V   2V
[Temperature Range]   25   125   -40
[Voltage Range]   3.3   2.97   3.63
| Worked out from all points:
|   GND clamp passes 1 mA (typ) near -0.78 V on its own axis
|   POWER clamp passes 1 mA (typ) near -0.77 V on its own axis
[POWER_clamp]
-3.3V     2.37A      2.825A     2.542A
-1.067V   106.7mA    118.7mA    107.5mA
-1.033V   82.08mA    94.67mA    79.86mA
-1V       57.43mA    70.6mA     52.18mA
-900mV    14.79mA    26.08mA    8.469mA
-800mV    1.407mA    6.167mA    217.1uA
-700mV    42.79uA    620uA      2.441uA
-600mV    1.22uA     42.15uA    237.6nA
0V        32.72nA    14.4nA     165.7nA
[GND_clamp]
-3.3V     -1.789A    -1.667A    -2.617A
-1.033V   -44.81mA   -57.25mA   -48.92mA
-966.7mV  -22.13mA   -33.35mA   -22.95mA
-900mV    -7.849mA   -14.6mA    -6.399mA
-833.3mV  -3.15mA    -6.926mA   -2.286mA
-766.7mV  -544.9uA   -2.179mA   -154.2uA
-700mV    -32.68uA   -358.6uA   -2.922uA
-566.7mV  -746.9nA   -21.95uA   -23.21nA
3.233V    32.19nA    27.04nA    142.8nA
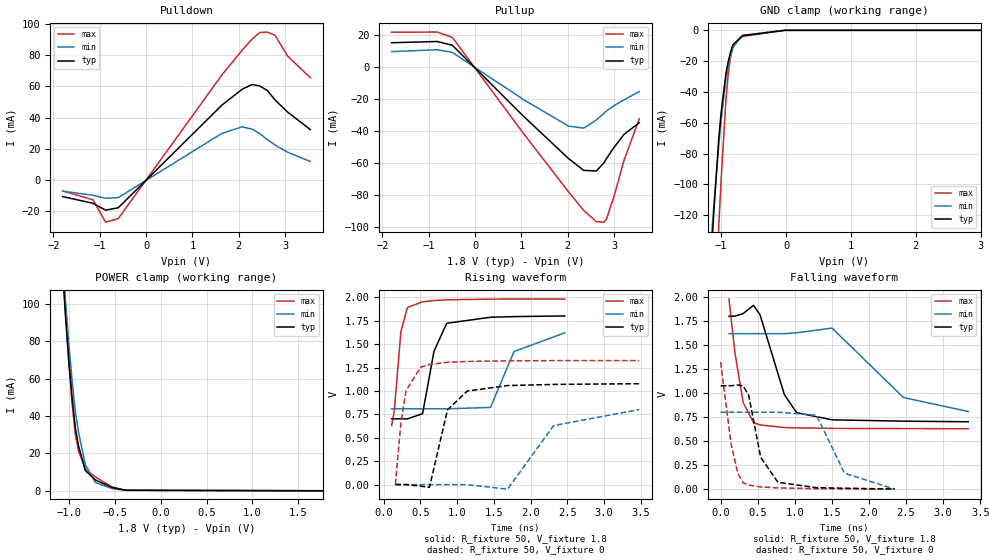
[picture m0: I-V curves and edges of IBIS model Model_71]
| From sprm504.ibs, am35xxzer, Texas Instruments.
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| Model based on original model for BC1833DV40CTPBFHP18LL_7LM_X50
|   Sub model LL_7LM_X50_PU_ON_1P8
[model]   Model_71
|[Description]  1.8V-I/O-PU-X
|[Input Load]   PU
|[Output Drive]
|Voltage   1.8V
|Mode   I/O
Model_type   I/O
Polarity   Non-Inverting
Enable   Active-Low
Vinl =  0.63V
Vinh =  1.17V
Cref =  15pF
Rref =  100.0000M
Vref =  0V
Vmeas =  0.9
C_comp   2.232809p   2.073051p   2.295852p
[Model Spec]
Vinl   0.63V   0.567V   0.693V
Vinh   1.17V   1.053V   1.287V
[Temperature Range]   25   125   -40
[Voltage Range]   1.8   1.62   1.98
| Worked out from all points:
|   slope of the pulldown table from 0 to 0.27 V, typ, clamps not added: 31.4 ohm
|   slope of the pullup table from 0 to 0.27 V, typ, clamps not added: 33.4 ohm
|   GND clamp passes 1 mA (typ) near -0.53 V on its own axis
|   POWER clamp passes 1 mA (typ) near -0.49 V on its own axis
|   rising waveform, R_fixture 50, V_fixture 1.8: 20-80 % time 174ps typ, 260ps min, 93ps max; typ from 0.703 V to 1.8 V
|   rising waveform, R_fixture 50, V_fixture 0: 20-80 % time 226ps typ, 478ps min, 132ps max; typ from 0.003 V to 1.08 V
|   falling waveform, R_fixture 50, V_fixture 1.8: 20-80 % time 285ps typ, 647ps min, 154ps max; typ from 1.8 V to 0.703 V
|   falling waveform, R_fixture 50, V_fixture 0: 20-80 % time 213ps typ, 260ps min, 145ps max; typ from 1.08 V to 0.003 V
[POWER_clamp]
-1.8V     842.3mA    869.2mA    912.6mA
-1.073V   123.5mA    130.8mA    128.8mA
-1.036V   94.69mA    102.8mA    96.31mA
-1V       70.7mA     79.63mA    69.41mA
-963.6mV  50.3mA     59.44mA    47.21mA
-927.3mV  33.48mA    42.27mA    29.73mA
-890.9mV  23.56mA    30.73mA    21mA
-818.2mV  10.72mA    13.8mA     11.42mA
-709.1mV  5.624mA    4.312mA    7.236mA
-527.3mV  1.606mA    1.01mA     1.915mA
-381.8mV  142.3uA    117.5uA    127.8uA
1.764V    -143.5uA   -80.17uA   -225.9uA
[Pulldown]
-1.8V     -10.49mA   -6.992mA   -6.878mA
-1.145V   -14.77mA   -9.642mA   -12.54mA
-872.7mV  -19.18mA   -11.58mA   -26.88mA
-600mV    -17.64mA   -11.15mA   -24.61mA
1.636V    48.04mA    29.95mA    67.37mA
2.073V    58.21mA    34.18mA    83.2mA
2.291V    61.28mA    32.65mA    90.41mA
2.455V    60.33mA    29.78mA    94.55mA
2.618V    57.37mA    25.94mA    94.82mA
2.782V    51.43mA    22.55mA    92.84mA
3.055V    43.59mA    17.92mA    79.47mA
3.545V    32.43mA    11.97mA    65.61mA
[Pullup]
-1.8V     15.27mA    9.71mA     21.85mA
-818.2mV  16.05mA    10.88mA    21.94mA
-490.9mV  13.72mA    9.223mA    18.66mA
1.036V    -30.45mA   -20.11mA   -41.15mA
2.018V    -57.22mA   -36.91mA   -78.08mA
2.345V    -64.63mA   -38.19mA   -89.73mA
2.618V    -65.01mA   -33.11mA   -96.69mA
2.782V    -59.96mA   -28.87mA   -97.07mA
2.836V    -57.32mA   -27.51mA   -95.25mA
3V        -50.25mA   -24.09mA   -80.87mA
3.218V    -42.03mA   -20.43mA   -58.16mA
3.545V    -34.78mA   -15.26mA   -32.29mA
[GND_clamp]
-1.8V     -697.8mA   -553.3mA   -1.259A
-1.145V   -140.7mA   -131.7mA   -248.4mA
-1.109V   -115.2mA   -111.7mA   -203.4mA
-1.036V   -69.7mA    -74.11mA   -126mA
-1V       -53.27mA   -58.3mA    -96.66mA
-927.3mV  -28.09mA   -31.91mA   -45.55mA
-890.9mV  -20.27mA   -23.39mA   -28.66mA
-854.5mV  -14.02mA   -16.45mA   -16.77mA
-818.2mV  -9.337mA   -11.08mA   -9.893mA
-672.7mV  -3.466mA   -3.226mA   -3.973mA
-18.18mV  0A         0A         0A
3.6V      0A         0A         0A
[Ramp]
dV/dt_f 0.72575094/0.29709153n 0.53575032/0.6754154n 0.88788803/0.16188157n
dV/dt_r 0.68045504/0.22628476n 0.51235199/0.47397161n 0.81152502/0.13187394n
R_load = 50
[Rising Waveform]
R_fixture = 50
V_fixture = 1.8
V_fixture_min = 1.62
V_fixture_max = 1.98
109.1ps   703.3mV    810mV      630.9mV
146ps     703.3mV    810mV      793mV
234.8ps   703.3mV    810mV      1.629V
324.2ps   702.8mV    810mV      1.89V
530.8ps   758.1mV    810mV      1.951V
686.5ps   1.425V     810mV      1.964V
859.6ps   1.722V     810mV      1.972V
1.455ns   1.786V     824.9mV    1.979V
1.776ns   1.793V     1.421V     1.98V
2.467ns   1.8V       1.62V      1.98V
[Rising Waveform]
R_fixture = 50
V_fixture = 0
V_fixture_min = 0
V_fixture_max = 0
160ps     2.802mV    1.768mV    3.967mV
237.1ps   2.822mV    1.771mV    671mV
305.3ps   2.349mV    1.77mV     1.004V
504.5ps   -14.32mV   1.767mV    1.253V
624ps     -27.37mV   1.768mV    1.283V
870.3ps   799.7mV    1.767mV    1.306V
1.139ns   999mV      1.465mV    1.315V
1.688ns   1.058V     -46.58mV   1.321V
2.315ns   1.07V      630.8mV    1.324V
3.481ns   1.078V     802.6mV    1.324V
[Falling Waveform]
R_fixture = 50
V_fixture = 1.8
V_fixture_min = 1.62
V_fixture_max = 1.98
113.1ps   1.8V       1.62V      1.98V
194.2ps   1.803V     1.62V      1.419V
303.3ps   1.828V     1.62V      906.3mV
444.5ps   1.915V     1.62V      694.1mV
532.2ps   1.815V     1.62V      670.1mV
859.6ps   986.1mV    1.62V      643.2mV
1.024ns   798.2mV    1.629V     639.5mV
1.503ns   723.3mV    1.678V     634.4mV
2.465ns   709.4mV    955.4mV    632.1mV
3.338ns   703.3mV    810mV      630.9mV
[Falling Waveform]
R_fixture = 50
V_fixture = 0
V_fixture_min = 0
V_fixture_max = 0
0s        1.078V     802.6mV    1.324V
139ps     1.078V     802.6mV    486.5mV
231.2ps   1.086V     802.6mV    168mV
304.8ps   1.076V     802.6mV    67.07mV
379.2ps   977.5mV    802.6mV    44.19mV
540.8ps   333mV      802.6mV    24.9mV
773.5ps   73.24mV    802.6mV    15.06mV
1.292ns   17.34mV    770.9mV    6.917mV
1.671ns   11.72mV    167.4mV    4.953mV
2.346ns   2.802mV    1.768mV    3.967mV
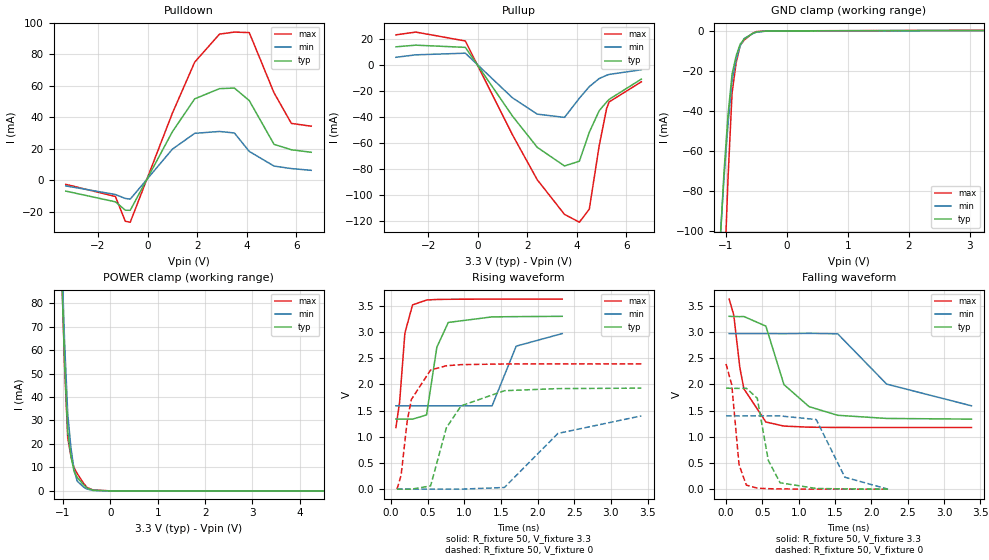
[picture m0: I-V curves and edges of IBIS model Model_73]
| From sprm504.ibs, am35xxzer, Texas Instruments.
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| Model based on original model for BC1833DV40CTPBFHP18LL_7LM_X50
|   Sub model LL_7LM_X50_PD_ON_3P3
[model]   Model_73
|[Description]  3.3V-I/O-PD-X
|[Input Load]   PD
|[Output Drive]
|Voltage   3.3V
|Mode   I/O
Model_type   I/O
Polarity   Non-Inverting
Enable   Active-Low
Vinl =  0.8V
Vinh =  2V
Cref =  15pF
Rref =  100.0000M
Vref =  0V
Vmeas =  1.65
C_comp   1.943144p   1.721292p   2.064363p
[Model Spec]
Vinl   0.8V   0.8V   0.8V
Vinh   2V   2V   2V
[Temperature Range]   25   125   -40
[Voltage Range]   3.3   2.97   3.63
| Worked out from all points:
|   slope of the pulldown table from 0 to 0.495 V, typ, clamps not added: 31.5 ohm
|   slope of the pullup table from 0 to 0.495 V, typ, clamps not added: 34.6 ohm
|   GND clamp passes 1 mA (typ) near -0.54 V on its own axis
|   POWER clamp passes 1 mA (typ) near -0.47 V on its own axis
|   rising waveform, R_fixture 50, V_fixture 3.3: 20-80 % time 136ps typ, 202ps min, 89.2ps max; typ from 1.34 V to 3.3 V
|   rising waveform, R_fixture 50, V_fixture 0: 20-80 % time 312ps typ, 712ps min, 174ps max; typ from 0 V to 1.93 V
|   falling waveform, R_fixture 50, V_fixture 3.3: 20-80 % time 376ps typ, 808ps min, 190ps max; typ from 3.3 V to 1.34 V
|   falling waveform, R_fixture 50, V_fixture 0: 20-80 % time 158ps typ, 244ps min, 92.3ps max; typ from 1.93 V to 0 V
[POWER_clamp]
-3.3V     2.432A     2.868A     2.62A
-1.033V   95.18mA    103.3mA    97.04mA
-966.7mV  55.02mA    63.43mA    53.21mA
-900mV    25.31mA    32.8mA     22.52mA
-833.3mV  14.85mA    18.49mA    14.91mA
-766.7mV  8.321mA    8.944mA    9.874mA
-700mV    5.714mA    4.176mA    7.411mA
-566.7mV  2.625mA    1.655mA    3.318mA
-500mV    1.329mA    834.5uA    1.58mA
-366.7mV  289.8uA    193.7uA    370.6uA
33.33mV   0A         0A         0A
6.6V      0A         0A         0A
[Pulldown]
-3.3V     -6.73mA    -3.436mA   -2.446mA
-1.3V     -13.54mA   -8.893mA   -10.15mA
-900mV    -18.86mA   -11.4mA    -25.9mA
-700mV    -18.91mA   -11.82mA   -26.47mA
1V        30.96mA    19.89mA    42.74mA
1.9V      51.83mA    29.94mA    75.14mA
2.9V      58.3mA     31.12mA    92.92mA
3.5V      58.67mA    30.17mA    94.2mA
4.1V      50.73mA    18.46mA    93.88mA
5.1V      22.94mA    9.149mA    55.64mA
5.8V      19.5mA     7.56mA     36.23mA
6.6V      17.91mA    6.449mA    34.47mA
[Pullup]
-3.3V     13.88mA    5.843mA    23.08mA
-2.5V     15.16mA    7.729mA    25.2mA
-500mV    13.47mA    8.99mA     18.38mA
1.4V      -39.27mA   -25.27mA   -53.66mA
2.4V      -63.29mA   -37.81mA   -88.19mA
3.5V      -77.61mA   -40.33mA   -114.8mA
4.1V      -73.95mA   -25.59mA   -120.8mA
4.5V      -51.77mA   -16.71mA   -110.8mA
4.9V      -35.15mA   -10.47mA   -62.03mA
5.2V      -28.48mA   -7.948mA   -33.38mA
5.3V      -26.46mA   -7.311mA   -28.43mA
6.6V      -10.91mA   -3.736mA   -12.96mA
[GND_clamp]
-3.3V     -2.048A    -1.805A    -3.667A
-1.1V     -108.6mA   -106.5mA   -191.4mA
-1.033V   -71.11mA   -74.03mA   -127.7mA
-966.7mV  -42.16mA   -46.82mA   -74.25mA
-900mV    -21.74mA   -24.87mA   -31.11mA
-833.3mV  -12.59mA   -14.46mA   -16.09mA
-766.7mV  -6.705mA   -7.466mA   -7.261mA
-700mV    -4.083mA   -3.879mA   -4.614mA
-566.7mV  -1.424mA   -1.483mA   -1.356mA
-500mV    -523uA     -696.8uA   -399.5uA
-300mV    -31.01uA   -34.87uA   -39.82uA
3.233V    152.3uA    97.89uA    242.6uA
[Ramp]
dV/dt_f   1.189224/0.37472256n 0.84328197/0.79906959n  1.4745668/0.18915717n
dV/dt_r  1.1648651/0.30869525n 0.84528773/0.7023728n  1.4414378/0.17300817n
R_load = 50
[Rising Waveform]
R_fixture = 50
V_fixture = 3.3
V_fixture_min = 2.97
V_fixture_max = 3.63
67.48ps   1.336V     1.59V      1.176V
118ps     1.336V     1.59V      1.665V
189.7ps   1.336V     1.59V      2.977V
294ps     1.335V     1.59V      3.514V
485.2ps   1.416V     1.59V      3.608V
625.6ps   2.707V     1.59V      3.618V
781.5ps   3.18V      1.59V      3.622V
1.379ns   3.286V     1.59V      3.625V
1.708ns   3.291V     2.728V     3.625V
2.336ns   3.297V     2.968V     3.626V
[Rising Waveform]
R_fixture = 50
V_fixture = 0
V_fixture_min = 0
V_fixture_max = 0
81.84ps   8.544nV    120nV      4.061nV
137.8ps   -98.76nV   498.4nV    261.4mV
220.9ps   16.34uV    29.36nV    1.296V
277.9ps   -281.2uV   -77.39nV   1.711V
540.4ps   61.65mV    -35.11nV   2.273V
755.9ps   1.171V     63.55nV    2.354V
956.1ps   1.589V     14.82uV    2.375V
1.547ns   1.878V     32.16mV    2.388V
2.277ns   1.918V     1.063V     2.389V
3.415ns   1.927V     1.398V     2.389V
[Falling Waveform]
R_fixture = 50
V_fixture = 3.3
V_fixture_min = 2.97
V_fixture_max = 3.63
42.71ps   3.297V     2.968V     3.626V
105.8ps   3.293V     2.968V     3.324V
190.1ps   3.291V     2.968V     2.316V
245.5ps   3.293V     2.968V     1.914V
547.9ps   3.11V      2.968V     1.281V
796.2ps   1.995V     2.965V     1.203V
1.142ns   1.574V     2.972V     1.182V
1.536ns   1.409V     2.963V     1.177V
2.209ns   1.349V     2.004V     1.176V
3.376ns   1.336V     1.59V      1.176V
[Falling Waveform]
R_fixture = 50
V_fixture = 0
V_fixture_min = 0
V_fixture_max = 0
0s        1.927V     1.398V     2.389V
78.66ps   1.924V     1.398V     1.988V
178.5ps   1.922V     1.398V     469.7mV
278.5ps   1.925V     1.398V     77.32mV
429.4ps   1.735V     1.398V     19.53mV
580.7ps   550.4mV    1.397V     9.396mV
743.5ps   122mV      1.397V     4.382mV
1.24ns    13.04mV    1.328V     276.7uV
1.635ns   5.194mV    227.1mV    30.02uV
2.228ns   8.544nV    120nV      4.061nV
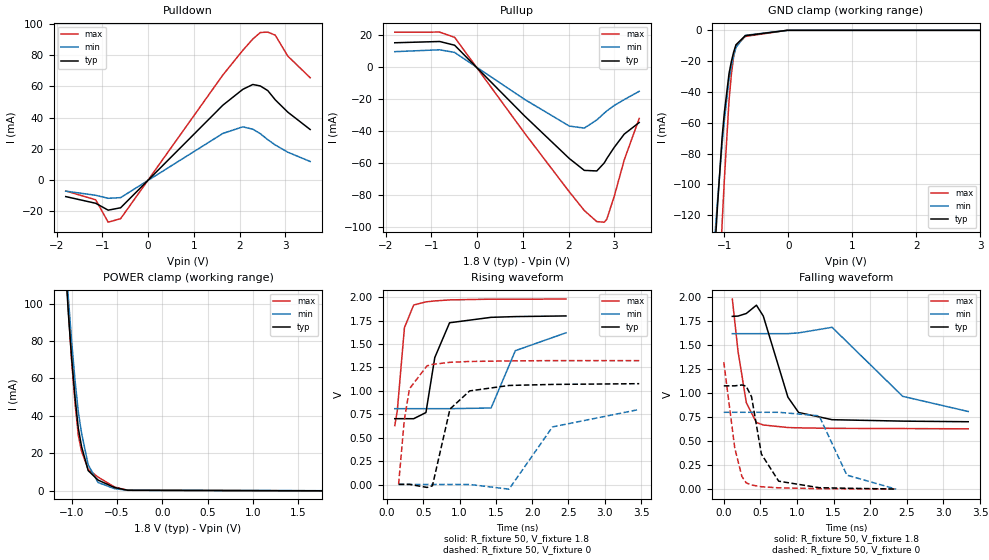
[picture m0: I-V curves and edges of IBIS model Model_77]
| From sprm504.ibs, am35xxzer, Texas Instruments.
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| Model based on original model for BC1833DV40CTPBFZP18LL_7LM
|   Sub model ZP18LL_7LM_PU_ON_1P8
[model]   Model_77
|[Description]  1.8V-I/O-PU-X
|[Input Load]   PU
|[Output Drive]
|Voltage   1.8V
|Mode   I/O
Model_type   I/O
Polarity   Non-Inverting
Enable   Active-Low
Vinl =  0.63V
Vinh =  1.17V
Cref =  15pF
Rref =  100.0000M
Vref =  0V
Vmeas =  0.9
C_comp   2.232809p   2.073051p   2.295852p
[Model Spec]
Vinl   0.63V   0.567V   0.693V
Vinh   1.17V   1.053V   1.287V
[Temperature Range]   25   125   -40
[Voltage Range]   1.8   1.62   1.98
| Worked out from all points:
|   slope of the pulldown table from 0 to 0.27 V, typ, clamps not added: 31.5 ohm
|   slope of the pullup table from 0 to 0.27 V, typ, clamps not added: 33.5 ohm
|   GND clamp passes 1 mA (typ) near -0.53 V on its own axis
|   POWER clamp passes 1 mA (typ) near -0.49 V on its own axis
|   rising waveform, R_fixture 50, V_fixture 1.8: 20-80 % time 167ps typ, 245ps min, 94.2ps max; typ from 0.703 V to 1.8 V
|   rising waveform, R_fixture 50, V_fixture 0: 20-80 % time 225ps typ, 476ps min, 130ps max; typ from 0.003 V to 1.08 V
|   falling waveform, R_fixture 50, V_fixture 1.8: 20-80 % time 282ps typ, 644ps min, 154ps max; typ from 1.8 V to 0.703 V
|   falling waveform, R_fixture 50, V_fixture 0: 20-80 % time 207ps typ, 247ps min, 145ps max; typ from 1.08 V to 0.003 V
[POWER_clamp]
-1.8V     842.2mA    869.2mA    912.6mA
-1.073V   123.5mA    130.8mA    128.8mA
-1.036V   94.66mA    102.8mA    96.27mA
-1V       70.68mA    79.61mA    69.37mA
-963.6mV  50.27mA    59.42mA    47.18mA
-927.3mV  33.45mA    42.25mA    29.69mA
-890.9mV  23.53mA    30.71mA    20.96mA
-818.2mV  10.69mA    13.79mA    11.39mA
-709.1mV  5.603mA    4.298mA    7.212mA
-527.3mV  1.593mA    1.002mA    1.9mA
-381.8mV  140.2uA    115.9uA    126.2uA
1.764V    -143.5uA   -80.18uA   -225.9uA
[Pulldown]
-1.8V     -10.48mA   -6.986mA   -6.871mA
-1.145V   -14.76mA   -9.635mA   -12.53mA
-872.7mV  -19.16mA   -11.57mA   -26.86mA
-600mV    -17.63mA   -11.14mA   -24.6mA
1.636V    48.02mA    29.94mA    67.34mA
2.073V    58.18mA    34.17mA    83.16mA
2.291V    61.26mA    32.65mA    90.37mA
2.455V    60.31mA    29.78mA    94.52mA
2.618V    57.35mA    25.94mA    94.79mA
2.782V    51.42mA    22.55mA    92.8mA
3.055V    43.58mA    17.93mA    79.45mA
3.545V    32.44mA    11.99mA    65.6mA
[Pullup]
-1.8V     15.25mA    9.689mA    21.84mA
-818.2mV  16.04mA    10.87mA    21.92mA
-490.9mV  13.71mA    9.212mA    18.64mA
1.036V    -30.4mA    -20.07mA   -41.09mA
2.018V    -57.1mA    -36.81mA   -77.94mA
2.345V    -64.48mA   -38.06mA   -89.56mA
2.618V    -64.84mA   -32.95mA   -96.49mA
2.782V    -59.78mA   -28.7mA    -96.85mA
2.836V    -57.13mA   -27.34mA   -95.03mA
3V        -50.06mA   -23.92mA   -80.64mA
3.218V    -41.82mA   -20.26mA   -57.92mA
3.545V    -34.58mA   -15.09mA   -32.06mA
[GND_clamp]
-1.8V     -697.8mA   -553.3mA   -1.259A
-1.145V   -140.7mA   -131.7mA   -248.4mA
-1.109V   -115.2mA   -111.7mA   -203.4mA
-1.036V   -69.7mA    -74.11mA   -126mA
-1V       -53.27mA   -58.3mA    -96.66mA
-927.3mV  -28.09mA   -31.91mA   -45.55mA
-890.9mV  -20.27mA   -23.4mA    -28.66mA
-854.5mV  -14.02mA   -16.45mA   -16.78mA
-818.2mV  -9.341mA   -11.08mA   -9.899mA
-672.7mV  -3.472mA   -3.23mA    -3.981mA
-18.18mV  0A         0A         0A
3.6V      0A         0A         0A
[Ramp]
dV/dt_f  0.7268408/0.2957999n 0.53624358/0.67575712n 0.89027333/0.16178538n
dV/dt_r 0.67751201/0.22456839n 0.51230586/0.47223533n 0.81060452/0.13073926n
R_load = 50
[Rising Waveform]
R_fixture = 50
V_fixture = 1.8
V_fixture_min = 1.62
V_fixture_max = 1.98
106.2ps   703.5mV    810.1mV    629.7mV
140.7ps   703.5mV    810.1mV    785.8mV
239.4ps   703.5mV    810.1mV    1.674V
366.3ps   703mV      810.1mV    1.916V
535.8ps   768.8mV    810.1mV    1.95V
657.7ps   1.356V     810.1mV    1.96V
861.6ps   1.727V     810.1mV    1.971V
1.434ns   1.785V     817.6mV    1.979V
1.768ns   1.793V     1.429V     1.979V
2.466ns   1.8V       1.62V      1.98V
[Rising Waveform]
R_fixture = 50
V_fixture = 0
V_fixture_min = 0
V_fixture_max = 0
159.1ps   2.803mV    1.768mV    3.968mV
237.1ps   2.825mV    1.771mV    685.8mV
308.9ps   2.362mV    1.77mV     1.023V
551.7ps   -30.1mV    1.768mV    1.268V
625.2ps   -12.95mV   1.768mV    1.283V
866.8ps   806mV      1.766mV    1.305V
1.138ns   999.7mV    1.477mV    1.314V
1.681ns   1.058V     -48.77mV   1.32V
2.28ns    1.069V     615.7mV    1.323V
3.475ns   1.077V     801.8mV    1.323V
[Falling Waveform]
R_fixture = 50
V_fixture = 1.8
V_fixture_min = 1.62
V_fixture_max = 1.98
116.6ps   1.8V       1.62V      1.98V
194.4ps   1.803V     1.62V      1.437V
307.9ps   1.83V      1.62V      900.6mV
445.8ps   1.916V     1.62V      695mV
539.5ps   1.803V     1.62V      669.7mV
875.7ps   959.1mV    1.62V      643.1mV
1.022ns   799.4mV    1.628V     639.8mV
1.479ns   724.7mV    1.686V     634.8mV
2.443ns   709.7mV    967.9mV    632.3mV
3.338ns   703.5mV    810.1mV    629.7mV
[Falling Waveform]
R_fixture = 50
V_fixture = 0
V_fixture_min = 0
V_fixture_max = 0
0s        1.077V     801.8mV    1.323V
149.9ps   1.077V     801.8mV    429.2mV
247.2ps   1.086V     801.8mV    133.5mV
305.4ps   1.073V     801.8mV    67.68mV
379.2ps   963.4mV    801.8mV    44.76mV
513.8ps   366.4mV    801.8mV    27.22mV
749.7ps   84.96mV    801.8mV    15.74mV
1.302ns   17.1mV     765mV      6.799mV
1.681ns   11.57mV    147.9mV    4.901mV
2.354ns   2.803mV    1.768mV    3.968mV
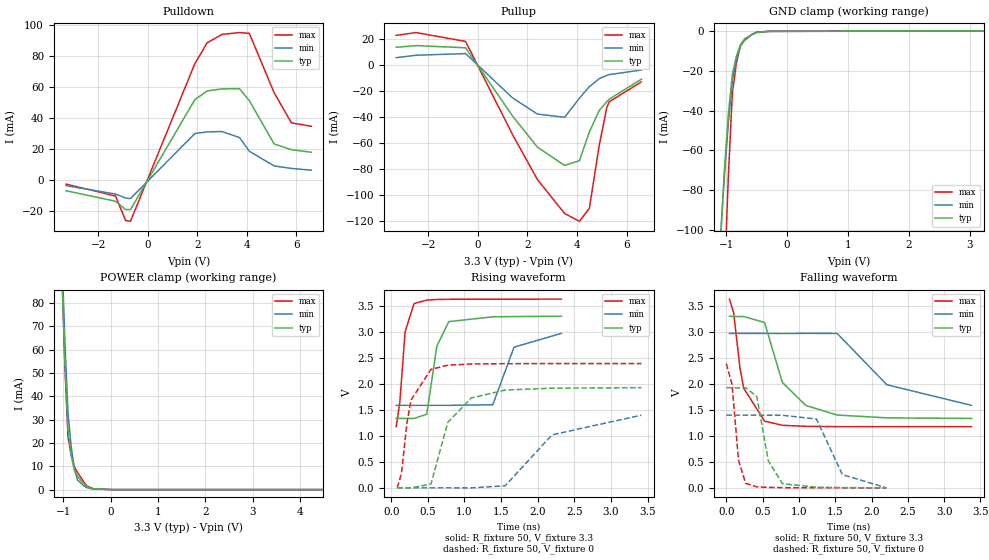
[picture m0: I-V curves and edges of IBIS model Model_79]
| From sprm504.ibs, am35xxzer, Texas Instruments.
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| Model based on original model for BC1833DV40CTPBFZP18LL_7LM
|   Sub model ZP18LL_7LM_PD_ON_3P3
[model]   Model_79
|[Description]  3.3V-I/O-PD-X
|[Input Load]   PD
|[Output Drive]
|Voltage   3.3V
|Mode   I/O
Model_type   I/O
Polarity   Non-Inverting
Enable   Active-Low
Vinl =  0.8V
Vinh =  2V
Cref =  15pF
Rref =  100.0000M
Vref =  0V
Vmeas =  1.65
C_comp   1.943144p   1.721292p   2.064363p
[Model Spec]
Vinl   0.8V   0.8V   0.8V
Vinh   2V   2V   2V
[Temperature Range]   25   125   -40
[Voltage Range]   3.3   2.97   3.63
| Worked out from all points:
|   slope of the pulldown table from 0 to 0.495 V, typ, clamps not added: 31.5 ohm
|   slope of the pullup table from 0 to 0.495 V, typ, clamps not added: 34.6 ohm
|   GND clamp passes 1 mA (typ) near -0.54 V on its own axis
|   POWER clamp passes 1 mA (typ) near -0.47 V on its own axis
|   rising waveform, R_fixture 50, V_fixture 3.3: 20-80 % time 130ps typ, 192ps min, 86.8ps max; typ from 1.33 V to 3.3 V
|   rising waveform, R_fixture 50, V_fixture 0: 20-80 % time 304ps typ, 701ps min, 173ps max; typ from 0 V to 1.93 V
|   falling waveform, R_fixture 50, V_fixture 3.3: 20-80 % time 361ps typ, 773ps min, 181ps max; typ from 3.3 V to 1.33 V
|   falling waveform, R_fixture 50, V_fixture 0: 20-80 % time 150ps typ, 233ps min, 88.8ps max; typ from 1.93 V to 0 V
[POWER_clamp]
-3.3V     2.432A     2.868A     2.62A
-1.033V   95.16mA    103.3mA    97mA
-966.7mV  55mA       63.41mA    53.17mA
-900mV    25.28mA    32.79mA    22.49mA
-833.3mV  14.83mA    18.47mA    14.88mA
-766.7mV  8.299mA    8.929mA    9.847mA
-700mV    5.694mA    4.162mA    7.387mA
-566.7mV  2.611mA    1.646mA    3.301mA
-500mV    1.319mA    827.8uA    1.568mA
-366.7mV  287.8uA    192.2uA    368.8uA
33.33mV   0A         0A         0A
6.6V      0A         0A         0A
[Pulldown]
-3.3V     -6.725mA   -3.434mA   -2.443mA
-1.3V     -13.53mA   -8.888mA   -10.15mA
-900mV    -18.85mA   -11.39mA   -25.88mA
-700mV    -18.89mA   -11.82mA   -26.46mA
1.9V      52.07mA    30.2mA     75.32mA
2.4V      57.75mA    31.28mA    88.86mA
3V        59.01mA    31.49mA    94.2mA
3.7V      59.19mA    27.61mA    95.39mA
4.1V      51.39mA    18.8mA     94.89mA
5.1V      23.52mA    9.29mA     56.6mA
5.8V      19.77mA    7.67mA     37.13mA
6.6V      18.13mA    6.544mA    34.86mA
[Pullup]
-3.3V     13.83mA    5.807mA    23.01mA
-2.5V     15.14mA    7.704mA    25.18mA
-500mV    13.45mA    8.979mA    18.37mA
1.4V      -39.2mA    -25.2mA    -53.56mA
2.4V      -63.13mA   -37.64mA   -88mA
3.5V      -77.24mA   -40.1mA    -114.3mA
4.1V      -73.54mA   -25.36mA   -120.3mA
4.5V      -51.37mA   -16.52mA   -110.3mA
4.9V      -34.86mA   -10.34mA   -61.5mA
5.2V      -28.21mA   -7.863mA   -32.95mA
5.3V      -26.19mA   -7.237mA   -28.18mA
6.6V      -10.79mA   -3.71mA    -12.85mA
[GND_clamp]
-3.3V     -2.048A    -1.805A    -3.667A
-1.1V     -108.6mA   -106.5mA   -191.4mA
-1.033V   -71.11mA   -74.03mA   -127.7mA
-966.7mV  -42.17mA   -46.82mA   -74.25mA
-900mV    -21.74mA   -24.87mA   -31.11mA
-833.3mV  -12.59mA   -14.47mA   -16.1mA
-766.7mV  -6.71mA    -7.469mA   -7.269mA
-700mV    -4.089mA   -3.883mA   -4.623mA
-566.7mV  -1.428mA   -1.487mA   -1.361mA
-500mV    -525.6uA   -699.5uA   -401.5uA
-300mV    -31.04uA   -34.98uA   -39.83uA
3.233V    152.3uA    97.64uA    242.6uA
[Ramp]
dV/dt_f  1.1903282/0.35835692n 0.84570533/0.75948841n  1.4749314/0.18091593n
dV/dt_r  1.1633385/0.30312571n 0.84438981/0.6951835n  1.4405338/0.1698763n
R_load = 50
[Rising Waveform]
R_fixture = 50
V_fixture = 3.3
V_fixture_min = 2.97
V_fixture_max = 3.63
67.88ps   1.334V     1.585V     1.175V
116.7ps   1.334V     1.585V     1.639V
189.5ps   1.334V     1.585V     2.998V
311.4ps   1.333V     1.585V     3.541V
485.1ps   1.415V     1.585V     3.608V
623.1ps   2.725V     1.585V     3.619V
787ps     3.194V     1.585V     3.623V
1.387ns   3.286V     1.597V     3.625V
1.677ns   3.291V     2.703V     3.625V
2.323ns   3.297V     2.968V     3.626V
[Rising Waveform]
R_fixture = 50
V_fixture = 0
V_fixture_min = 0
V_fixture_max = 0
82.26ps   8.38nV     117.7nV    4.053nV
139.2ps   -224.6nV   500.5nV    271.7mV
214ps     20.04uV    24.93nV    1.243V
270.2ps   -224.5uV   -93.95nV   1.686V
542.1ps   72.55mV    -54.2nV    2.276V
772.7ps   1.257V     -28.63nV   2.356V
1.093ns   1.727V     -438.4uV   2.38V
1.556ns   1.879V     39.32mV    2.386V
2.196ns   1.915V     1.018V     2.387V
3.416ns   1.925V     1.396V     2.387V
[Falling Waveform]
R_fixture = 50
V_fixture = 3.3
V_fixture_min = 2.97
V_fixture_max = 3.63
43.08ps   3.297V     2.968V     3.626V
100.9ps   3.293V     2.968V     3.364V
188.4ps   3.291V     2.968V     2.295V
239.7ps   3.292V     2.968V     1.913V
526.5ps   3.177V     2.968V     1.282V
771.5ps   2.026V     2.965V     1.202V
1.095ns   1.583V     2.969V     1.182V
1.526ns   1.399V     2.967V     1.176V
2.21ns    1.345V     1.981V     1.175V
3.376ns   1.334V     1.585V     1.175V
[Falling Waveform]
R_fixture = 50
V_fixture = 0
V_fixture_min = 0
V_fixture_max = 0
0s        1.925V     1.396V     2.387V
78.36ps   1.922V     1.396V     1.988V
167.8ps   1.921V     1.396V     530.7mV
266ps     1.924V     1.396V     85.64mV
419.9ps   1.755V     1.396V     20mV
578.4ps   516.2mV    1.395V     9.362mV
773.6ps   78.55mV    1.394V     3.52mV
1.241ns   12.87mV    1.323V     253.8uV
1.598ns   5.405mV    255.1mV    33.19uV
2.204ns   8.38nV     117.7nV    4.053nV
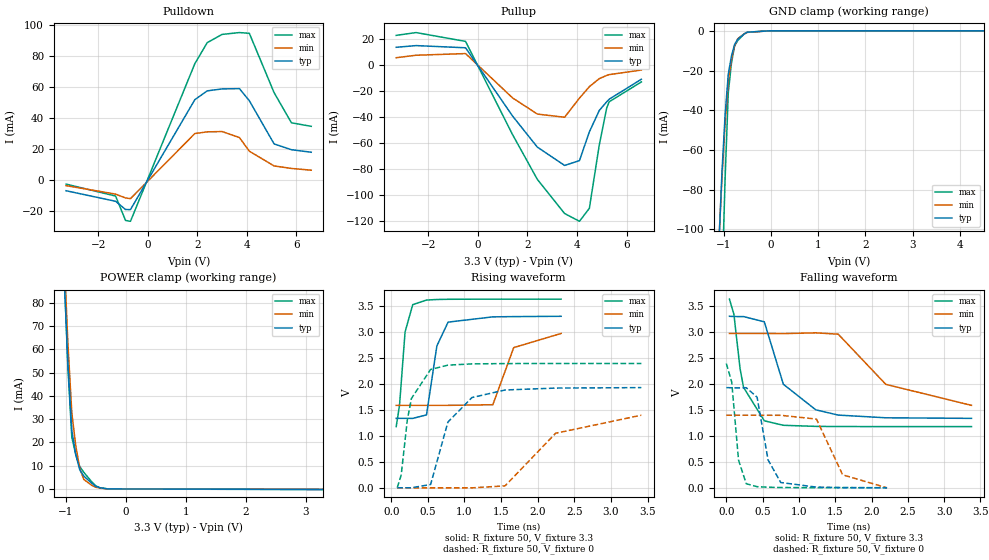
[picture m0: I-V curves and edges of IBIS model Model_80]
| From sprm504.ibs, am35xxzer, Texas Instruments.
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| Model based on original model for BC1833DV40CTPBFZP18LL_7LM
|   Sub model ZP18LL_7LM_PU_ON_3P3
[model]   Model_80
|[Description]  3.3V-I/O-PU-X
|[Input Load]   PU
|[Output Drive]
|Voltage   3.3V
|Mode   I/O
Model_type   I/O
Polarity   Non-Inverting
Enable   Active-Low
Vinl =  0.8V
Vinh =  2V
Cref =  15pF
Rref =  100.0000M
Vref =  0V
Vmeas =  1.65
C_comp   1.943144p   1.721292p   2.064363p
[Model Spec]
Vinl   0.8V   0.8V   0.8V
Vinh   2V   2V   2V
[Temperature Range]   25   125   -40
[Voltage Range]   3.3   2.97   3.63
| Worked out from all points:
|   slope of the pulldown table from 0 to 0.495 V, typ, clamps not added: 31.5 ohm
|   slope of the pullup table from 0 to 0.495 V, typ, clamps not added: 34.6 ohm
|   GND clamp passes 1 mA (typ) near -0.52 V on its own axis
|   POWER clamp passes 1 mA (typ) near -0.48 V on its own axis
|   rising waveform, R_fixture 50, V_fixture 3.3: 20-80 % time 130ps typ, 191ps min, 86.2ps max; typ from 1.34 V to 3.3 V
|   rising waveform, R_fixture 50, V_fixture 0: 20-80 % time 310ps typ, 698ps min, 170ps max; typ from 0.003 V to 1.93 V
|   falling waveform, R_fixture 50, V_fixture 3.3: 20-80 % time 364ps typ, 782ps min, 182ps max; typ from 3.3 V to 1.34 V
|   falling waveform, R_fixture 50, V_fixture 0: 20-80 % time 151ps typ, 235ps min, 89.3ps max; typ from 1.93 V to 0.003 V
[POWER_clamp]
-3.3V     2.432A     2.868A     2.62A
-1.033V   95.06mA    103.2mA    96.82mA
-966.7mV  54.89mA    63.36mA    52.99mA
-900mV    25.17mA    32.73mA    22.29mA
-833.3mV  14.71mA    18.41mA    14.68mA
-766.7mV  8.177mA    8.865mA    9.637mA
-700mV    5.568mA    4.096mA    7.172mA
-566.7mV  2.478mA    1.576mA    3.075mA
-500mV    1.182mA    756.3uA    1.336mA
-433.3mV  529.8uA    361.2uA    561.7uA
-300mV    28.38uA    26.91uA    30.81uA
3.3V      -177.5uA   -143.5uA   -277.3uA
[Pulldown]
-3.3V     -6.725mA   -3.434mA   -2.443mA
-1.3V     -13.53mA   -8.888mA   -10.15mA
-900mV    -18.85mA   -11.39mA   -25.88mA
-700mV    -18.89mA   -11.82mA   -26.45mA
1.9V      52.07mA    30.2mA     75.33mA
2.4V      57.75mA    31.28mA    88.86mA
3V        59.01mA    31.49mA    94.2mA
3.7V      59.19mA    27.61mA    95.38mA
4.1V      51.39mA    18.8mA     94.89mA
5.1V      23.52mA    9.29mA     56.6mA
5.8V      19.77mA    7.67mA     37.13mA
6.6V      18.13mA    6.544mA    34.86mA
[Pullup]
-3.3V     13.83mA    5.807mA    23.01mA
-2.5V     15.14mA    7.704mA    25.18mA
-500mV    13.45mA    8.979mA    18.37mA
1.4V      -39.2mA    -25.2mA    -53.56mA
2.4V      -63.13mA   -37.64mA   -88mA
3.5V      -77.24mA   -40.1mA    -114.3mA
4.1V      -73.54mA   -25.36mA   -120.3mA
4.5V      -51.37mA   -16.52mA   -110.3mA
4.9V      -34.86mA   -10.34mA   -61.5mA
5.2V      -28.21mA   -7.863mA   -32.95mA
5.3V      -26.19mA   -7.237mA   -28.18mA
6.6V      -10.79mA   -3.71mA    -12.85mA
[GND_clamp]
-3.3V     -2.048A    -1.805A    -3.667A
-1.1V     -108.7mA   -106.5mA   -191.5mA
-1.033V   -71.21mA   -74.08mA   -127.8mA
-966.7mV  -42.29mA   -46.88mA   -74.43mA
-900mV    -21.88mA   -24.94mA   -31.36mA
-833.3mV  -12.76mA   -14.54mA   -16.38mA
-766.7mV  -6.884mA   -7.551mA   -7.57mA
-700mV    -4.265mA   -3.97mA    -4.926mA
-566.7mV  -1.605mA   -1.575mA   -1.664mA
-500mV    -702.9uA   -787.9uA   -705.8uA
-33.33mV  0A         0A         0A
6.6V      0A         0A         0A
[Ramp]
dV/dt_f  1.1901071/0.35921065n 0.84553891/0.76039339n  1.4745933/0.18160445n
dV/dt_r  1.1635001/0.30233591n 0.84456841/0.69405785n   1.440719/0.1692509n
R_load = 50
[Rising Waveform]
R_fixture = 50
V_fixture = 3.3
V_fixture_min = 2.97
V_fixture_max = 3.63
67.6ps    1.338V     1.588V     1.18V
112.5ps   1.338V     1.588V     1.585V
188.6ps   1.338V     1.588V     2.998V
293.2ps   1.337V     1.588V     3.524V
481.1ps   1.404V     1.588V     3.612V
622.9ps   2.731V     1.588V     3.623V
776.2ps   3.188V     1.588V     3.627V
1.387ns   3.289V     1.6V       3.63V
1.672ns   3.294V     2.698V     3.63V
2.319ns   3.3V       2.97V      3.63V
[Rising Waveform]
R_fixture = 50
V_fixture = 0
V_fixture_min = 0
V_fixture_max = 0
81.99ps   3.383mV    2.143mV    4.748mV
135.7ps   3.383mV    2.144mV    249.6mV
218.8ps   3.408mV    2.143mV    1.304V
275ps     3.081mV    2.143mV    1.719V
537.4ps   66.36mV    2.143mV    2.278V
773.9ps   1.267V     2.143mV    2.361V
1.102ns   1.738V     1.681mV    2.385V
1.554ns   1.883V     40.14mV    2.391V
2.244ns   1.92V      1.051V     2.393V
3.415ns   1.929V     1.399V     2.393V
[Falling Waveform]
R_fixture = 50
V_fixture = 3.3
V_fixture_min = 2.97
V_fixture_max = 3.63
43.01ps   3.3V       2.97V      3.63V
104.2ps   3.296V     2.97V      3.339V
188.8ps   3.294V     2.97V      2.297V
237.2ps   3.295V     2.97V      1.933V
522.9ps   3.194V     2.97V      1.291V
785ps     1.994V     2.967V     1.205V
1.232ns   1.502V     2.982V     1.184V
1.541ns   1.401V     2.956V     1.181V
2.196ns   1.349V     1.992V     1.18V
3.376ns   1.338V     1.588V     1.18V
[Falling Waveform]
R_fixture = 50
V_fixture = 0
V_fixture_min = 0
V_fixture_max = 0
0s        1.929V     1.399V     2.393V
74.14ps   1.926V     1.399V     2.036V
167.8ps   1.924V     1.399V     536.6mV
274.1ps   1.927V     1.399V     81.63mV
423.3ps   1.746V     1.399V     24.75mV
574.7ps   539.9mV    1.398V     14.2mV
749.1ps   105mV      1.397V     8.856mV
1.241ns   16.31mV    1.324V     5.006mV
1.602ns   8.731mV    252.7mV    4.783mV
2.213ns   3.383mV    2.143mV    4.748mV
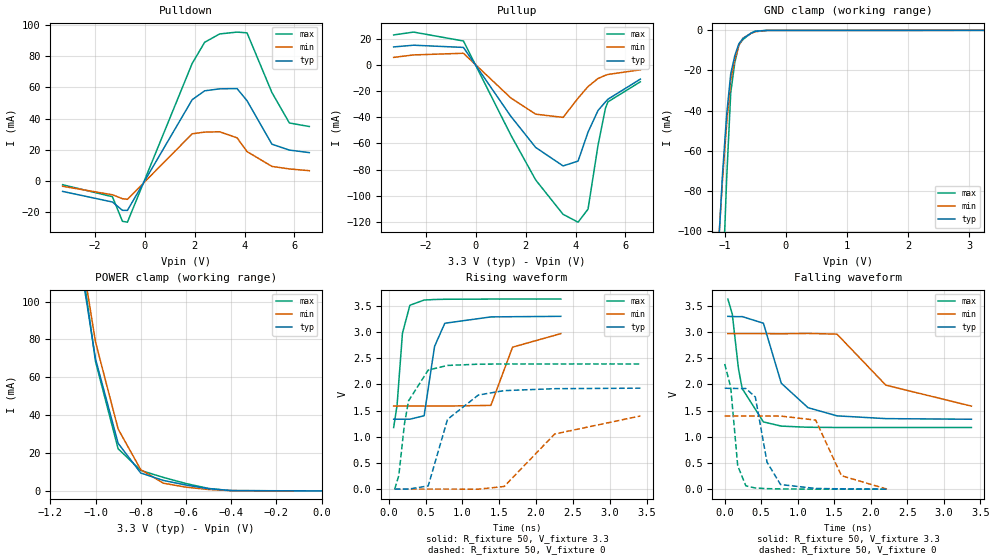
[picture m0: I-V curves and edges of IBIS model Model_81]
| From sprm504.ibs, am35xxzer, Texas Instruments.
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| Model based on original model for BC1833DV40CTPBFZP18LL_7LM
|   Sub model LL_7LM_PD_PU_OFF_3P3
[model]   Model_81
|[Description]  3.3V-I/O-PI-X
|[Input Load]   PI
|[Output Drive]
|Voltage   3.3V
|Mode   I/O
Model_type   I/O
Polarity   Non-Inverting
Enable   Active-Low
Vinl =  0.8V
Vinh =  2V
Cref =  15pF
Rref =  100.0000M
Vref =  0V
Vmeas =  1.65
C_comp   1.943144p   1.721292p   2.064363p
[Model Spec]
Vinl   0.8V   0.8V   0.8V
Vinh   2V   2V   2V
[Temperature Range]   25   125   -40
[Voltage Range]   3.3   2.97   3.63
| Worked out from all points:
|   slope of the pulldown table from 0 to 0.495 V, typ, clamps not added: 31.5 ohm
|   slope of the pullup table from 0 to 0.495 V, typ, clamps not added: 34.6 ohm
|   GND clamp passes 1 mA (typ) near -0.54 V on its own axis
|   POWER clamp passes 1 mA (typ) near -0.48 V on its own axis
|   rising waveform, R_fixture 50, V_fixture 3.3: 20-80 % time 130ps typ, 192ps min, 87.2ps max; typ from 1.33 V to 3.3 V
|   rising waveform, R_fixture 50, V_fixture 0: 20-80 % time 305ps typ, 702ps min, 171ps max; typ from 0 V to 1.93 V
|   falling waveform, R_fixture 50, V_fixture 3.3: 20-80 % time 363ps typ, 767ps min, 183ps max; typ from 3.3 V to 1.33 V
|   falling waveform, R_fixture 50, V_fixture 0: 20-80 % time 151ps typ, 233ps min, 89.3ps max; typ from 1.93 V to 0 V
[POWER_clamp]
-3.3V     2.432A     2.868A     2.62A
-1.067V   120.3mA    127.7mA    125.3mA
-1.033V   95.04mA    103.2mA    96.8mA
-1V       69.74mA    78.67mA    68.31mA
-900mV    25.15mA    32.72mA    22.27mA
-800mV    9.462mA    11.24mA    10.84mA
-700mV    5.548mA    4.085mA    7.139mA
-600mV    3.106mA    1.975mA    3.91mA
-500mV    1.161mA    745uA      1.301mA
-400mV    184uA      153.2uA    143uA
0V        9.359nA    44.03nA    36.65nA
[Pulldown]
-3.3V     -6.725mA   -3.434mA   -2.443mA
-1.3V     -13.53mA   -8.888mA   -10.15mA
-900mV    -18.85mA   -11.39mA   -25.88mA
-700mV    -18.89mA   -11.82mA   -26.46mA
1.9V      52.07mA    30.2mA     75.33mA
2.4V      57.75mA    31.28mA    88.86mA
3V        59.01mA    31.49mA    94.2mA
3.7V      59.19mA    27.61mA    95.39mA
4.1V      51.39mA    18.8mA     94.89mA
5.1V      23.52mA    9.29mA     56.6mA
5.8V      19.77mA    7.67mA     37.13mA
6.6V      18.13mA    6.544mA    34.86mA
[Pullup]
-3.3V     13.83mA    5.807mA    23.01mA
-2.5V     15.14mA    7.704mA    25.18mA
-500mV    13.45mA    8.979mA    18.37mA
1.4V      -39.2mA    -25.2mA    -53.56mA
2.4V      -63.13mA   -37.64mA   -88mA
3.5V      -77.24mA   -40.1mA    -114.3mA
4.1V      -73.54mA   -25.36mA   -120.3mA
4.5V      -51.37mA   -16.52mA   -110.3mA
4.9V      -34.86mA   -10.34mA   -61.5mA
5.2V      -28.21mA   -7.863mA   -32.95mA
5.3V      -26.19mA   -7.237mA   -28.18mA
6.6V      -10.79mA   -3.71mA    -12.85mA
[GND_clamp]
-3.3V     -2.048A    -1.805A    -3.667A
-1.1V     -108.6mA   -106.5mA   -191.4mA
-1.033V   -71.11mA   -74.03mA   -127.7mA
-966.7mV  -42.16mA   -46.82mA   -74.24mA
-900mV    -21.73mA   -24.87mA   -31.1mA
-833.3mV  -12.58mA   -14.46mA   -16.07mA
-766.7mV  -6.691mA   -7.462mA   -7.232mA
-700mV    -4.066mA   -3.873mA   -4.582mA
-566.7mV  -1.404mA   -1.475mA   -1.319mA
-500mV    -501.5uA   -687.7uA   -361.4uA
-300mV    -14.92uA   -26.13uA   -14.52uA
3.233V    8.845nA    14.35uA    33.57nA
[Ramp]
dV/dt_f  1.1914799/0.36013621n 0.84632361/0.76236537n  1.4766768/0.1821205n
dV/dt_r  1.1645983/0.30409239n 0.84507177/0.69687142n  1.4424945/0.17054351n
R_load = 50
[Rising Waveform]
R_fixture = 50
V_fixture = 3.3
V_fixture_min = 2.97
V_fixture_max = 3.63
67.73ps   1.335V     1.586V     1.177V
113.9ps   1.335V     1.586V     1.601V
187.1ps   1.335V     1.586V     2.976V
287.7ps   1.335V     1.586V     3.512V
481.1ps   1.401V     1.586V     3.611V
623ps     2.727V     1.586V     3.622V
761.8ps   3.168V     1.586V     3.626V
1.387ns   3.289V     1.599V     3.63V
1.681ns   3.293V     2.711V     3.63V
2.336ns   3.3V       2.97V      3.63V
[Rising Waveform]
R_fixture = 50
V_fixture = 0
V_fixture_min = 0
V_fixture_max = 0
82.12ps   8.589nV    120.9nV    4.032nV
137.6ps   -211.8nV   517.5nV    258.4mV
213.9ps   20.04uV    28.13nV    1.243V
270.1ps   -224.5uV   -90.74nV   1.686V
536.8ps   61.11mV    -45.24nV   2.274V
798.4ps   1.332V     -99.43nV   2.362V
1.217ns   1.797V     -1.404mV   2.386V
1.567ns   1.881V     49.52mV    2.39V
2.252ns   1.918V     1.052V     2.391V
3.415ns   1.928V     1.397V     2.391V
[Falling Waveform]
R_fixture = 50
V_fixture = 3.3
V_fixture_min = 2.97
V_fixture_max = 3.63
43.1ps    3.3V       2.97V      3.63V
103.7ps   3.296V     2.97V      3.344V
188.6ps   3.294V     2.97V      2.299V
239.4ps   3.295V     2.97V      1.921V
529.7ps   3.169V     2.97V      1.284V
774.3ps   2.023V     2.967V     1.204V
1.14ns    1.556V     2.974V     1.182V
1.537ns   1.4V       2.96V      1.178V
2.205ns   1.347V     1.986V     1.177V
3.376ns   1.335V     1.586V     1.177V
[Falling Waveform]
R_fixture = 50
V_fixture = 0
V_fixture_min = 0
V_fixture_max = 0
0s        1.928V     1.397V     2.391V
82.21ps   1.924V     1.397V     1.948V
178ps     1.923V     1.397V     447mV
289.3ps   1.923V     1.397V     63.66mV
419.4ps   1.759V     1.397V     21.69mV
579.3ps   514.7mV    1.396V     10.23mV
764ps     88.43mV    1.396V     4.163mV
1.245ns   13.76mV    1.319V     321.5uV
1.597ns   6.085mV    257.5mV    53.28uV
2.223ns   8.589nV    120.9nV    4.032nV
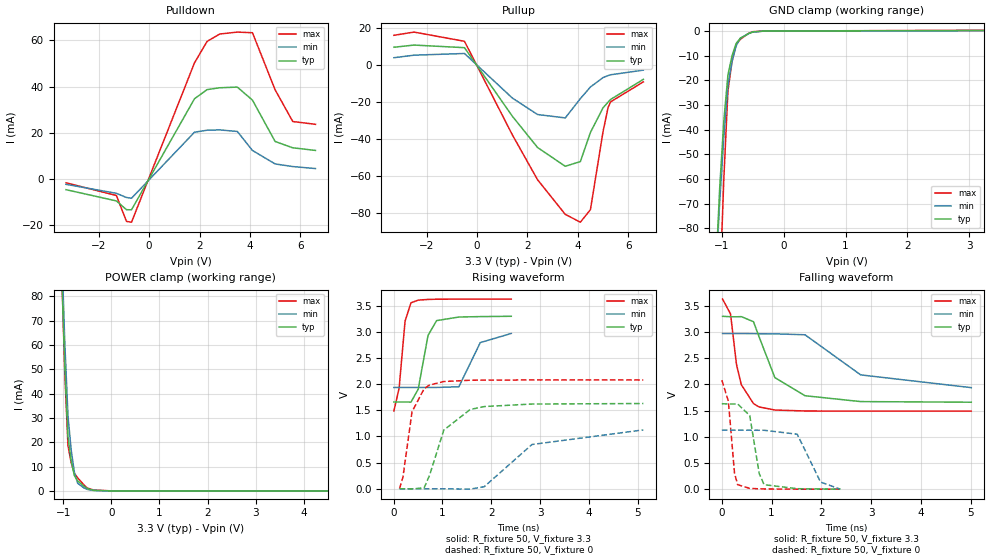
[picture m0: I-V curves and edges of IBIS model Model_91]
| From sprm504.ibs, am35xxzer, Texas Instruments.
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| Model based on original model for BQ1833DV50BTPBFZP18LL_7LM_X50
|   Sub model LL_7LM_X50_PD_ON_3P3
[model]   Model_91
|[Description]  3.3V-I/O-PD-X
|[Input Load]   PD
|[Output Drive]
|Voltage   3.3V
|Mode   I/O
Model_type   I/O
Polarity   Non-Inverting
Enable   Active-Low
Vinl =  0.8V
Vinh =  2V
Cref =  15pF
Rref =  100.0000M
Vref =  0V
Vmeas =  1.65
C_comp   1.683006p   1.492615p   1.787227p
[Model Spec]
Vinl   0.8V   0.8V   0.8V
Vinh   2V   2V   2V
[Temperature Range]   25   125   -40
[Voltage Range]   3.3   2.97   3.63
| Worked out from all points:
|   slope of the pulldown table from 0 to 0.495 V, typ, clamps not added: 44.5 ohm
|   slope of the pullup table from 0 to 0.495 V, typ, clamps not added: 49.1 ohm
|   GND clamp passes 1 mA (typ) near -0.56 V on its own axis
|   POWER clamp passes 1 mA (typ) near -0.50 V on its own axis
|   rising waveform, R_fixture 50, V_fixture 3.3: 20-80 % time 195ps typ, 280ps min, 122ps max; typ from 1.66 V to 3.3 V
|   rising waveform, R_fixture 50, V_fixture 0: 20-80 % time 426ps typ, 979ps min, 233ps max; typ from 0 V to 1.63 V
|   falling waveform, R_fixture 50, V_fixture 3.3: 20-80 % time 500ps typ, 961ps min, 224ps max; typ from 3.3 V to 1.66 V
|   falling waveform, R_fixture 50, V_fixture 0: 20-80 % time 155ps typ, 284ps min, 110ps max; typ from 1.63 V to 0 V
[POWER_clamp]
-3.3V     2.414A     2.856A     2.597A
-1.033V   91.41mA    100.8mA    92.12mA
-966.7mV  51.65mA    61.21mA    48.79mA
-900mV    22.33mA    30.87mA    18.6mA
-833.3mV  12.34mA    16.87mA    11.61mA
-766.7mV  6.286mA    7.643mA    7.215mA
-700mV    4.163mA    3.191mA    5.404mA
-566.7mV  1.931mA    1.219mA    2.461mA
-500mV    997.5uA    621.5uA    1.208mA
-366.7mV  252.8uA    162.2uA    342.1uA
33.33mV   0A         0A         0A
6.6V      0A         0A         0A
[Pulldown]
-3.3V     -4.669mA   -2.345mA   -1.683mA
-1.3V     -9.527mA   -6.237mA   -7.18mA
-900mV    -13.33mA   -8.043mA   -18.4mA
-700mV    -13.38mA   -8.364mA   -18.74mA
1.8V      34.72mA    20.23mA    50.27mA
2.3V      38.67mA    21.09mA    59.54mA
2.8V      39.47mA    21.22mA    62.74mA
3.5V      39.76mA    20.55mA    63.58mA
4.1V      34.11mA    12.32mA    63.3mA
5V        16.21mA    6.486mA    38.59mA
5.7V      13.47mA    5.354mA    24.85mA
6.6V      12.34mA    4.484mA    23.64mA
[Pullup]
-3.3V     9.738mA    4.045mA    16.21mA
-2.5V     10.91mA    5.432mA    17.95mA
-500mV    9.5mA      6.347mA    12.96mA
1.4V      -27.68mA   -17.82mA   -37.78mA
2.4V      -44.64mA   -26.76mA   -62.11mA
3.5V      -54.84mA   -28.6mA    -80.92mA
4.1V      -52.27mA   -18.13mA   -85.16mA
4.5V      -36.47mA   -11.82mA   -78.34mA
5V        -23.1mA    -6.724mA   -36.03mA
5.2V      -20.04mA   -5.652mA   -22.93mA
5.3V      -18.59mA   -5.203mA   -19.89mA
6.6V      -7.68mA    -2.683mA   -9.05mA
[GND_clamp]
-3.3V     -1.975A    -1.766A    -3.378A
-1.1V     -99.4mA    -100.8mA   -162mA
-1.033V   -63.74mA   -69.32mA   -106.1mA
-966.7mV  -36.57mA   -43.05mA   -60.18mA
-900mV    -17.88mA   -22.01mA   -24.32mA
-833.3mV  -10.01mA   -12.38mA   -12.35mA
-766.7mV  -5.054mA   -6.023mA   -5.382mA
-700mV    -3.018mA   -2.938mA   -3.413mA
-566.7mV  -1.062mA   -1.101mA   -1.024mA
-500mV    -403.5uA   -520.7uA   -326.7uA
-300mV    -30.38uA   -31.17uA   -39.69uA
3.233V    152.3uA    93.7uA     242.6uA
[Ramp]
dV/dt_f 0.98320301/0.49347319n 0.61923757/0.96011901n  1.2820937/0.22321522n
dV/dt_r 0.98244434/0.42477621n 0.67992602/0.97523237n  1.2527533/0.23238778n
R_load = 50
[Rising Waveform]
R_fixture = 50
V_fixture = 3.3
V_fixture_min = 2.97
V_fixture_max = 3.63
4.519ps   1.658V     1.936V     1.488V
110.4ps   1.658V     1.936V     1.917V
233.2ps   1.658V     1.936V     3.204V
354.3ps   1.656V     1.936V     3.553V
502.2ps   1.902V     1.936V     3.605V
704.1ps   2.931V     1.936V     3.618V
879.9ps   3.213V     1.936V     3.622V
1.336ns   3.282V     1.949V     3.624V
1.775ns   3.29V      2.793V     3.624V
2.411ns   3.296V     2.968V     3.625V
[Rising Waveform]
R_fixture = 50
V_fixture = 0
V_fixture_min = 0
V_fixture_max = 0
119.3ps   8.104nV    108.3nV    4.143nV
189.9ps   2.49uV     -322.1nV   223mV
375.4ps   -2.393mV   -80.84nV   1.469V
623.9ps   17.27mV    186nV      1.912V
736.3ps   259.3mV    71.64nV    1.983V
1.027ns   1.121V     8.578uV    2.049V
1.569ns   1.515V     -7.668mV   2.074V
1.857ns   1.571V     39.84mV    2.077V
2.835ns   1.619V     845.5mV    2.079V
5.119ns   1.629V     1.125V     2.079V
[Falling Waveform]
R_fixture = 50
V_fixture = 3.3
V_fixture_min = 2.97
V_fixture_max = 3.63
14.94ps   3.296V     2.968V     3.625V
175.1ps   3.288V     2.968V     3.34V
294ps     3.287V     2.968V     2.381V
391ps     3.29V      2.968V     1.993V
636.2ps   3.194V     2.966V     1.632V
748.2ps   2.907V     2.964V     1.568V
1.066ns   2.127V     2.962V     1.509V
1.672ns   1.782V     2.944V     1.491V
2.792ns   1.67V      2.179V     1.488V
5.015ns   1.658V     1.936V     1.488V
[Falling Waveform]
R_fixture = 50
V_fixture = 0
V_fixture_min = 0
V_fixture_max = 0
0s        1.629V     1.125V     2.079V
131.2ps   1.625V     1.125V     1.679V
254.4ps   1.625V     1.125V     309.5mV
317.3ps   1.625V     1.125V     85.92mV
561ps     1.404V     1.124V     14.76mV
751.4ps   297.8mV    1.123V     6.489mV
849.6ps   85.38mV    1.123V     3.906mV
1.516ns   9.01mV     1.048V     124.7uV
1.985ns   3.336mV    135.3mV    14.57uV
2.382ns   8.104nV    108.3nV    4.143nV
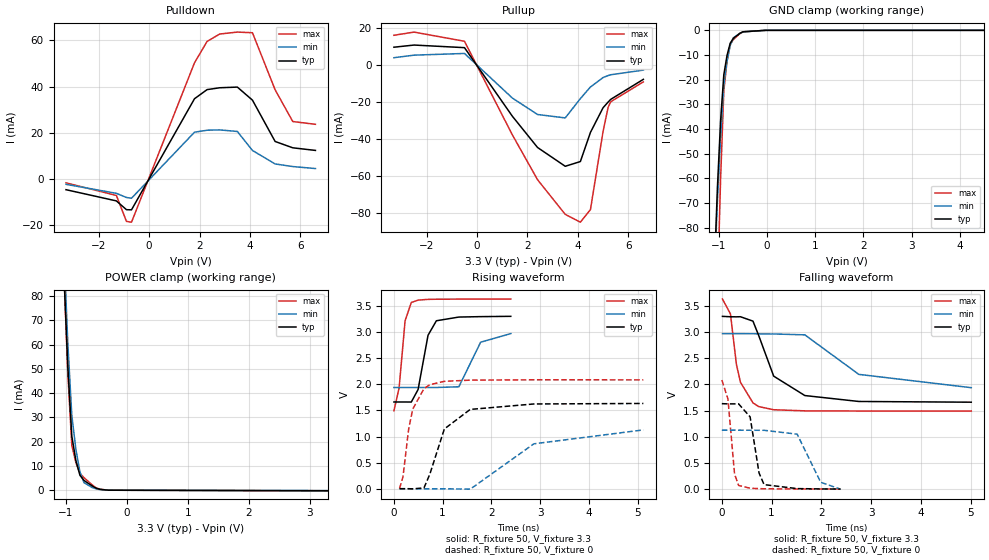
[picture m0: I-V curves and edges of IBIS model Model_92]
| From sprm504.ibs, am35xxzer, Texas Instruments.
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| Model based on original model for BQ1833DV50BTPBFZP18LL_7LM_X50
|   Sub model LL_7LM_X50_PU_ON_3P3
[model]   Model_92
|[Description]  3.3V-I/O-PU-X
|[Input Load]   PU
|[Output Drive]
|Voltage   3.3V
|Mode   I/O
Model_type   I/O
Polarity   Non-Inverting
Enable   Active-Low
Vinl =  0.8V
Vinh =  2V
Cref =  15pF
Rref =  100.0000M
Vref =  0V
Vmeas =  1.65
C_comp   1.683006p   1.492615p   1.787227p
[Model Spec]
Vinl   0.8V   0.8V   0.8V
Vinh   2V   2V   2V
[Temperature Range]   25   125   -40
[Voltage Range]   3.3   2.97   3.63
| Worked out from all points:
|   slope of the pulldown table from 0 to 0.495 V, typ, clamps not added: 44.5 ohm
|   slope of the pullup table from 0 to 0.495 V, typ, clamps not added: 49.1 ohm
|   GND clamp passes 1 mA (typ) near -0.54 V on its own axis
|   POWER clamp passes 1 mA (typ) near -0.51 V on its own axis
|   rising waveform, R_fixture 50, V_fixture 3.3: 20-80 % time 195ps typ, 279ps min, 122ps max; typ from 1.66 V to 3.3 V
|   rising waveform, R_fixture 50, V_fixture 0: 20-80 % time 425ps typ, 985ps min, 232ps max; typ from 0.004 V to 1.63 V
|   falling waveform, R_fixture 50, V_fixture 3.3: 20-80 % time 506ps typ, 970ps min, 226ps max; typ from 3.3 V to 1.66 V
|   falling waveform, R_fixture 50, V_fixture 0: 20-80 % time 155ps typ, 285ps min, 110ps max; typ from 1.63 V to 0.004 V
[POWER_clamp]
-3.3V     2.414A     2.856A     2.597A
-1.033V   91.31mA    100.7mA    91.95mA
-966.7mV  51.54mA    61.16mA    48.61mA
-900mV    22.22mA    30.81mA    18.41mA
-833.3mV  12.23mA    16.81mA    11.41mA
-766.7mV  6.164mA    7.579mA    7.005mA
-700mV    4.037mA    3.125mA    5.188mA
-566.7mV  1.798mA    1.149mA    2.234mA
-500mV    861.2uA    550uA      976.7uA
-433.3mV  389uA      264.1uA    415.9uA
-300mV    24.95uA    21.88uA    29.19uA
3.3V      -177.5uA   -135.7uA   -277.3uA
[Pulldown]
-3.3V     -4.669mA   -2.345mA   -1.683mA
-1.3V     -9.527mA   -6.237mA   -7.18mA
-900mV    -13.33mA   -8.044mA   -18.4mA
-700mV    -13.38mA   -8.364mA   -18.74mA
1.8V      34.72mA    20.23mA    50.28mA
2.3V      38.67mA    21.09mA    59.54mA
2.8V      39.47mA    21.22mA    62.74mA
3.5V      39.76mA    20.55mA    63.58mA
4.1V      34.11mA    12.32mA    63.3mA
5V        16.21mA    6.486mA    38.59mA
5.7V      13.47mA    5.354mA    24.85mA
6.6V      12.34mA    4.484mA    23.64mA
[Pullup]
-3.3V     9.738mA    4.045mA    16.21mA
-2.5V     10.91mA    5.432mA    17.94mA
-500mV    9.5mA      6.347mA    12.96mA
1.4V      -27.68mA   -17.82mA   -37.78mA
2.4V      -44.64mA   -26.76mA   -62.11mA
3.5V      -54.84mA   -28.6mA    -80.92mA
4.1V      -52.27mA   -18.13mA   -85.16mA
4.5V      -36.47mA   -11.82mA   -78.34mA
5V        -23.1mA    -6.724mA   -36.03mA
5.2V      -20.04mA   -5.652mA   -22.93mA
5.3V      -18.59mA   -5.203mA   -19.89mA
6.6V      -7.68mA    -2.683mA   -9.05mA
[GND_clamp]
-3.3V     -1.975A    -1.766A    -3.378A
-1.1V     -99.48mA   -100.9mA   -162.1mA
-1.033V   -63.84mA   -69.36mA   -106.2mA
-966.7mV  -36.69mA   -43.1mA    -60.36mA
-900mV    -18.03mA   -22.07mA   -24.57mA
-833.3mV  -10.17mA   -12.45mA   -12.64mA
-766.7mV  -5.227mA   -6.105mA   -5.683mA
-700mV    -3.195mA   -3.025mA   -3.716mA
-566.7mV  -1.239mA   -1.189mA   -1.328mA
-500mV    -580.8uA   -609.1uA   -631uA
-33.33mV  0A         0A         0A
6.6V      0A         0A         0A
[Ramp]
dV/dt_f 0.98252049/0.49548542n  0.6183508/0.96014624n  1.2814726/0.22462786n
dV/dt_r 0.98259654/0.4236438n 0.68007419/0.97384101n  1.2529834/0.23145144n
R_load = 50
[Rising Waveform]
R_fixture = 50
V_fixture = 3.3
V_fixture_min = 2.97
V_fixture_max = 3.63
2.169ps   1.662V     1.939V     1.494V
108.3ps   1.662V     1.939V     1.927V
231.1ps   1.662V     1.939V     3.214V
358.4ps   1.661V     1.939V     3.564V
497.7ps   1.9V       1.939V     3.61V
701.9ps   2.938V     1.939V     3.624V
872.9ps   3.215V     1.939V     3.627V
1.334ns   3.286V     1.953V     3.629V
1.78ns    3.294V     2.805V     3.63V
2.399ns   3.3V       2.97V      3.63V
[Rising Waveform]
R_fixture = 50
V_fixture = 0
V_fixture_min = 0
V_fixture_max = 0
116.9ps   4.128mV    2.524mV    5.94mV
187.8ps   4.131mV    2.524mV    231mV
303.9ps   3.865mV    2.524mV    1.141V
388ps     369.2uV    2.524mV    1.525V
618.6ps   19.54mV    2.524mV    1.917V
738.9ps   282.2mV    2.524mV    1.993V
1.036ns   1.146V     2.535mV    2.057V
1.567ns   1.52V      -5.015mV   2.08V
2.871ns   1.624V     861.9mV    2.086V
5.117ns   1.634V     1.128V     2.085V
[Falling Waveform]
R_fixture = 50
V_fixture = 3.3
V_fixture_min = 2.97
V_fixture_max = 3.63
12.97ps   3.3V       2.97V      3.63V
173ps     3.292V     2.97V      3.347V
293.2ps   3.291V     2.97V      2.383V
373.4ps   3.293V     2.97V      2.045V
625.5ps   3.209V     2.968V     1.649V
738.6ps   2.94V      2.966V     1.579V
1.042ns   2.159V     2.964V     1.518V
1.668ns   1.789V     2.947V     1.497V
2.753ns   1.676V     2.193V     1.494V
5.013ns   1.662V     1.939V     1.494V
[Falling Waveform]
R_fixture = 50
V_fixture = 0
V_fixture_min = 0
V_fixture_max = 0
0s        1.634V     1.128V     2.085V
123.1ps   1.63V      1.128V     1.722V
255.6ps   1.63V      1.128V     291.4mV
336.9ps   1.63V      1.128V     73.54mV
568.1ps   1.382V     1.127V     20.65mV
747.7ps   311.6mV    1.126V     12.73mV
849.3ps   89.23mV    1.126V     9.959mV
1.514ns   13.2mV     1.052V     6.074mV
1.987ns   7.419mV    133.7mV    5.958mV
2.386ns   4.128mV    2.524mV    5.94mV
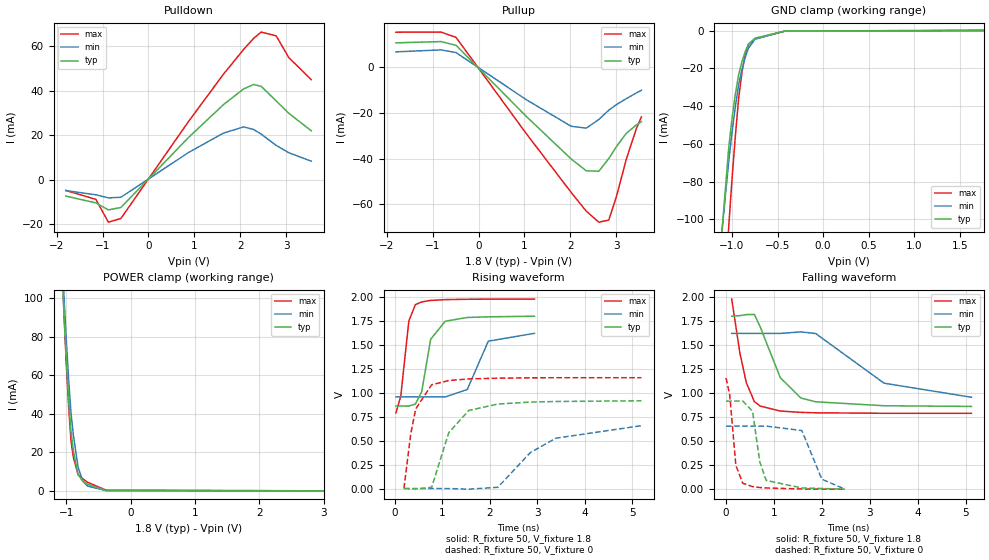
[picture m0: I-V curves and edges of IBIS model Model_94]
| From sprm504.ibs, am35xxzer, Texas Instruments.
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| Model based on original model for BC1833DV50BTPBFZP18LL_7LM_X50
|   Sub model LL_7LM_X50_PD_ON_1P8
[model]   Model_94
|[Description]  1.8V-I/O-PD-X
|[Input Load]   PD
|[Output Drive]
|Voltage   1.8V
|Mode   I/O
Model_type   I/O
Polarity   Non-Inverting
Enable   Active-Low
Vinl =  0.63V
Vinh =  1.17V
Cref =  15pF
Rref =  100.0000M
Vref =  0V
Vmeas =  0.9
C_comp   1.952094p   1.82457p   1.99685p
[Model Spec]
Vinl   0.63V   0.567V   0.693V
Vinh   1.17V   1.053V   1.287V
[Temperature Range]   25   125   -40
[Voltage Range]   1.8   1.62   1.98
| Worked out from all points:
|   slope of the pulldown table from 0 to 0.27 V, typ, clamps not added: 44.5 ohm
|   slope of the pullup table from 0 to 0.27 V, typ, clamps not added: 47.5 ohm
|   GND clamp passes 1 mA (typ) near -0.57 V on its own axis
|   POWER clamp passes 1 mA (typ) near -0.50 V on its own axis
|   rising waveform, R_fixture 50, V_fixture 1.8: 20-80 % time 219ps typ, 288ps min, 152ps max; typ from 0.86 V to 1.8 V
|   rising waveform, R_fixture 50, V_fixture 0: 20-80 % time 445ps typ, 979ps min, 246ps max; typ from 0 V to 0.915 V
|   falling waveform, R_fixture 50, V_fixture 1.8: 20-80 % time 521ps typ, 1.19ns min, 278ps max; typ from 1.8 V to 0.86 V
|   falling waveform, R_fixture 50, V_fixture 0: 20-80 % time 164ps typ, 258ps min, 123ps max; typ from 0.915 V to 0 V
[POWER_clamp]
-1.8V     833.5mA    863.2mA    901.5mA
-1.073V   119.6mA    128.2mA    123.8mA
-1.036V   91.01mA    100.4mA    91.59mA
-1V       67.24mA    77.32mA    64.95mA
-963.6mV  47.05mA    57.28mA    43.02mA
-927.3mV  30.45mA    40.27mA    25.81mA
-890.9mV  20.77mA    28.9mA     17.39mA
-818.2mV  8.439mA    12.32mA    8.493mA
-745.5mV  5.031mA    5.206mA    6.286mA
-672.7mV  3.489mA    2.545mA    4.552mA
-381.8mV  259.8uA    161.3uA    369uA
3.6V      0A         0A         0A
[Pulldown]
-1.8V     -7.359mA   -4.884mA   -4.817mA
-1.145V   -10.42mA   -6.784mA   -8.842mA
-872.7mV  -13.57mA   -8.176mA   -19.09mA
-600mV    -12.48mA   -7.89mA    -17.42mA
872.7mV   18.97mA    12.22mA    26.15mA
1.636V    33.77mA    20.96mA    47.46mA
2.073V    40.79mA    23.72mA    58.54mA
2.291V    42.78mA    22.54mA    63.52mA
2.455V    41.93mA    20.49mA    66.32mA
2.782V    35.41mA    15.4mA     64.63mA
3.055V    29.87mA    12.14mA    54.89mA
3.545V    21.98mA    8.327mA    44.95mA
[Pullup]
-1.8V     10.75mA    6.804mA    15.41mA
-818.2mV  11.31mA    7.663mA    15.46mA
-490.9mV  9.668mA    6.495mA    13.14mA
1.036V    -21.39mA   -14.1mA    -28.91mA
2.018V    -40.11mA   -25.78mA   -54.77mA
2.345V    -45.27mA   -26.58mA   -62.92mA
2.618V    -45.47mA   -22.82mA   -67.76mA
2.836V    -39.88mA   -18.72mA   -66.82mA
3V        -34.74mA   -16.32mA   -56.71mA
3.218V    -28.82mA   -13.69mA   -40.13mA
3.436V    -25.21mA   -11.19mA   -26.84mA
3.545V    -23.75mA   -10mA      -21.69mA
[GND_clamp]
-1.8V     -667.9mA   -536.4mA   -1.146A
-1.109V   -105.7mA   -105.8mA   -172.9mA
-1.036V   -62.17mA   -69.32mA   -103.8mA
-1V       -46.71mA   -54.02mA   -78.81mA
-963.6mV  -33.8mA    -40.46mA   -56.2mA
-927.3mV  -23.44mA   -28.63mA   -35.97mA
-890.9mV  -16.48mA   -20.58mA   -22.17mA
-854.5mV  -11.01mA   -14.09mA   -12.55mA
-818.2mV  -6.997mA   -9.134mA   -7.115mA
-745.5mV  -3.905mA   -4.379mA   -4.408mA
-418.2mV  -143.9uA   -179.4uA   -151.5uA
1.764V    148.6uA    81.65uA    236.4uA
[Ramp]
dV/dt_f 0.57683459/0.52394827n 0.41119338/1.1992359n 0.72323639/0.27930779n
dV/dt_r  0.5632995/0.4449142n 0.40514261/0.98105232n 0.70212805/0.24684616n
R_load = 50
[Rising Waveform]
R_fixture = 50
V_fixture = 1.8
V_fixture_min = 1.62
V_fixture_max = 1.98
24.69ps   859.5mV    954.6mV    788mV
126.3ps   859.5mV    954.6mV    962.6mV
296.8ps   859.3mV    954.6mV    1.747V
435.2ps   880.7mV    954.6mV    1.917V
567.3ps   1.01V      954.6mV    1.945V
756.6ps   1.556V     954.6mV    1.961V
1.063ns   1.744V     954.6mV    1.969V
1.528ns   1.783V     1.033V     1.973V
1.97ns    1.79V      1.536V     1.974V
2.942ns   1.796V     1.618V     1.975V
[Rising Waveform]
R_fixture = 50
V_fixture = 0
V_fixture_min = 0
V_fixture_max = 0
193ps     9.354nV    87.9nV     10.64nV
337.2ps   -2.153mV   2.17uV     571.7mV
441.3ps   -5.272mV   200.9nV    830mV
777ps     12.63mV    -2.349uV   1.082V
1.137ns   582.2mV    -137.2uV   1.126V
1.558ns   813.5mV    -6.589mV   1.143V
2.17ns    880.8mV    12.94mV    1.15V
2.854ns   901.2mV    374.6mV    1.154V
3.39ns    907.2mV    524.4mV    1.155V
5.193ns   914.7mV    655.2mV    1.155V
[Falling Waveform]
R_fixture = 50
V_fixture = 1.8
V_fixture_min = 1.62
V_fixture_max = 1.98
118.1ps   1.796V     1.618V     1.975V
288.9ps   1.803V     1.618V     1.413V
423.4ps   1.814V     1.618V     1.105V
591.5ps   1.815V     1.618V     908.3mV
711.3ps   1.687V     1.618V     863.2mV
1.131ns   1.158V     1.618V     811.7mV
1.558ns   947.6mV    1.634V     798mV
1.869ns   907.6mV    1.617V     793.4mV
3.295ns   866.7mV    1.101V     788.3mV
5.118ns   859.5mV    954.6mV    788mV
[Falling Waveform]
R_fixture = 50
V_fixture = 0
V_fixture_min = 0
V_fixture_max = 0
0s        914.7mV    655.2mV    1.155V
76.6ps    914.4mV    655.2mV    978.8mV
204.7ps   915.3mV    655.2mV    247.5mV
347.7ps   916.2mV    655.2mV    61.08mV
553ps     809.1mV    655.2mV    26.09mV
702.8ps   285.9mV    655.2mV    17.15mV
836.7ps   90.71mV    655.1mV    12.77mV
1.58ns    12.4mV     608.7mV    1.729mV
1.998ns   6.849mV    103.4mV    535uV
2.481ns   9.354nV    87.9nV     10.64nV
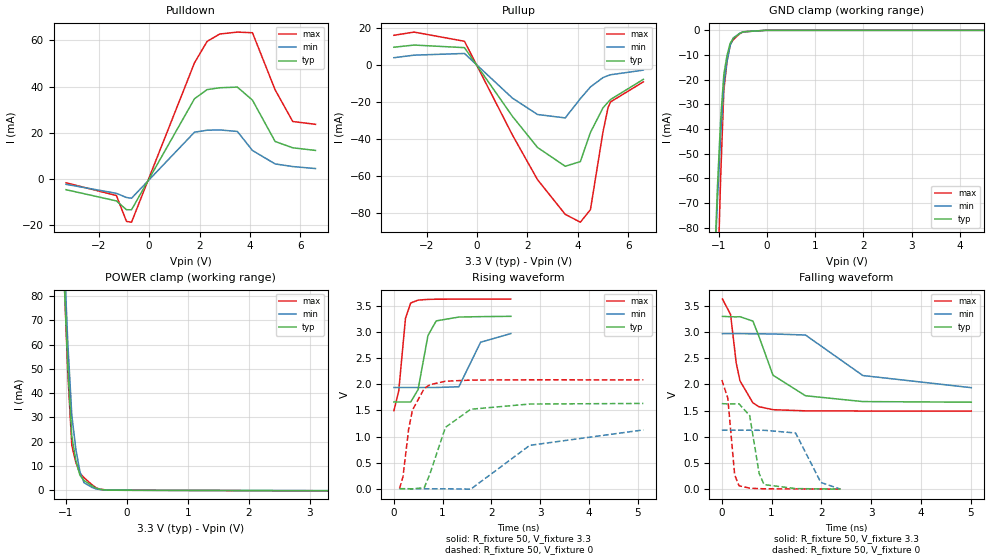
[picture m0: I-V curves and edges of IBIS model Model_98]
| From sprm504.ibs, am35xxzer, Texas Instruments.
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| Model based on original model for BC1833DV50BTPBFZP18LL_7LM_X50
|   Sub model LL_7LM_X50_PU_ON_3P3
[model]   Model_98
|[Description]  3.3V-I/O-PU-X
|[Input Load]   PU
|[Output Drive]
|Voltage   3.3V
|Mode   I/O
Model_type   I/O
Polarity   Non-Inverting
Enable   Active-Low
Vinl =  0.8V
Vinh =  2V
Cref =  15pF
Rref =  100.0000M
Vref =  0V
Vmeas =  1.65
C_comp   1.683006p   1.492615p   1.787227p
[Model Spec]
Vinl   0.8V   0.8V   0.8V
Vinh   2V   2V   2V
[Temperature Range]   25   125   -40
[Voltage Range]   3.3   2.97   3.63
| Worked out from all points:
|   slope of the pulldown table from 0 to 0.495 V, typ, clamps not added: 44.5 ohm
|   slope of the pullup table from 0 to 0.495 V, typ, clamps not added: 49.1 ohm
|   GND clamp passes 1 mA (typ) near -0.54 V on its own axis
|   POWER clamp passes 1 mA (typ) near -0.51 V on its own axis
|   rising waveform, R_fixture 50, V_fixture 3.3: 20-80 % time 194ps typ, 279ps min, 123ps max; typ from 1.66 V to 3.3 V
|   rising waveform, R_fixture 50, V_fixture 0: 20-80 % time 425ps typ, 984ps min, 231ps max; typ from 0.004 V to 1.63 V
|   falling waveform, R_fixture 50, V_fixture 3.3: 20-80 % time 502ps typ, 964ps min, 227ps max; typ from 3.3 V to 1.66 V
|   falling waveform, R_fixture 50, V_fixture 0: 20-80 % time 155ps typ, 285ps min, 110ps max; typ from 1.63 V to 0.004 V
[POWER_clamp]
-3.3V     2.414A     2.856A     2.597A
-1.033V   91.31mA    100.7mA    91.95mA
-966.7mV  51.54mA    61.16mA    48.61mA
-900mV    22.22mA    30.81mA    18.41mA
-833.3mV  12.23mA    16.81mA    11.41mA
-766.7mV  6.164mA    7.579mA    7.005mA
-700mV    4.037mA    3.125mA    5.188mA
-566.7mV  1.798mA    1.149mA    2.234mA
-500mV    861.2uA    550uA      976.7uA
-433.3mV  389uA      264.1uA    415.9uA
-300mV    24.95uA    21.88uA    29.19uA
3.3V      -177.5uA   -135.7uA   -277.3uA
[Pulldown]
-3.3V     -4.669mA   -2.345mA   -1.683mA
-1.3V     -9.527mA   -6.237mA   -7.18mA
-900mV    -13.33mA   -8.044mA   -18.4mA
-700mV    -13.38mA   -8.364mA   -18.74mA
1.8V      34.72mA    20.23mA    50.28mA
2.3V      38.67mA    21.09mA    59.54mA
2.8V      39.47mA    21.22mA    62.74mA
3.5V      39.76mA    20.55mA    63.58mA
4.1V      34.11mA    12.32mA    63.3mA
5V        16.21mA    6.486mA    38.59mA
5.7V      13.47mA    5.354mA    24.85mA
6.6V      12.34mA    4.484mA    23.64mA
[Pullup]
-3.3V     9.738mA    4.045mA    16.21mA
-2.5V     10.91mA    5.432mA    17.94mA
-500mV    9.5mA      6.347mA    12.96mA
1.4V      -27.68mA   -17.82mA   -37.78mA
2.4V      -44.64mA   -26.76mA   -62.11mA
3.5V      -54.84mA   -28.6mA    -80.92mA
4.1V      -52.27mA   -18.13mA   -85.16mA
4.5V      -36.47mA   -11.82mA   -78.34mA
5V        -23.1mA    -6.724mA   -36.03mA
5.2V      -20.04mA   -5.652mA   -22.93mA
5.3V      -18.59mA   -5.203mA   -19.89mA
6.6V      -7.68mA    -2.683mA   -9.05mA
[GND_clamp]
-3.3V     -1.975A    -1.766A    -3.378A
-1.1V     -99.48mA   -100.9mA   -162.1mA
-1.033V   -63.84mA   -69.36mA   -106.2mA
-966.7mV  -36.69mA   -43.1mA    -60.36mA
-900mV    -18.03mA   -22.07mA   -24.57mA
-833.3mV  -10.17mA   -12.45mA   -12.64mA
-766.7mV  -5.227mA   -6.105mA   -5.683mA
-700mV    -3.195mA   -3.025mA   -3.716mA
-566.7mV  -1.239mA   -1.189mA   -1.328mA
-500mV    -580.8uA   -609.1uA   -631uA
-33.33mV  0A         0A         0A
6.6V      0A         0A         0A
[Ramp]
dV/dt_f 0.98252048/0.49547988n 0.61835081/0.9601547n  1.2814726/0.22462597n
dV/dt_r 0.98259671/0.42372282n 0.68007409/0.97378036n  1.2529836/0.23146144n
R_load = 50
[Rising Waveform]
R_fixture = 50
V_fixture = 3.3
V_fixture_min = 2.97
V_fixture_max = 3.63
2.17ps    1.662V     1.939V     1.494V
101.5ps   1.662V     1.939V     1.876V
239ps     1.662V     1.939V     3.26V
346.1ps   1.661V     1.939V     3.555V
497.7ps   1.9V       1.939V     3.61V
699.9ps   2.932V     1.939V     3.624V
869.6ps   3.213V     1.939V     3.627V
1.334ns   3.286V     1.953V     3.629V
1.78ns    3.294V     2.805V     3.63V
2.399ns   3.3V       2.97V      3.63V
[Rising Waveform]
R_fixture = 50
V_fixture = 0
V_fixture_min = 0
V_fixture_max = 0
116.9ps   4.128mV    2.524mV    5.94mV
187.8ps   4.131mV    2.524mV    231mV
303.9ps   3.864mV    2.524mV    1.141V
382.5ps   816.3uV    2.524mV    1.508V
625ps     24.58mV    2.524mV    1.922V
738.9ps   282.2mV    2.524mV    1.993V
1.059ns   1.178V     2.539mV    2.059V
1.578ns   1.523V     -5.078mV   2.081V
2.788ns   1.623V     833.1mV    2.086V
5.117ns   1.634V     1.128V     2.085V
[Falling Waveform]
R_fixture = 50
V_fixture = 3.3
V_fixture_min = 2.97
V_fixture_max = 3.63
12.98ps   3.3V       2.97V      3.63V
175.5ps   3.292V     2.97V      3.336V
289.5ps   3.291V     2.97V      2.407V
365.2ps   3.293V     2.97V      2.069V
624ps     3.21V      2.968V     1.65V
743.7ps   2.922V     2.966V     1.577V
1.028ns   2.177V     2.964V     1.519V
1.681ns   1.785V     2.944V     1.497V
2.834ns   1.674V     2.171V     1.494V
5.013ns   1.662V     1.939V     1.494V
[Falling Waveform]
R_fixture = 50
V_fixture = 0
V_fixture_min = 0
V_fixture_max = 0
0s        1.634V     1.128V     2.085V
119.6ps   1.63V      1.128V     1.742V
257.9ps   1.63V      1.128V     274.4mV
345.3ps   1.63V      1.128V     67.77mV
560ps     1.406V     1.127V     21.21mV
749.5ps   303.4mV    1.126V     12.67mV
849.1ps   89.4mV     1.126V     9.969mV
1.482ns   13.93mV    1.075V     6.096mV
1.99ns    7.405mV    130.5mV    5.957mV
2.386ns   4.128mV    2.524mV    5.94mV
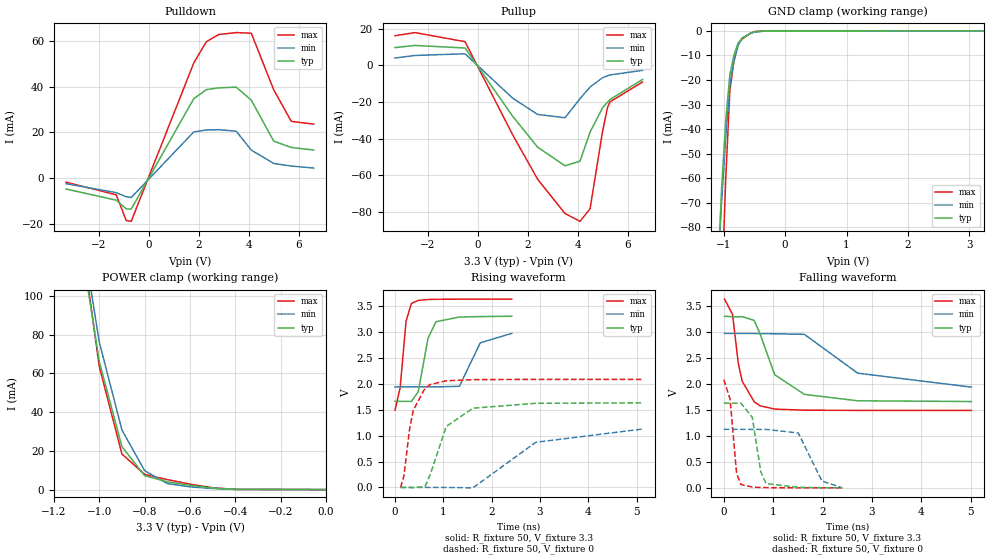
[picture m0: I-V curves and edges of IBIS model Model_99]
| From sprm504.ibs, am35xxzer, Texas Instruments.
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| Model based on original model for BC1833DV50BTPBFZP18LL_7LM_X50
|   Sub model LM_X50_PD_PU_OFF_3P3
[model]   Model_99
|[Description]  3.3V-I/O-PI-X
|[Input Load]   PI
|[Output Drive]
|Voltage   3.3V
|Mode   I/O
Model_type   I/O
Polarity   Non-Inverting
Enable   Active-Low
Vinl =  0.8V
Vinh =  2V
Cref =  15pF
Rref =  100.0000M
Vref =  0V
Vmeas =  1.65
C_comp   1.683006p   1.492615p   1.787227p
[Model Spec]
Vinl   0.8V   0.8V   0.8V
Vinh   2V   2V   2V
[Temperature Range]   25   125   -40
[Voltage Range]   3.3   2.97   3.63
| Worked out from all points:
|   slope of the pulldown table from 0 to 0.495 V, typ, clamps not added: 44.5 ohm
|   slope of the pullup table from 0 to 0.495 V, typ, clamps not added: 49.1 ohm
|   GND clamp passes 1 mA (typ) near -0.56 V on its own axis
|   POWER clamp passes 1 mA (typ) near -0.51 V on its own axis
|   rising waveform, R_fixture 50, V_fixture 3.3: 20-80 % time 195ps typ, 279ps min, 122ps max; typ from 1.66 V to 3.3 V
|   rising waveform, R_fixture 50, V_fixture 0: 20-80 % time 428ps typ, 984ps min, 236ps max; typ from 0 V to 1.63 V
|   falling waveform, R_fixture 50, V_fixture 3.3: 20-80 % time 499ps typ, 978ps min, 229ps max; typ from 3.3 V to 1.66 V
|   falling waveform, R_fixture 50, V_fixture 0: 20-80 % time 155ps typ, 285ps min, 110ps max; typ from 1.63 V to 0 V
[POWER_clamp]
-3.3V     2.414A     2.856A     2.597A
-1.067V   116.4mA    125.1mA    120.2mA
-1.033V   91.29mA    100.7mA    91.93mA
-1V       66.19mA    76.32mA    63.69mA
-900mV    22.2mA     30.8mA     18.38mA
-800mV    7.208mA    9.795mA    7.881mA
-700mV    4.017mA    3.114mA    5.155mA
-600mV    2.246mA    1.437mA    2.828mA
-500mV    840.1uA    538.7uA    942.1uA
-400mV    133.3uA    110.7uA    103.8uA
0V        9.333nA    42.82nA    36.63nA
[Pulldown]
-3.3V     -4.669mA   -2.345mA   -1.683mA
-1.3V     -9.527mA   -6.237mA   -7.18mA
-900mV    -13.33mA   -8.043mA   -18.4mA
-700mV    -13.38mA   -8.364mA   -18.74mA
1.8V      34.72mA    20.23mA    50.28mA
2.3V      38.67mA    21.09mA    59.54mA
2.8V      39.47mA    21.22mA    62.74mA
3.5V      39.76mA    20.55mA    63.58mA
4.1V      34.11mA    12.32mA    63.3mA
5V        16.21mA    6.486mA    38.59mA
5.7V      13.47mA    5.354mA    24.85mA
6.6V      12.34mA    4.484mA    23.64mA
[Pullup]
-3.3V     9.738mA    4.045mA    16.21mA
-2.5V     10.91mA    5.432mA    17.94mA
-500mV    9.5mA      6.347mA    12.96mA
1.4V      -27.68mA   -17.82mA   -37.78mA
2.4V      -44.64mA   -26.76mA   -62.11mA
3.5V      -54.84mA   -28.6mA    -80.92mA
4.1V      -52.27mA   -18.13mA   -85.16mA
4.5V      -36.47mA   -11.82mA   -78.33mA
5V        -23.1mA    -6.724mA   -36.03mA
5.2V      -20.04mA   -5.652mA   -22.93mA
5.3V      -18.59mA   -5.203mA   -19.89mA
6.6V      -7.68mA    -2.683mA   -9.05mA
[GND_clamp]
-3.3V     -1.975A    -1.766A    -3.378A
-1.1V     -99.4mA    -100.8mA   -162mA
-1.033V   -63.74mA   -69.32mA   -106.1mA
-966.7mV  -36.56mA   -43.04mA   -60.17mA
-900mV    -17.88mA   -22mA      -24.31mA
-833.3mV  -9.995mA   -12.37mA   -12.32mA
-766.7mV  -5.035mA   -6.016mA   -5.345mA
-700mV    -2.995mA   -2.928mA   -3.372mA
-566.7mV  -1.037mA   -1.089mA   -982.7uA
-500mV    -379.4uA   -508.9uA   -286.6uA
-300mV    -14.25uA   -22.31uA   -14.38uA
3.233V    8.935nA    10.41uA    33.57nA
[Ramp]
dV/dt_f  0.9840264/0.49687855n 0.61917332/0.96342022n  1.2838169/0.22527825n
dV/dt_r  0.9837656/0.42622408n  0.6805862/0.9776503n  1.2549259/0.23335912n
R_load = 50
[Rising Waveform]
R_fixture = 50
V_fixture = 3.3
V_fixture_min = 2.97
V_fixture_max = 3.63
4.38ps    1.66V      1.938V     1.49V
110.3ps   1.66V      1.938V     1.921V
233.3ps   1.66V      1.938V     3.209V
344.6ps   1.659V     1.938V     3.548V
484.9ps   1.846V     1.938V     3.606V
687.1ps   2.879V     1.938V     3.623V
852.2ps   3.195V     1.938V     3.627V
1.334ns   3.285V     1.95V      3.629V
1.766ns   3.294V     2.788V     3.63V
2.416ns   3.3V       2.97V      3.63V
[Rising Waveform]
R_fixture = 50
V_fixture = 0
V_fixture_min = 0
V_fixture_max = 0
119.2ps   8.36nV     112.1nV    4.117nV
189.8ps   2.491uV    -318.4nV   223mV
301.8ps   -218.8uV   -417.5nV   1.103V
380.5ps   -2.926mV   -55.02nV   1.486V
627.1ps   19.86mV    184.6nV    1.916V
735.4ps   256.2mV    75.24nV    1.985V
1.062ns   1.175V     14.71uV    2.056V
1.614ns   1.528V     -7.875mV   2.078V
2.911ns   1.622V     870.2mV    2.083V
5.119ns   1.631V     1.126V     2.083V
[Falling Waveform]
R_fixture = 50
V_fixture = 3.3
V_fixture_min = 2.97
V_fixture_max = 3.63
15.01ps   3.3V       2.97V      3.63V
177.6ps   3.292V     2.97V      3.336V
293.7ps   3.291V     2.97V      2.392V
371.9ps   3.293V     2.97V      2.054V
614.5ps   3.222V     2.969V     1.657V
733.1ps   2.967V     2.966V     1.579V
1.03ns    2.177V     2.964V     1.515V
1.632ns   1.798V     2.953V     1.494V
2.712ns   1.675V     2.206V     1.49V
5.015ns   1.66V      1.938V     1.49V
[Falling Waveform]
R_fixture = 50
V_fixture = 0
V_fixture_min = 0
V_fixture_max = 0
0s        1.631V     1.126V     2.083V
127.1ps   1.628V     1.126V     1.708V
259.7ps   1.628V     1.126V     272.1mV
347.3ps   1.628V     1.126V     63.25mV
577.1ps   1.356V     1.125V     14.94mV
749.4ps   309.9mV    1.124V     7.214mV
855.2ps   83.34mV    1.124V     4.23mV
1.508ns   10.07mV    1.056V     166.7uV
1.989ns   3.877mV    130.9mV    20.21uV
2.4ns     8.36nV     112.1nV    4.117nV
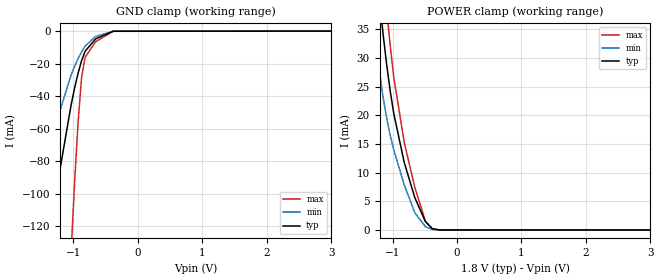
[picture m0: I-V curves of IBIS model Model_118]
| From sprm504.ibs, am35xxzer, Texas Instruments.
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| Model based on original model for BSSTL18TCSCGPBFZ_7LM
|   Sub model NO_TERM_LVCM_0.1_1P8
[model]   Model_118
|[Description]  1.8V-INPUT-NONE_LVCMOS-X-+-0.1V
|[Input Load]   NONE_LVCMOS
|[Output Drive]
|Voltage   1.8V
|Mode   INPUT
Model_type   Input
Polarity   Non-Inverting
Vinl =  0.63
Vinh =  1.17
C_comp   3.009089p   2.23501p   3.95018p
[Model Spec]
Vinl   0.63   0.595   0.665
Vinh   1.17   1.105   1.235
[Temperature Range]   25   125   -40
[Voltage Range]   1.8   1.7   1.9
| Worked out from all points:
|   GND clamp passes 1 mA (typ) near -0.50 V on its own axis
|   POWER clamp passes 1 mA (typ) near -0.46 V on its own axis
[POWER_clamp]
-1.8V     107.1mA    82.35mA    134mA
-1.309V   51.22mA    36.01mA    66.89mA
-1.145V   33.99mA    23.04mA    45.23mA
-1.091V   28.82mA    19.5mA     38.44mA
-1.036V   24.21mA    16.5mA     32.13mA
-981.8mV  20.35mA    13.98mA    26.66mA
-818.2mV  11.74mA    7.848mA    15.25mA
-654.5mV  5.636mA    3.005mA    7.42mA
-490.9mV  1.465mA    582.6uA    1.573mA
-381.8mV  213.5uA    94.2uA     152.3uA
-272.7mV  11.26uA    9.62uA     3.79uA
3.545V    0A         0A         0A
[GND_clamp]
-1.8V     -229.3mA   -132mA     -818.5mA
-1.745V   -215.7mA   -124mA     -769.6mA
-1.691V   -202.2mA   -116mA     -720.6mA
-1.364V   -121.2mA   -68.84mA   -424.9mA
-1.036V   -45.71mA   -27.15mA   -136.8mA
-981.8mV  -35.25mA   -21.76mA   -94.05mA
-927.3mV  -26.04mA   -16.99mA   -56.46mA
-872.7mV  -18.27mA   -12.8mA    -28.74mA
-818.2mV  -12.44mA   -9.252mA   -16.16mA
-654.5mV  -4.789mA   -3.281mA   -6.528mA
-381.8mV  -101.3uA   -119.6uA   -85.77uA
3.545V    0A         0A         0A
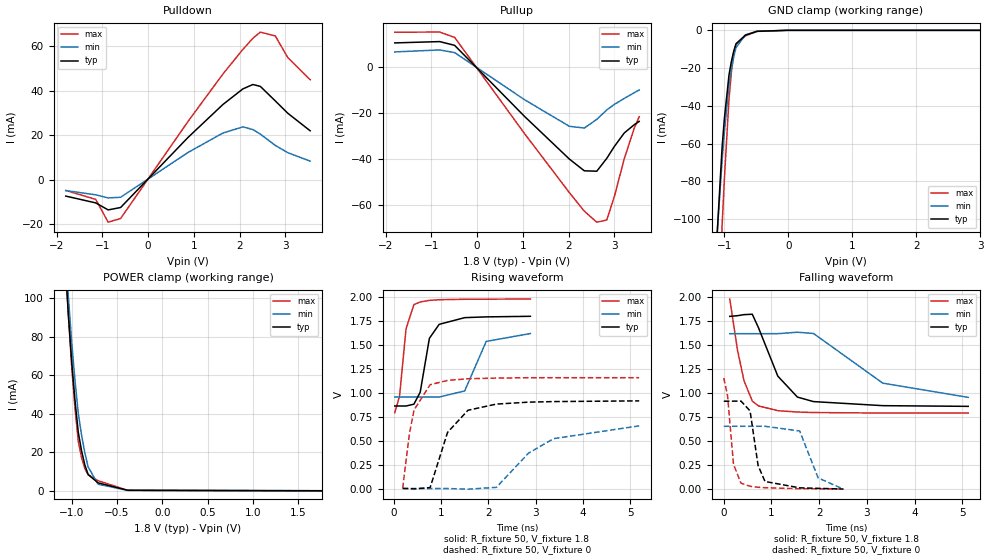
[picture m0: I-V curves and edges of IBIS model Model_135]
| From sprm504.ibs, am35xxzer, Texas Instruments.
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| Model based on original model for BC1833DV50BTPBFHP18LL_7LM
|   Sub model HP18LL_7LM_PU_ON_1P8
[model]   Model_135
|[Description]  1.8V-I/O-PU-X
|[Input Load]   PU
|[Output Drive]
|Voltage   1.8V
|Mode   I/O
Model_type   I/O
Polarity   Non-Inverting
Enable   Active-Low
Vinl =  0.63V
Vinh =  1.17V
Cref =  15pF
Rref =  100.0000M
Vref =  0V
Vmeas =  0.9
C_comp   1.952094p   1.82457p   1.99685p
[Model Spec]
Vinl   0.63V   0.567V   0.693V
Vinh   1.17V   1.053V   1.287V
[Temperature Range]   25   125   -40
[Voltage Range]   1.8   1.62   1.98
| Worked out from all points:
|   slope of the pulldown table from 0 to 0.27 V, typ, clamps not added: 44.6 ohm
|   slope of the pullup table from 0 to 0.27 V, typ, clamps not added: 47.6 ohm
|   GND clamp passes 1 mA (typ) near -0.55 V on its own axis
|   POWER clamp passes 1 mA (typ) near -0.52 V on its own axis
|   rising waveform, R_fixture 50, V_fixture 1.8: 20-80 % time 212ps typ, 284ps min, 149ps max; typ from 0.864 V to 1.8 V
|   rising waveform, R_fixture 50, V_fixture 0: 20-80 % time 444ps typ, 981ps min, 246ps max; typ from 0.003 V to 0.917 V
|   falling waveform, R_fixture 50, V_fixture 1.8: 20-80 % time 530ps typ, 1.21ns min, 283ps max; typ from 1.8 V to 0.864 V
|   falling waveform, R_fixture 50, V_fixture 0: 20-80 % time 165ps typ, 256ps min, 125ps max; typ from 0.917 V to 0.003 V
[POWER_clamp]
-1.8V     833.3mA    863.1mA    901.2mA
-1.073V   119.5mA    128.1mA    123.5mA
-1.036V   90.84mA    100.3mA    91.31mA
-1V       67.07mA    77.23mA    64.67mA
-963.6mV  46.88mA    57.2mA     42.73mA
-927.3mV  30.28mA    40.18mA    25.52mA
-890.9mV  20.6mA     28.81mA    17.1mA
-854.5mV  13.26mA    19.49mA    11.33mA
-818.2mV  8.265mA    12.23mA    8.199mA
-709.1mV  3.977mA    3.264mA    5.102mA
-381.8mV  105.8uA    84.74uA    101.6uA
1.764V    -143.5uA   -80.1uA    -225.9uA
[Pulldown]
-1.8V     -7.339mA   -4.872mA   -4.803mA
-1.145V   -10.39mA   -6.769mA   -8.82mA
-872.7mV  -13.54mA   -8.159mA   -19.05mA
-600mV    -12.46mA   -7.873mA   -17.38mA
872.7mV   18.95mA    12.21mA    26.11mA
1.636V    33.73mA    20.94mA    47.4mA
2.073V    40.74mA    23.7mA     58.46mA
2.291V    42.72mA    22.53mA    63.43mA
2.455V    41.87mA    20.47mA    66.23mA
2.782V    35.36mA    15.4mA     64.52mA
3.055V    29.83mA    12.14mA    54.79mA
3.545V    21.95mA    8.339mA    44.87mA
[Pullup]
-1.8V     10.72mA    6.784mA    15.4mA
-818.2mV  11.29mA    7.651mA    15.44mA
-490.9mV  9.653mA    6.484mA    13.12mA
1.036V    -21.34mA   -14.06mA   -28.84mA
2.018V    -39.99mA   -25.69mA   -54.63mA
2.345V    -45.12mA   -26.45mA   -62.75mA
2.618V    -45.29mA   -22.66mA   -67.55mA
2.836V    -39.69mA   -18.55mA   -66.59mA
3V        -34.54mA   -16.15mA   -56.48mA
3.218V    -28.61mA   -13.52mA   -39.88mA
3.436V    -25.01mA   -11.02mA   -26.57mA
3.545V    -23.56mA   -9.84mA    -21.49mA
[GND_clamp]
-1.8V     -667.9mA   -536.4mA   -1.146A
-1.109V   -105.8mA   -105.8mA   -173mA
-1.036V   -62.26mA   -69.36mA   -103.9mA
-1V       -46.8mA    -54.07mA   -78.95mA
-927.3mV  -23.56mA   -28.69mA   -36.16mA
-890.9mV  -16.62mA   -20.65mA   -22.4mA
-854.5mV  -11.15mA   -14.15mA   -12.8mA
-818.2mV  -7.146mA   -9.205mA   -7.373mA
-672.7mV  -2.583mA   -2.428mA   -3.006mA
-490.9mV  -511.9uA   -524.2uA   -577.2uA
-18.18mV  0A         0A         0A
3.6V      0A         0A         0A
[Ramp]
dV/dt_f 0.57878939/0.53393948n 0.41197681/1.2225561n 0.72381054/0.28408865n
dV/dt_r 0.56197871/0.44453821n  0.4038601/0.98104866n 0.70098175/0.24592724n
R_load = 50
[Rising Waveform]
R_fixture = 50
V_fixture = 1.8
V_fixture_min = 1.62
V_fixture_max = 1.98
24.44ps   863.7mV    957.3mV    793.8mV
125.6ps   863.7mV    957.3mV    967mV
262.5ps   863.5mV    957.3mV    1.669V
428.8ps   882.6mV    957.3mV    1.922V
561.8ps   1.007V     957.3mV    1.95V
756.2ps   1.57V      957.3mV    1.966V
963ps     1.716V     957.3mV    1.973V
1.502ns   1.786V     1.021V     1.978V
1.957ns   1.794V     1.538V     1.979V
2.891ns   1.8V       1.62V      1.98V
[Rising Waveform]
R_fixture = 50
V_fixture = 0
V_fixture_min = 0
V_fixture_max = 0
191.4ps   3.423mV    2.084mV    4.971mV
335ps     1.282mV    2.086mV    576.7mV
432.5ps   -1.725mV   2.084mV    822.7mV
772ps     12.07mV    2.081mV    1.086V
1.14ns    588.1mV    1.94mV     1.131V
1.572ns   819.3mV    -4.611mV   1.148V
2.172ns   883.6mV    14.29mV    1.155V
2.851ns   903.8mV    371mV      1.159V
3.382ns   909.7mV    522.8mV    1.159V
5.191ns   917.2mV    656.3mV    1.159V
[Falling Waveform]
R_fixture = 50
V_fixture = 1.8
V_fixture_min = 1.62
V_fixture_max = 1.98
125.9ps   1.8V       1.62V      1.98V
288.4ps   1.807V     1.62V      1.446V
423.8ps   1.818V     1.62V      1.131V
597.8ps   1.822V     1.62V      918.3mV
729.9ps   1.679V     1.62V      868.3mV
1.133ns   1.178V     1.62V      818.6mV
1.544ns   960.2mV    1.635V     804.6mV
1.88ns    913.3mV    1.622V     799.4mV
3.336ns   870.9mV    1.105V     794.1mV
5.126ns   863.7mV    957.3mV    793.8mV
[Falling Waveform]
R_fixture = 50
V_fixture = 0
V_fixture_min = 0
V_fixture_max = 0
0s        917.2mV    656.3mV    1.159V
77.39ps   917.1mV    656.3mV    981.3mV
203.6ps   917.9mV    656.3mV    261.6mV
361.2ps   918.1mV    656.3mV    64.01mV
550.8ps   816.9mV    656.3mV    32.21mV
719.8ps   247.3mV    656.3mV    21.9mV
864.5ps   81.88mV    656.3mV    17.34mV
1.591ns   15.93mV    607.5mV    6.683mV
1.978ns   10.59mV    119.9mV    5.546mV
2.509ns   3.423mV    2.084mV    4.971mV
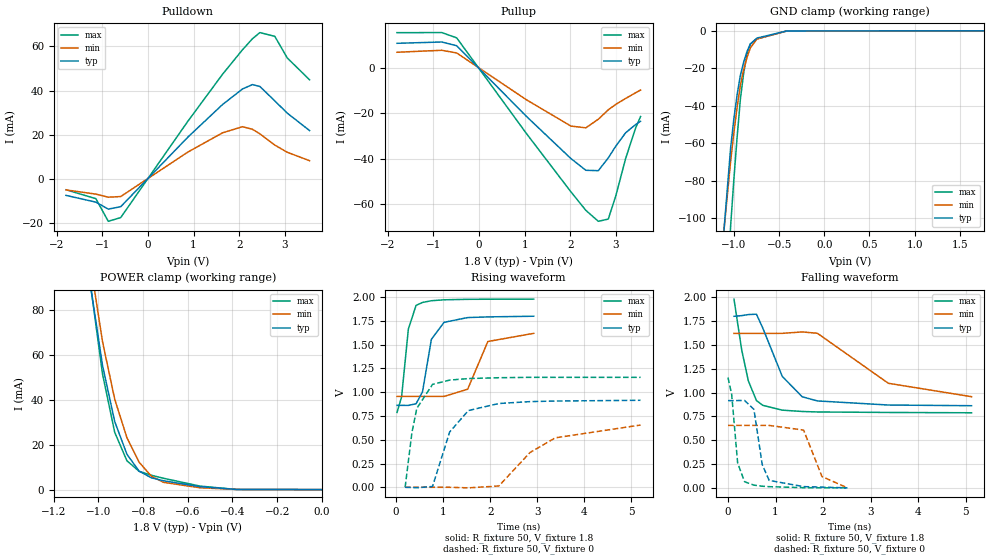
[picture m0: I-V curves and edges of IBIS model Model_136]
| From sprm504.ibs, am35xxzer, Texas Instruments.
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| Model based on original model for BC1833DV50BTPBFHP18LL_7LM
|   Sub model LL_7LM_PD_PU_OFF_1P8
[model]   Model_136
|[Description]  1.8V-I/O-PI-X
|[Input Load]   PI
|[Output Drive]
|Voltage   1.8V
|Mode   I/O
Model_type   I/O
Polarity   Non-Inverting
Enable   Active-Low
Vinl =  0.63V
Vinh =  1.17V
Cref =  15pF
Rref =  100.0000M
Vref =  0V
Vmeas =  0.9
C_comp   1.952094p   1.82457p   1.99685p
[Model Spec]
Vinl   0.63V   0.567V   0.693V
Vinh   1.17V   1.053V   1.287V
[Temperature Range]   25   125   -40
[Voltage Range]   1.8   1.62   1.98
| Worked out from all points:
|   slope of the pulldown table from 0 to 0.27 V, typ, clamps not added: 44.6 ohm
|   slope of the pullup table from 0 to 0.27 V, typ, clamps not added: 47.6 ohm
|   GND clamp passes 1 mA (typ) near -0.57 V on its own axis
|   POWER clamp passes 1 mA (typ) near -0.52 V on its own axis
|   rising waveform, R_fixture 50, V_fixture 1.8: 20-80 % time 214ps typ, 285ps min, 156ps max; typ from 0.862 V to 1.8 V
|   rising waveform, R_fixture 50, V_fixture 0: 20-80 % time 446ps typ, 984ps min, 247ps max; typ from 0 V to 0.915 V
|   falling waveform, R_fixture 50, V_fixture 1.8: 20-80 % time 530ps typ, 1.21ns min, 285ps max; typ from 1.8 V to 0.862 V
|   falling waveform, R_fixture 50, V_fixture 0: 20-80 % time 165ps typ, 255ps min, 125ps max; typ from 0.915 V to 0 V
[POWER_clamp]
-1.8V     833.3mA    863.1mA    901.2mA
-1.055V   105.1mA    114.2mA    107.4mA
-1.036V   90.81mA    100.3mA    91.25mA
-981.8mV  55.15mA    65.69mA    51.29mA
-927.3mV  30.24mA    40.16mA    25.46mA
-872.7mV  15.72mA    23.1mA     12.83mA
-818.2mV  8.229mA    12.21mA    8.14mA
-763.6mV  5.264mA    6.024mA    6.384mA
-709.1mV  3.941mA    3.245mA    5.044mA
-545.5mV  1.299mA    814.7uA    1.567mA
-381.8mV  77.04uA    69.31uA    55.06uA
0V        17.8nA     61.41nA    29.21nA
[Pulldown]
-1.8V     -7.339mA   -4.872mA   -4.803mA
-1.145V   -10.39mA   -6.769mA   -8.819mA
-872.7mV  -13.54mA   -8.159mA   -19.05mA
-600mV    -12.46mA   -7.873mA   -17.38mA
872.7mV   18.95mA    12.21mA    26.11mA
1.636V    33.73mA    20.94mA    47.4mA
2.073V    40.74mA    23.7mA     58.46mA
2.291V    42.72mA    22.53mA    63.43mA
2.455V    41.87mA    20.47mA    66.23mA
2.782V    35.36mA    15.4mA     64.52mA
3.055V    29.83mA    12.14mA    54.79mA
3.545V    21.95mA    8.339mA    44.87mA
[Pullup]
-1.8V     10.72mA    6.784mA    15.4mA
-818.2mV  11.29mA    7.651mA    15.44mA
-490.9mV  9.653mA    6.484mA    13.12mA
1.036V    -21.34mA   -14.06mA   -28.84mA
2.018V    -39.99mA   -25.69mA   -54.63mA
2.345V    -45.12mA   -26.45mA   -62.75mA
2.618V    -45.29mA   -22.66mA   -67.55mA
2.836V    -39.69mA   -18.55mA   -66.58mA
3V        -34.54mA   -16.15mA   -56.48mA
3.218V    -28.61mA   -13.52mA   -39.88mA
3.436V    -25.01mA   -11.02mA   -26.56mA
3.545V    -23.56mA   -9.84mA    -21.49mA
[GND_clamp]
-1.8V     -667.9mA   -536.4mA   -1.146A
-1.109V   -105.7mA   -105.8mA   -172.9mA
-1.036V   -62.16mA   -69.32mA   -103.8mA
-1V       -46.7mA    -54.02mA   -78.8mA
-963.6mV  -33.78mA   -40.45mA   -56.19mA
-927.3mV  -23.42mA   -28.63mA   -35.94mA
-890.9mV  -16.47mA   -20.58mA   -22.14mA
-854.5mV  -10.98mA   -14.08mA   -12.51mA
-818.2mV  -6.97mA    -9.126mA   -7.056mA
-745.5mV  -3.872mA   -4.367mA   -4.345mA
-418.2mV  -109.9uA   -163.2uA   -95.18uA
1.764V    17.35nA    376.2nA    24.84nA
[Ramp]
dV/dt_f 0.57990713/0.53502155n  0.4125211/1.2242655n  0.7256537/0.28467649n
dV/dt_r 0.56403119/0.4466216n 0.40498664/0.98412068n 0.70323421/0.24748722n
R_load = 50
[Rising Waveform]
R_fixture = 50
V_fixture = 1.8
V_fixture_min = 1.62
V_fixture_max = 1.98
20.39ps   861.8mV    956.4mV    787.7mV
117.9ps   861.8mV    956.4mV    951.1mV
261.6ps   861.6mV    956.4mV    1.665V
425ps     879.2mV    956.4mV    1.914V
561.4ps   1.003V     956.4mV    1.945V
750.3ps   1.557V     956.4mV    1.963V
1.02ns    1.736V     956.4mV    1.973V
1.521ns   1.786V     1.032V     1.978V
1.95ns    1.793V     1.534V     1.979V
2.924ns   1.8V       1.62V      1.98V
[Rising Waveform]
R_fixture = 50
V_fixture = 0
V_fixture_min = 0
V_fixture_max = 0
192.9ps   9.762nV    93.73nV    10.68nV
336.4ps   -2.252mV   2.23uV     572.5mV
440.3ps   -5.34mV    239.8nV    830mV
775ps     8.665mV    -2.489uV   1.083V
1.138ns   581.5mV    -137.2uV   1.128V
1.536ns   807.6mV    -6.056mV   1.144V
2.183ns   881.6mV    13.8mV     1.153V
2.847ns   901.5mV    366.6mV    1.157V
3.382ns   907.7mV    520.4mV    1.157V
5.193ns   915.5mV    655mV      1.157V
[Falling Waveform]
R_fixture = 50
V_fixture = 1.8
V_fixture_min = 1.62
V_fixture_max = 1.98
126.1ps   1.8V       1.62V      1.98V
288.6ps   1.807V     1.62V      1.445V
428.2ps   1.818V     1.62V      1.122V
598ps     1.822V     1.62V      916.5mV
730.1ps   1.679V     1.62V      866.1mV
1.142ns   1.169V     1.621V     815.2mV
1.562ns   955.5mV    1.636V     801.2mV
1.88ns    912.1mV    1.622V     796.3mV
3.375ns   869mV      1.097V     791mV
5.126ns   861.8mV    956.4mV    787.7mV
[Falling Waveform]
R_fixture = 50
V_fixture = 0
V_fixture_min = 0
V_fixture_max = 0
0s        915.5mV    655mV      1.157V
77.55ps   915.3mV    655mV      978.6mV
203ps     916.1mV    655mV      259.9mV
349.2ps   917mV      655mV      64.2mV
545.5ps   823.3mV    655mV      28.28mV
720.3ps   243.6mV    655mV      17.22mV
866.8ps   77.99mV    655mV      12.46mV
1.591ns   12.99mV    606.1mV    1.717mV
1.978ns   7.548mV    118.3mV    574uV
2.515ns   9.762nV    93.73nV    10.68nV
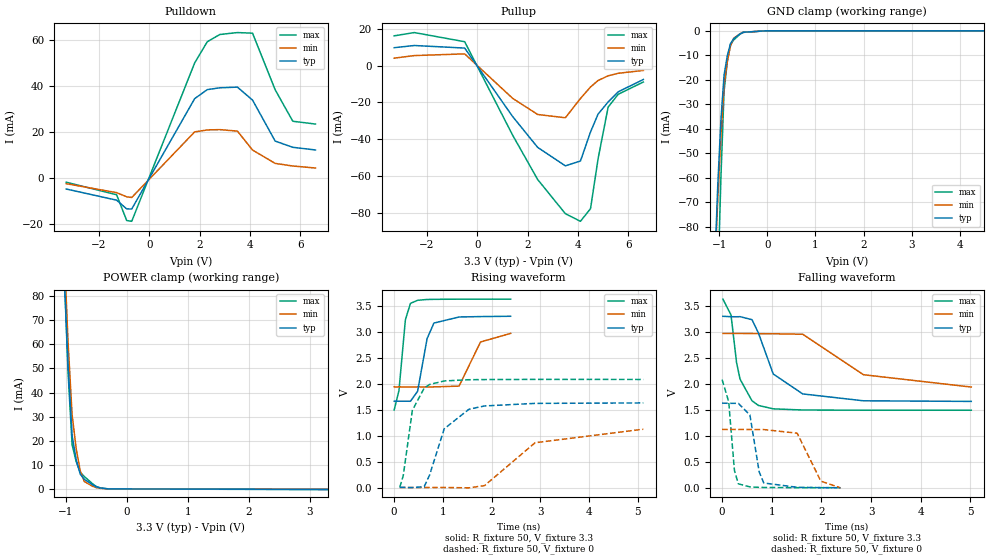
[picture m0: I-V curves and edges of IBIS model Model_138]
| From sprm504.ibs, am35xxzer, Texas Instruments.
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| Model based on original model for BC1833DV50BTPBFHP18LL_7LM
|   Sub model HP18LL_7LM_PU_ON_3P3
[model]   Model_138
|[Description]  3.3V-I/O-PU-X
|[Input Load]   PU
|[Output Drive]
|Voltage   3.3V
|Mode   I/O
Model_type   I/O
Polarity   Non-Inverting
Enable   Active-Low
Vinl =  0.8V
Vinh =  2V
Cref =  15pF
Rref =  100.0000M
Vref =  0V
Vmeas =  1.65
C_comp   1.683006p   1.492615p   1.787227p
[Model Spec]
Vinl   0.8V   0.8V   0.8V
Vinh   2V   2V   2V
[Temperature Range]   25   125   -40
[Voltage Range]   3.3   2.97   3.63
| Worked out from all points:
|   slope of the pulldown table from 0 to 0.495 V, typ, clamps not added: 44.6 ohm
|   slope of the pullup table from 0 to 0.495 V, typ, clamps not added: 49.2 ohm
|   GND clamp passes 1 mA (typ) near -0.54 V on its own axis
|   POWER clamp passes 1 mA (typ) near -0.51 V on its own axis
|   rising waveform, R_fixture 50, V_fixture 3.3: 20-80 % time 192ps typ, 276ps min, 121ps max; typ from 1.66 V to 3.3 V
|   rising waveform, R_fixture 50, V_fixture 0: 20-80 % time 424ps typ, 976ps min, 230ps max; typ from 0.004 V to 1.63 V
|   falling waveform, R_fixture 50, V_fixture 3.3: 20-80 % time 530ps typ, 989ps min, 229ps max; typ from 3.3 V to 1.66 V
|   falling waveform, R_fixture 50, V_fixture 0: 20-80 % time 154ps typ, 283ps min, 108ps max; typ from 1.63 V to 0.004 V
[POWER_clamp]
-3.3V     2.414A     2.855A     2.597A
-1.033V   91.28mA    100.7mA    91.91mA
-966.7mV  51.52mA    61.14mA    48.58mA
-900mV    22.2mA     30.8mA     18.38mA
-833.3mV  12.2mA     16.79mA    11.38mA
-766.7mV  6.143mA    7.564mA    6.979mA
-700mV    4.019mA    3.112mA    5.166mA
-566.7mV  1.785mA    1.14mA     2.219mA
-500mV    851.8uA    543.9uA    965.7uA
-433.3mV  384.1uA    260.8uA    410.7uA
-300mV    24.71uA    21.59uA    29.06uA
3.3V      -177.5uA   -136.2uA   -277.3uA
[Pulldown]
-3.3V     -4.655mA   -2.337mA   -1.677mA
-1.3V     -9.504mA   -6.223mA   -7.163mA
-900mV    -13.3mA    -8.026mA   -18.36mA
-700mV    -13.35mA   -8.345mA   -18.7mA
1.8V      34.68mA    20.21mA    50.21mA
2.3V      38.61mA    21.07mA    59.44mA
2.8V      39.41mA    21.2mA     62.61mA
3.5V      39.7mA     20.55mA    63.45mA
4.1V      34.07mA    12.32mA    63.18mA
5V        16.21mA    6.501mA    38.53mA
5.7V      13.51mA    5.366mA    24.85mA
6.6V      12.35mA    4.495mA    23.63mA
[Pullup]
-3.3V     9.687mA    4.009mA    16.14mA
-2.5V     10.88mA    5.407mA    17.91mA
-500mV    9.486mA    6.336mA    12.94mA
1.4V      -27.6mA    -17.76mA   -37.69mA
2.4V      -44.47mA   -26.6mA    -61.92mA
3.5V      -54.49mA   -28.37mA   -80.48mA
4.1V      -51.87mA   -17.91mA   -84.62mA
4.5V      -36.09mA   -11.65mA   -77.77mA
4.8V      -26.39mA   -8.135mA   -50.71mA
5.2V      -19.78mA   -5.578mA   -22.57mA
5.6V      -14.26mA   -4.206mA   -15.61mA
6.6V      -7.577mA   -2.662mA   -8.942mA
[GND_clamp]
-3.3V     -1.975A    -1.766A    -3.378A
-1.1V     -99.48mA   -100.9mA   -162.1mA
-1.033V   -63.84mA   -69.36mA   -106.2mA
-966.7mV  -36.69mA   -43.1mA    -60.37mA
-900mV    -18.03mA   -22.08mA   -24.58mA
-833.3mV  -10.18mA   -12.46mA   -12.65mA
-766.7mV  -5.239mA   -6.112mA   -5.698mA
-700mV    -3.207mA   -3.033mA   -3.732mA
-566.7mV  -1.248mA   -1.197mA   -1.338mA
-500mV    -586.1uA   -614.6uA   -635uA
-33.33mV  0A         0A         0A
6.6V      0A         0A         0A
[Ramp]
dV/dt_f 0.98186178/0.50550949n 0.61795928/0.98418836n  1.2807807/0.22772252n
dV/dt_r 0.98102986/0.42258606n  0.6782164/0.97168174n  1.2514503/0.22963458n
R_load = 50
[Rising Waveform]
R_fixture = 50
V_fixture = 3.3
V_fixture_min = 2.97
V_fixture_max = 3.63
283.2fs   1.664V     1.94V      1.495V
97.95ps   1.664V     1.94V      1.87V
230.1ps   1.664V     1.94V      3.233V
333.9ps   1.663V     1.94V      3.548V
480.7ps   1.855V     1.94V      3.608V
675.2ps   2.868V     1.94V      3.623V
815.3ps   3.169V     1.94V      3.626V
1.332ns   3.286V     1.955V     3.629V
1.772ns   3.294V     2.805V     3.63V
2.391ns   3.3V       2.97V      3.63V
[Rising Waveform]
R_fixture = 50
V_fixture = 0
V_fixture_min = 0
V_fixture_max = 0
114.9ps   4.13mV     2.525mV    5.944mV
185.9ps   4.135mV    2.525mV    230.5mV
372.9ps   1.527mV    2.525mV    1.488V
614.8ps   16.82mV    2.525mV    1.915V
725ps     237.6mV    2.525mV    1.986V
1.027ns   1.133V     2.54mV     2.054V
1.534ns   1.509V     -4.711mV   2.078V
1.855ns   1.573V     38.7mV     2.081V
2.892ns   1.622V     864.3mV    2.084V
5.115ns   1.631V     1.125V     2.083V
[Falling Waveform]
R_fixture = 50
V_fixture = 3.3
V_fixture_min = 2.97
V_fixture_max = 3.63
16ps      3.3V       2.97V      3.63V
179.1ps   3.292V     2.97V      3.327V
290.1ps   3.291V     2.97V      2.413V
361.4ps   3.293V     2.97V      2.091V
601.7ps   3.235V     2.969V     1.676V
730.9ps   2.979V     2.966V     1.587V
1.029ns   2.191V     2.964V     1.521V
1.623ns   1.808V     2.955V     1.499V
2.846ns   1.676V     2.177V     1.495V
5.016ns   1.664V     1.94V      1.495V
[Falling Waveform]
R_fixture = 50
V_fixture = 0
V_fixture_min = 0
V_fixture_max = 0
0s        1.631V     1.125V     2.083V
132.8ps   1.627V     1.125V     1.657V
248.4ps   1.627V     1.125V     333.5mV
326.1ps   1.627V     1.125V     80.21mV
559.5ps   1.404V     1.124V     20.99mV
746.2ps   308.9mV    1.123V     12.59mV
839ps     96.07mV    1.123V     10.05mV
1.511ns   13.12mV    1.053V     6.074mV
1.987ns   7.366mV    131.9mV    5.961mV
2.384ns   4.13mV     2.525mV    5.944mV
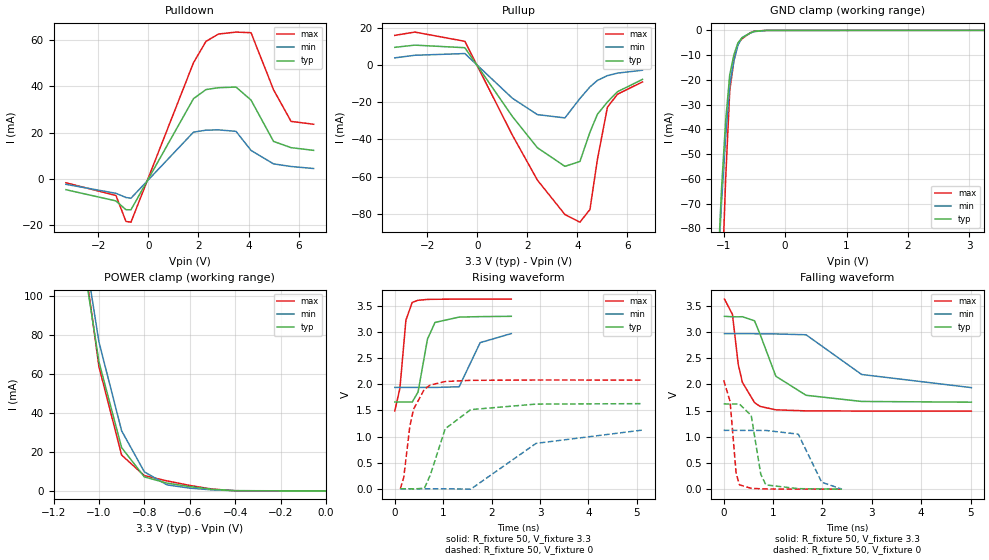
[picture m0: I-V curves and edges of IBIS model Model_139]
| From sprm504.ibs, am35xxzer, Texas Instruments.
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| Model based on original model for BC1833DV50BTPBFHP18LL_7LM
|   Sub model LL_7LM_PD_PU_OFF_3P3
[model]   Model_139
|[Description]  3.3V-I/O-PI-X
|[Input Load]   PI
|[Output Drive]
|Voltage   3.3V
|Mode   I/O
Model_type   I/O
Polarity   Non-Inverting
Enable   Active-Low
Vinl =  0.8V
Vinh =  2V
Cref =  15pF
Rref =  100.0000M
Vref =  0V
Vmeas =  1.65
C_comp   1.683006p   1.492615p   1.787227p
[Model Spec]
Vinl   0.8V   0.8V   0.8V
Vinh   2V   2V   2V
[Temperature Range]   25   125   -40
[Voltage Range]   3.3   2.97   3.63
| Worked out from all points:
|   slope of the pulldown table from 0 to 0.495 V, typ, clamps not added: 44.6 ohm
|   slope of the pullup table from 0 to 0.495 V, typ, clamps not added: 49.2 ohm
|   GND clamp passes 1 mA (typ) near -0.56 V on its own axis
|   POWER clamp passes 1 mA (typ) near -0.51 V on its own axis
|   rising waveform, R_fixture 50, V_fixture 3.3: 20-80 % time 193ps typ, 277ps min, 121ps max; typ from 1.66 V to 3.3 V
|   rising waveform, R_fixture 50, V_fixture 0: 20-80 % time 427ps typ, 1.01ns min, 232ps max; typ from 0 V to 1.63 V
|   falling waveform, R_fixture 50, V_fixture 3.3: 20-80 % time 520ps typ, 991ps min, 229ps max; typ from 3.3 V to 1.66 V
|   falling waveform, R_fixture 50, V_fixture 0: 20-80 % time 154ps typ, 283ps min, 108ps max; typ from 1.63 V to 0 V
[POWER_clamp]
-3.3V     2.414A     2.855A     2.597A
-1.067V   116.4mA    125.1mA    120.1mA
-1.033V   91.27mA    100.7mA    91.89mA
-1V       66.16mA    76.3mA     63.65mA
-900mV    22.18mA    30.79mA    18.35mA
-800mV    7.186mA    9.78mA     7.855mA
-700mV    3.999mA    3.101mA    5.133mA
-600mV    2.231mA    1.427mA    2.811mA
-500mV    830.8uA    532.6uA    931.1uA
-400mV    130.7uA    108.8uA    101.5uA
0V        9.334nA    42.91nA    36.63nA
[Pulldown]
-3.3V     -4.655mA   -2.337mA   -1.677mA
-1.3V     -9.504mA   -6.223mA   -7.163mA
-900mV    -13.3mA    -8.026mA   -18.36mA
-700mV    -13.35mA   -8.345mA   -18.7mA
1.8V      34.68mA    20.21mA    50.21mA
2.3V      38.61mA    21.07mA    59.44mA
2.8V      39.41mA    21.2mA     62.61mA
3.5V      39.7mA     20.55mA    63.45mA
4.1V      34.07mA    12.32mA    63.18mA
5V        16.21mA    6.501mA    38.53mA
5.7V      13.51mA    5.366mA    24.85mA
6.6V      12.35mA    4.495mA    23.63mA
[Pullup]
-3.3V     9.687mA    4.009mA    16.14mA
-2.5V     10.88mA    5.407mA    17.91mA
-500mV    9.486mA    6.336mA    12.94mA
1.4V      -27.6mA    -17.76mA   -37.69mA
2.4V      -44.47mA   -26.6mA    -61.92mA
3.5V      -54.49mA   -28.37mA   -80.48mA
4.1V      -51.87mA   -17.91mA   -84.62mA
4.5V      -36.09mA   -11.65mA   -77.77mA
4.8V      -26.39mA   -8.135mA   -50.71mA
5.2V      -19.78mA   -5.578mA   -22.57mA
5.6V      -14.26mA   -4.206mA   -15.61mA
6.6V      -7.577mA   -2.662mA   -8.942mA
[GND_clamp]
-3.3V     -1.975A    -1.766A    -3.378A
-1.1V     -99.4mA    -100.8mA   -162mA
-1.033V   -63.74mA   -69.32mA   -106.1mA
-966.7mV  -36.57mA   -43.05mA   -60.18mA
-900mV    -17.88mA   -22.01mA   -24.32mA
-833.3mV  -10mA      -12.38mA   -12.34mA
-766.7mV  -5.046mA   -6.023mA   -5.36mA
-700mV    -3.007mA   -2.937mA   -3.388mA
-566.7mV  -1.046mA   -1.097mA   -993.1uA
-500mV    -384.7uA   -514.4uA   -290.6uA
-300mV    -14.31uA   -22.54uA   -14.39uA
3.233V    8.947nA    10.19uA    33.58nA
[Ramp]
dV/dt_f 0.98336827/0.50689875n 0.61878129/0.98744798n  1.2831261/0.2283652n
dV/dt_r 0.98219906/0.4251161n 0.67873483/0.97554692n  1.2533883/0.23152175n
R_load = 50
[Rising Waveform]
R_fixture = 50
V_fixture = 3.3
V_fixture_min = 2.97
V_fixture_max = 3.63
438.4fs   1.661V     1.939V     1.491V
105.6ps   1.661V     1.939V     1.921V
230ps     1.661V     1.939V     3.227V
359.7ps   1.659V     1.939V     3.566V
480.7ps   1.851V     1.939V     3.607V
674.6ps   2.862V     1.939V     3.623V
830.5ps   3.183V     1.939V     3.626V
1.329ns   3.285V     1.952V     3.629V
1.763ns   3.294V     2.796V     3.63V
2.406ns   3.3V       2.97V      3.63V
[Rising Waveform]
R_fixture = 50
V_fixture = 0
V_fixture_min = 0
V_fixture_max = 0
115.2ps   8.191nV    109.8nV    4.108nV
185.9ps   4.524uV    -360.2nV   222.5mV
309.9ps   -337.5uV   -429nV     1.189V
386.4ps   -3.83mV    -11nV      1.521V
612.5ps   10.63mV    187.9nV    1.907V
735.2ps   266.8mV    7.032nV    1.986V
1.04ns    1.147V     19.54uV    2.052V
1.569ns   1.515V     -7.65mV    2.075V
2.918ns   1.62V      869mV      2.081V
5.115ns   1.629V     1.123V     2.08V
[Falling Waveform]
R_fixture = 50
V_fixture = 3.3
V_fixture_min = 2.97
V_fixture_max = 3.63
15.99ps   3.3V       2.97V      3.63V
176.9ps   3.292V     2.97V      3.337V
294.8ps   3.291V     2.97V      2.382V
378.2ps   3.293V     2.97V      2.041V
623.9ps   3.215V     2.968V     1.653V
737.5ps   2.956V     2.966V     1.58V
1.056ns   2.156V     2.964V     1.515V
1.668ns   1.793V     2.948V     1.495V
2.793ns   1.675V     2.19V      1.492V
5.016ns   1.661V     1.939V     1.491V
[Falling Waveform]
R_fixture = 50
V_fixture = 0
V_fixture_min = 0
V_fixture_max = 0
0s        1.629V     1.123V     2.08V
129.7ps   1.625V     1.123V     1.674V
251.3ps   1.625V     1.123V     304.6mV
319.3ps   1.625V     1.123V     82.64mV
557.8ps   1.406V     1.122V     16.23mV
750.6ps   285.9mV    1.121V     7.042mV
854.3ps   81.06mV    1.121V     4.163mV
1.51ns    9.834mV    1.051V     161.4uV
1.985ns   3.834mV    131.5mV    20.84uV
2.395ns   8.191nV    109.8nV    4.108nV
